VERSION 5.8 ;
BUSBITCHARS "[]" ;
DIVIDERCHAR "/" ;
UNITS
    DATABASE MICRONS 1000 ;
END UNITS

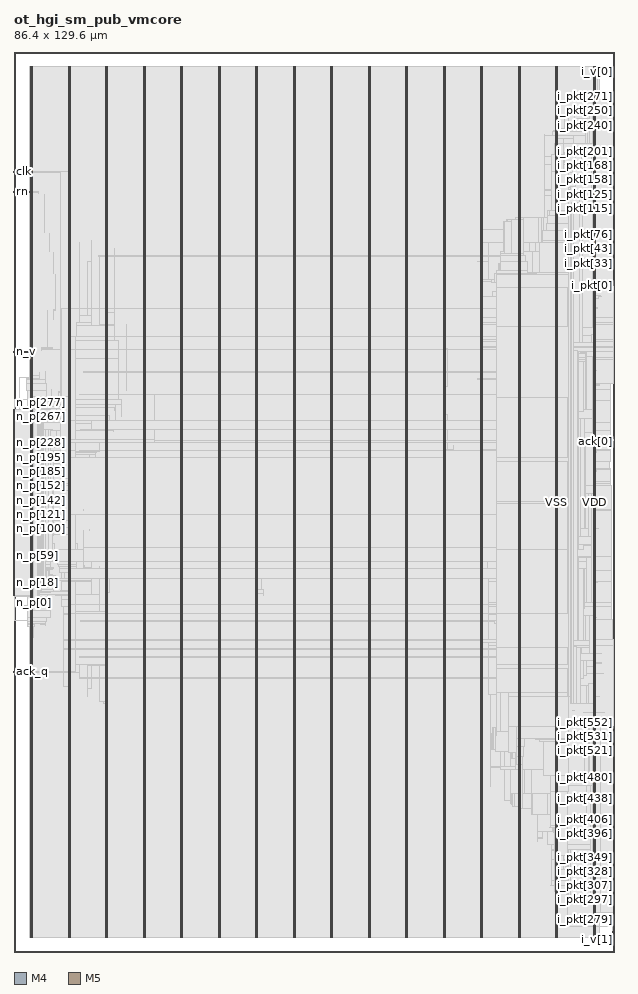
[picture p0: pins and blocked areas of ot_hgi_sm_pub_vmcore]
MACRO ot_hgi_sm_pub_vmcore
  FOREIGN ot_hgi_sm_pub_vmcore 0 0 ;
  CLASS BLOCK ;
  SIZE 86.4 BY 129.6 ;
  PIN ack[0]
    DIRECTION OUTPUT ;
    USE SIGNAL ;
    PORT
      LAYER M4 ;
        RECT  86.358 73.44 86.442 73.464 ;
    END
  END ack[0]
  PIN ack[1]
    DIRECTION OUTPUT ;
    USE SIGNAL ;
    PORT
      LAYER M4 ;
        RECT  86.358 73.536 86.442 73.56 ;
    END
  END ack[1]
  PIN ack_q
    DIRECTION INPUT ;
    USE SIGNAL ;
    PORT
      LAYER M4 ;
        RECT  -0.042 40.32 0.042 40.344 ;
    END
    PORT
      LAYER M4 ;
        RECT  0.012 40.32 2.408 40.344 ;
    END
  END ack_q
  PIN clk
    DIRECTION INPUT ;
    USE SIGNAL ;
    PORT
      LAYER M4 ;
        RECT  -0.042 112.32 0.042 112.344 ;
    END
    PORT
      LAYER M4 ;
        RECT  0.012 112.32 0.025 112.344 ;
    END
    PORT
      LAYER M4 ;
        RECT  0.025 112.32 0.065 112.44 ;
    END
  END clk
  PIN i_pkt[0]
    DIRECTION INPUT ;
    USE SIGNAL ;
    PORT
      LAYER M4 ;
        RECT  86.358 96 86.442 96.024 ;
    END
  END i_pkt[0]
  PIN i_pkt[100]
    DIRECTION INPUT ;
    USE SIGNAL ;
    PORT
      LAYER M4 ;
        RECT  86.358 105.6 86.442 105.624 ;
    END
  END i_pkt[100]
  PIN i_pkt[101]
    DIRECTION INPUT ;
    USE SIGNAL ;
    PORT
      LAYER M4 ;
        RECT  86.358 105.696 86.442 105.72 ;
    END
  END i_pkt[101]
  PIN i_pkt[102]
    DIRECTION INPUT ;
    USE SIGNAL ;
    PORT
      LAYER M4 ;
        RECT  86.358 105.792 86.442 105.816 ;
    END
  END i_pkt[102]
  PIN i_pkt[103]
    DIRECTION INPUT ;
    USE SIGNAL ;
    PORT
      LAYER M4 ;
        RECT  86.358 105.888 86.442 105.912 ;
    END
  END i_pkt[103]
  PIN i_pkt[104]
    DIRECTION INPUT ;
    USE SIGNAL ;
    PORT
      LAYER M4 ;
        RECT  86.358 105.984 86.442 106.008 ;
    END
  END i_pkt[104]
  PIN i_pkt[105]
    DIRECTION INPUT ;
    USE SIGNAL ;
    PORT
      LAYER M4 ;
        RECT  86.358 106.08 86.442 106.104 ;
    END
  END i_pkt[105]
  PIN i_pkt[106]
    DIRECTION INPUT ;
    USE SIGNAL ;
    PORT
      LAYER M4 ;
        RECT  86.358 106.176 86.442 106.2 ;
    END
  END i_pkt[106]
  PIN i_pkt[107]
    DIRECTION INPUT ;
    USE SIGNAL ;
    PORT
      LAYER M4 ;
        RECT  86.358 106.272 86.442 106.296 ;
    END
  END i_pkt[107]
  PIN i_pkt[108]
    DIRECTION INPUT ;
    USE SIGNAL ;
    PORT
      LAYER M4 ;
        RECT  86.358 106.368 86.442 106.392 ;
    END
  END i_pkt[108]
  PIN i_pkt[109]
    DIRECTION INPUT ;
    USE SIGNAL ;
    PORT
      LAYER M4 ;
        RECT  86.358 106.464 86.442 106.488 ;
    END
  END i_pkt[109]
  PIN i_pkt[10]
    DIRECTION INPUT ;
    USE SIGNAL ;
    PORT
      LAYER M4 ;
        RECT  86.358 96.96 86.442 96.984 ;
    END
  END i_pkt[10]
  PIN i_pkt[110]
    DIRECTION INPUT ;
    USE SIGNAL ;
    PORT
      LAYER M4 ;
        RECT  86.358 106.56 86.442 106.584 ;
    END
  END i_pkt[110]
  PIN i_pkt[111]
    DIRECTION INPUT ;
    USE SIGNAL ;
    PORT
      LAYER M4 ;
        RECT  86.358 106.656 86.442 106.68 ;
    END
  END i_pkt[111]
  PIN i_pkt[112]
    DIRECTION INPUT ;
    USE SIGNAL ;
    PORT
      LAYER M4 ;
        RECT  86.358 106.752 86.442 106.776 ;
    END
  END i_pkt[112]
  PIN i_pkt[113]
    DIRECTION INPUT ;
    USE SIGNAL ;
    PORT
      LAYER M4 ;
        RECT  86.358 106.848 86.442 106.872 ;
    END
  END i_pkt[113]
  PIN i_pkt[114]
    DIRECTION INPUT ;
    USE SIGNAL ;
    PORT
      LAYER M4 ;
        RECT  86.358 106.944 86.442 106.968 ;
    END
  END i_pkt[114]
  PIN i_pkt[115]
    DIRECTION INPUT ;
    USE SIGNAL ;
    PORT
      LAYER M4 ;
        RECT  86.358 107.04 86.442 107.064 ;
    END
  END i_pkt[115]
  PIN i_pkt[116]
    DIRECTION INPUT ;
    USE SIGNAL ;
    PORT
      LAYER M4 ;
        RECT  86.358 107.136 86.442 107.16 ;
    END
  END i_pkt[116]
  PIN i_pkt[117]
    DIRECTION INPUT ;
    USE SIGNAL ;
    PORT
      LAYER M4 ;
        RECT  86.358 107.232 86.442 107.256 ;
    END
  END i_pkt[117]
  PIN i_pkt[118]
    DIRECTION INPUT ;
    USE SIGNAL ;
    PORT
      LAYER M4 ;
        RECT  86.358 107.328 86.442 107.352 ;
    END
  END i_pkt[118]
  PIN i_pkt[119]
    DIRECTION INPUT ;
    USE SIGNAL ;
    PORT
      LAYER M4 ;
        RECT  86.358 107.424 86.442 107.448 ;
    END
  END i_pkt[119]
  PIN i_pkt[11]
    DIRECTION INPUT ;
    USE SIGNAL ;
    PORT
      LAYER M4 ;
        RECT  86.358 97.056 86.442 97.08 ;
    END
  END i_pkt[11]
  PIN i_pkt[120]
    DIRECTION INPUT ;
    USE SIGNAL ;
    PORT
      LAYER M4 ;
        RECT  86.358 107.52 86.442 107.544 ;
    END
  END i_pkt[120]
  PIN i_pkt[121]
    DIRECTION INPUT ;
    USE SIGNAL ;
    PORT
      LAYER M4 ;
        RECT  86.358 107.616 86.442 107.64 ;
    END
  END i_pkt[121]
  PIN i_pkt[122]
    DIRECTION INPUT ;
    USE SIGNAL ;
    PORT
      LAYER M4 ;
        RECT  86.358 107.712 86.442 107.736 ;
    END
  END i_pkt[122]
  PIN i_pkt[123]
    DIRECTION INPUT ;
    USE SIGNAL ;
    PORT
      LAYER M4 ;
        RECT  86.358 107.808 86.442 107.832 ;
    END
  END i_pkt[123]
  PIN i_pkt[124]
    DIRECTION INPUT ;
    USE SIGNAL ;
    PORT
      LAYER M4 ;
        RECT  86.358 107.904 86.442 107.928 ;
    END
  END i_pkt[124]
  PIN i_pkt[125]
    DIRECTION INPUT ;
    USE SIGNAL ;
    PORT
      LAYER M4 ;
        RECT  86.358 108 86.442 108.024 ;
    END
  END i_pkt[125]
  PIN i_pkt[126]
    DIRECTION INPUT ;
    USE SIGNAL ;
    PORT
      LAYER M4 ;
        RECT  86.358 108.096 86.442 108.12 ;
    END
  END i_pkt[126]
  PIN i_pkt[127]
    DIRECTION INPUT ;
    USE SIGNAL ;
    PORT
      LAYER M4 ;
        RECT  86.358 108.192 86.442 108.216 ;
    END
  END i_pkt[127]
  PIN i_pkt[128]
    DIRECTION INPUT ;
    USE SIGNAL ;
    PORT
      LAYER M4 ;
        RECT  86.358 108.288 86.442 108.312 ;
    END
  END i_pkt[128]
  PIN i_pkt[129]
    DIRECTION INPUT ;
    USE SIGNAL ;
    PORT
      LAYER M4 ;
        RECT  86.358 108.384 86.442 108.408 ;
    END
  END i_pkt[129]
  PIN i_pkt[12]
    DIRECTION INPUT ;
    USE SIGNAL ;
    PORT
      LAYER M4 ;
        RECT  86.358 97.152 86.442 97.176 ;
    END
  END i_pkt[12]
  PIN i_pkt[130]
    DIRECTION INPUT ;
    USE SIGNAL ;
    PORT
      LAYER M4 ;
        RECT  86.358 108.48 86.442 108.504 ;
    END
  END i_pkt[130]
  PIN i_pkt[131]
    DIRECTION INPUT ;
    USE SIGNAL ;
    PORT
      LAYER M4 ;
        RECT  86.358 108.576 86.442 108.6 ;
    END
  END i_pkt[131]
  PIN i_pkt[132]
    DIRECTION INPUT ;
    USE SIGNAL ;
    PORT
      LAYER M4 ;
        RECT  86.358 108.672 86.442 108.696 ;
    END
  END i_pkt[132]
  PIN i_pkt[133]
    DIRECTION INPUT ;
    USE SIGNAL ;
    PORT
      LAYER M4 ;
        RECT  86.358 108.768 86.442 108.792 ;
    END
  END i_pkt[133]
  PIN i_pkt[134]
    DIRECTION INPUT ;
    USE SIGNAL ;
    PORT
      LAYER M4 ;
        RECT  86.358 108.864 86.442 108.888 ;
    END
  END i_pkt[134]
  PIN i_pkt[135]
    DIRECTION INPUT ;
    USE SIGNAL ;
    PORT
      LAYER M4 ;
        RECT  86.358 108.96 86.442 108.984 ;
    END
  END i_pkt[135]
  PIN i_pkt[136]
    DIRECTION INPUT ;
    USE SIGNAL ;
    PORT
      LAYER M4 ;
        RECT  86.358 109.056 86.442 109.08 ;
    END
  END i_pkt[136]
  PIN i_pkt[137]
    DIRECTION INPUT ;
    USE SIGNAL ;
    PORT
      LAYER M4 ;
        RECT  86.358 109.152 86.442 109.176 ;
    END
  END i_pkt[137]
  PIN i_pkt[138]
    DIRECTION INPUT ;
    USE SIGNAL ;
    PORT
      LAYER M4 ;
        RECT  86.358 109.248 86.442 109.272 ;
    END
  END i_pkt[138]
  PIN i_pkt[139]
    DIRECTION INPUT ;
    USE SIGNAL ;
    PORT
      LAYER M4 ;
        RECT  86.358 109.344 86.442 109.368 ;
    END
  END i_pkt[139]
  PIN i_pkt[13]
    DIRECTION INPUT ;
    USE SIGNAL ;
    PORT
      LAYER M4 ;
        RECT  86.358 97.248 86.442 97.272 ;
    END
  END i_pkt[13]
  PIN i_pkt[140]
    DIRECTION INPUT ;
    USE SIGNAL ;
    PORT
      LAYER M4 ;
        RECT  86.358 109.44 86.442 109.464 ;
    END
  END i_pkt[140]
  PIN i_pkt[141]
    DIRECTION INPUT ;
    USE SIGNAL ;
    PORT
      LAYER M4 ;
        RECT  86.358 109.536 86.442 109.56 ;
    END
  END i_pkt[141]
  PIN i_pkt[142]
    DIRECTION INPUT ;
    USE SIGNAL ;
    PORT
      LAYER M4 ;
        RECT  86.358 109.632 86.442 109.656 ;
    END
  END i_pkt[142]
  PIN i_pkt[143]
    DIRECTION INPUT ;
    USE SIGNAL ;
    PORT
      LAYER M4 ;
        RECT  86.358 109.728 86.442 109.752 ;
    END
  END i_pkt[143]
  PIN i_pkt[144]
    DIRECTION INPUT ;
    USE SIGNAL ;
    PORT
      LAYER M4 ;
        RECT  86.358 109.824 86.442 109.848 ;
    END
  END i_pkt[144]
  PIN i_pkt[145]
    DIRECTION INPUT ;
    USE SIGNAL ;
    PORT
      LAYER M4 ;
        RECT  86.358 109.92 86.442 109.944 ;
    END
  END i_pkt[145]
  PIN i_pkt[146]
    DIRECTION INPUT ;
    USE SIGNAL ;
    PORT
      LAYER M4 ;
        RECT  86.358 110.016 86.442 110.04 ;
    END
  END i_pkt[146]
  PIN i_pkt[147]
    DIRECTION INPUT ;
    USE SIGNAL ;
    PORT
      LAYER M4 ;
        RECT  86.358 110.112 86.442 110.136 ;
    END
  END i_pkt[147]
  PIN i_pkt[148]
    DIRECTION INPUT ;
    USE SIGNAL ;
    PORT
      LAYER M4 ;
        RECT  86.358 110.208 86.442 110.232 ;
    END
  END i_pkt[148]
  PIN i_pkt[149]
    DIRECTION INPUT ;
    USE SIGNAL ;
    PORT
      LAYER M4 ;
        RECT  86.358 110.304 86.442 110.328 ;
    END
  END i_pkt[149]
  PIN i_pkt[14]
    DIRECTION INPUT ;
    USE SIGNAL ;
    PORT
      LAYER M4 ;
        RECT  86.358 97.344 86.442 97.368 ;
    END
  END i_pkt[14]
  PIN i_pkt[150]
    DIRECTION INPUT ;
    USE SIGNAL ;
    PORT
      LAYER M4 ;
        RECT  86.358 110.4 86.442 110.424 ;
    END
  END i_pkt[150]
  PIN i_pkt[151]
    DIRECTION INPUT ;
    USE SIGNAL ;
    PORT
      LAYER M4 ;
        RECT  86.358 110.496 86.442 110.52 ;
    END
  END i_pkt[151]
  PIN i_pkt[152]
    DIRECTION INPUT ;
    USE SIGNAL ;
    PORT
      LAYER M4 ;
        RECT  86.358 110.592 86.442 110.616 ;
    END
  END i_pkt[152]
  PIN i_pkt[153]
    DIRECTION INPUT ;
    USE SIGNAL ;
    PORT
      LAYER M4 ;
        RECT  86.358 110.688 86.442 110.712 ;
    END
  END i_pkt[153]
  PIN i_pkt[154]
    DIRECTION INPUT ;
    USE SIGNAL ;
    PORT
      LAYER M4 ;
        RECT  86.358 110.784 86.442 110.808 ;
    END
  END i_pkt[154]
  PIN i_pkt[155]
    DIRECTION INPUT ;
    USE SIGNAL ;
    PORT
      LAYER M4 ;
        RECT  86.358 110.88 86.442 110.904 ;
    END
  END i_pkt[155]
  PIN i_pkt[156]
    DIRECTION INPUT ;
    USE SIGNAL ;
    PORT
      LAYER M4 ;
        RECT  86.358 110.976 86.442 111 ;
    END
  END i_pkt[156]
  PIN i_pkt[157]
    DIRECTION INPUT ;
    USE SIGNAL ;
    PORT
      LAYER M4 ;
        RECT  86.358 111.072 86.442 111.096 ;
    END
  END i_pkt[157]
  PIN i_pkt[158]
    DIRECTION INPUT ;
    USE SIGNAL ;
    PORT
      LAYER M4 ;
        RECT  86.358 111.168 86.442 111.192 ;
    END
  END i_pkt[158]
  PIN i_pkt[159]
    DIRECTION INPUT ;
    USE SIGNAL ;
    PORT
      LAYER M4 ;
        RECT  86.358 111.264 86.442 111.288 ;
    END
  END i_pkt[159]
  PIN i_pkt[15]
    DIRECTION INPUT ;
    USE SIGNAL ;
    PORT
      LAYER M4 ;
        RECT  86.358 97.44 86.442 97.464 ;
    END
  END i_pkt[15]
  PIN i_pkt[160]
    DIRECTION INPUT ;
    USE SIGNAL ;
    PORT
      LAYER M4 ;
        RECT  86.358 111.36 86.442 111.384 ;
    END
  END i_pkt[160]
  PIN i_pkt[161]
    DIRECTION INPUT ;
    USE SIGNAL ;
    PORT
      LAYER M4 ;
        RECT  86.358 111.456 86.442 111.48 ;
    END
  END i_pkt[161]
  PIN i_pkt[162]
    DIRECTION INPUT ;
    USE SIGNAL ;
    PORT
      LAYER M4 ;
        RECT  86.358 111.552 86.442 111.576 ;
    END
  END i_pkt[162]
  PIN i_pkt[163]
    DIRECTION INPUT ;
    USE SIGNAL ;
    PORT
      LAYER M4 ;
        RECT  86.358 111.648 86.442 111.672 ;
    END
  END i_pkt[163]
  PIN i_pkt[164]
    DIRECTION INPUT ;
    USE SIGNAL ;
    PORT
      LAYER M4 ;
        RECT  86.358 111.744 86.442 111.768 ;
    END
  END i_pkt[164]
  PIN i_pkt[165]
    DIRECTION INPUT ;
    USE SIGNAL ;
    PORT
      LAYER M4 ;
        RECT  86.358 111.84 86.442 111.864 ;
    END
  END i_pkt[165]
  PIN i_pkt[166]
    DIRECTION INPUT ;
    USE SIGNAL ;
    PORT
      LAYER M4 ;
        RECT  86.358 111.936 86.442 111.96 ;
    END
  END i_pkt[166]
  PIN i_pkt[167]
    DIRECTION INPUT ;
    USE SIGNAL ;
    PORT
      LAYER M4 ;
        RECT  86.358 112.032 86.442 112.056 ;
    END
  END i_pkt[167]
  PIN i_pkt[168]
    DIRECTION INPUT ;
    USE SIGNAL ;
    PORT
      LAYER M4 ;
        RECT  86.358 112.128 86.442 112.152 ;
    END
  END i_pkt[168]
  PIN i_pkt[169]
    DIRECTION INPUT ;
    USE SIGNAL ;
    PORT
      LAYER M4 ;
        RECT  86.358 112.224 86.442 112.248 ;
    END
  END i_pkt[169]
  PIN i_pkt[16]
    DIRECTION INPUT ;
    USE SIGNAL ;
    PORT
      LAYER M4 ;
        RECT  86.358 97.536 86.442 97.56 ;
    END
  END i_pkt[16]
  PIN i_pkt[170]
    DIRECTION INPUT ;
    USE SIGNAL ;
    PORT
      LAYER M4 ;
        RECT  86.358 112.32 86.442 112.344 ;
    END
  END i_pkt[170]
  PIN i_pkt[171]
    DIRECTION INPUT ;
    USE SIGNAL ;
    PORT
      LAYER M4 ;
        RECT  86.358 112.416 86.442 112.44 ;
    END
  END i_pkt[171]
  PIN i_pkt[172]
    DIRECTION INPUT ;
    USE SIGNAL ;
    PORT
      LAYER M4 ;
        RECT  86.358 112.512 86.442 112.536 ;
    END
  END i_pkt[172]
  PIN i_pkt[173]
    DIRECTION INPUT ;
    USE SIGNAL ;
    PORT
      LAYER M4 ;
        RECT  86.358 112.608 86.442 112.632 ;
    END
  END i_pkt[173]
  PIN i_pkt[174]
    DIRECTION INPUT ;
    USE SIGNAL ;
    PORT
      LAYER M4 ;
        RECT  86.358 112.704 86.442 112.728 ;
    END
  END i_pkt[174]
  PIN i_pkt[175]
    DIRECTION INPUT ;
    USE SIGNAL ;
    PORT
      LAYER M4 ;
        RECT  86.358 112.8 86.442 112.824 ;
    END
  END i_pkt[175]
  PIN i_pkt[176]
    DIRECTION INPUT ;
    USE SIGNAL ;
    PORT
      LAYER M4 ;
        RECT  86.358 112.896 86.442 112.92 ;
    END
  END i_pkt[176]
  PIN i_pkt[177]
    DIRECTION INPUT ;
    USE SIGNAL ;
    PORT
      LAYER M4 ;
        RECT  86.358 112.992 86.442 113.016 ;
    END
  END i_pkt[177]
  PIN i_pkt[178]
    DIRECTION INPUT ;
    USE SIGNAL ;
    PORT
      LAYER M4 ;
        RECT  86.358 113.088 86.442 113.112 ;
    END
  END i_pkt[178]
  PIN i_pkt[179]
    DIRECTION INPUT ;
    USE SIGNAL ;
    PORT
      LAYER M4 ;
        RECT  86.358 113.184 86.442 113.208 ;
    END
  END i_pkt[179]
  PIN i_pkt[17]
    DIRECTION INPUT ;
    USE SIGNAL ;
    PORT
      LAYER M4 ;
        RECT  86.358 97.632 86.442 97.656 ;
    END
  END i_pkt[17]
  PIN i_pkt[180]
    DIRECTION INPUT ;
    USE SIGNAL ;
    PORT
      LAYER M4 ;
        RECT  86.358 113.28 86.442 113.304 ;
    END
  END i_pkt[180]
  PIN i_pkt[181]
    DIRECTION INPUT ;
    USE SIGNAL ;
    PORT
      LAYER M4 ;
        RECT  86.358 113.376 86.442 113.4 ;
    END
  END i_pkt[181]
  PIN i_pkt[182]
    DIRECTION INPUT ;
    USE SIGNAL ;
    PORT
      LAYER M4 ;
        RECT  86.358 113.472 86.442 113.496 ;
    END
  END i_pkt[182]
  PIN i_pkt[183]
    DIRECTION INPUT ;
    USE SIGNAL ;
    PORT
      LAYER M4 ;
        RECT  86.358 113.568 86.442 113.592 ;
    END
  END i_pkt[183]
  PIN i_pkt[184]
    DIRECTION INPUT ;
    USE SIGNAL ;
    PORT
      LAYER M4 ;
        RECT  86.358 113.664 86.442 113.688 ;
    END
  END i_pkt[184]
  PIN i_pkt[185]
    DIRECTION INPUT ;
    USE SIGNAL ;
    PORT
      LAYER M4 ;
        RECT  86.358 113.76 86.442 113.784 ;
    END
  END i_pkt[185]
  PIN i_pkt[186]
    DIRECTION INPUT ;
    USE SIGNAL ;
    PORT
      LAYER M4 ;
        RECT  86.358 113.856 86.442 113.88 ;
    END
  END i_pkt[186]
  PIN i_pkt[187]
    DIRECTION INPUT ;
    USE SIGNAL ;
    PORT
      LAYER M4 ;
        RECT  86.358 113.952 86.442 113.976 ;
    END
  END i_pkt[187]
  PIN i_pkt[188]
    DIRECTION INPUT ;
    USE SIGNAL ;
    PORT
      LAYER M4 ;
        RECT  86.358 114.048 86.442 114.072 ;
    END
  END i_pkt[188]
  PIN i_pkt[189]
    DIRECTION INPUT ;
    USE SIGNAL ;
    PORT
      LAYER M4 ;
        RECT  86.358 114.144 86.442 114.168 ;
    END
  END i_pkt[189]
  PIN i_pkt[18]
    DIRECTION INPUT ;
    USE SIGNAL ;
    PORT
      LAYER M4 ;
        RECT  86.358 97.728 86.442 97.752 ;
    END
  END i_pkt[18]
  PIN i_pkt[190]
    DIRECTION INPUT ;
    USE SIGNAL ;
    PORT
      LAYER M4 ;
        RECT  86.358 114.24 86.442 114.264 ;
    END
  END i_pkt[190]
  PIN i_pkt[191]
    DIRECTION INPUT ;
    USE SIGNAL ;
    PORT
      LAYER M4 ;
        RECT  86.358 114.336 86.442 114.36 ;
    END
  END i_pkt[191]
  PIN i_pkt[192]
    DIRECTION INPUT ;
    USE SIGNAL ;
    PORT
      LAYER M4 ;
        RECT  86.358 114.432 86.442 114.456 ;
    END
  END i_pkt[192]
  PIN i_pkt[193]
    DIRECTION INPUT ;
    USE SIGNAL ;
    PORT
      LAYER M4 ;
        RECT  86.358 114.528 86.442 114.552 ;
    END
  END i_pkt[193]
  PIN i_pkt[194]
    DIRECTION INPUT ;
    USE SIGNAL ;
    PORT
      LAYER M4 ;
        RECT  86.358 114.624 86.442 114.648 ;
    END
  END i_pkt[194]
  PIN i_pkt[195]
    DIRECTION INPUT ;
    USE SIGNAL ;
    PORT
      LAYER M4 ;
        RECT  86.358 114.72 86.442 114.744 ;
    END
  END i_pkt[195]
  PIN i_pkt[196]
    DIRECTION INPUT ;
    USE SIGNAL ;
    PORT
      LAYER M4 ;
        RECT  86.358 114.816 86.442 114.84 ;
    END
  END i_pkt[196]
  PIN i_pkt[197]
    DIRECTION INPUT ;
    USE SIGNAL ;
    PORT
      LAYER M4 ;
        RECT  86.358 114.912 86.442 114.936 ;
    END
  END i_pkt[197]
  PIN i_pkt[198]
    DIRECTION INPUT ;
    USE SIGNAL ;
    PORT
      LAYER M4 ;
        RECT  86.358 115.008 86.442 115.032 ;
    END
  END i_pkt[198]
  PIN i_pkt[199]
    DIRECTION INPUT ;
    USE SIGNAL ;
    PORT
      LAYER M4 ;
        RECT  86.358 115.104 86.442 115.128 ;
    END
  END i_pkt[199]
  PIN i_pkt[19]
    DIRECTION INPUT ;
    USE SIGNAL ;
    PORT
      LAYER M4 ;
        RECT  86.358 97.824 86.442 97.848 ;
    END
  END i_pkt[19]
  PIN i_pkt[1]
    DIRECTION INPUT ;
    USE SIGNAL ;
    PORT
      LAYER M4 ;
        RECT  86.358 96.096 86.442 96.12 ;
    END
  END i_pkt[1]
  PIN i_pkt[200]
    DIRECTION INPUT ;
    USE SIGNAL ;
    PORT
      LAYER M4 ;
        RECT  86.358 115.2 86.442 115.224 ;
    END
  END i_pkt[200]
  PIN i_pkt[201]
    DIRECTION INPUT ;
    USE SIGNAL ;
    PORT
      LAYER M4 ;
        RECT  86.358 115.296 86.442 115.32 ;
    END
  END i_pkt[201]
  PIN i_pkt[202]
    DIRECTION INPUT ;
    USE SIGNAL ;
    PORT
      LAYER M4 ;
        RECT  86.358 115.392 86.442 115.416 ;
    END
  END i_pkt[202]
  PIN i_pkt[203]
    DIRECTION INPUT ;
    USE SIGNAL ;
    PORT
      LAYER M4 ;
        RECT  86.358 115.488 86.442 115.512 ;
    END
  END i_pkt[203]
  PIN i_pkt[204]
    DIRECTION INPUT ;
    USE SIGNAL ;
    PORT
      LAYER M4 ;
        RECT  86.358 115.584 86.442 115.608 ;
    END
  END i_pkt[204]
  PIN i_pkt[205]
    DIRECTION INPUT ;
    USE SIGNAL ;
    PORT
      LAYER M4 ;
        RECT  86.358 115.68 86.442 115.704 ;
    END
  END i_pkt[205]
  PIN i_pkt[206]
    DIRECTION INPUT ;
    USE SIGNAL ;
    PORT
      LAYER M4 ;
        RECT  86.358 115.776 86.442 115.8 ;
    END
  END i_pkt[206]
  PIN i_pkt[207]
    DIRECTION INPUT ;
    USE SIGNAL ;
    PORT
      LAYER M4 ;
        RECT  86.358 115.872 86.442 115.896 ;
    END
  END i_pkt[207]
  PIN i_pkt[208]
    DIRECTION INPUT ;
    USE SIGNAL ;
    PORT
      LAYER M4 ;
        RECT  86.358 115.968 86.442 115.992 ;
    END
  END i_pkt[208]
  PIN i_pkt[209]
    DIRECTION INPUT ;
    USE SIGNAL ;
    PORT
      LAYER M4 ;
        RECT  86.358 116.064 86.442 116.088 ;
    END
  END i_pkt[209]
  PIN i_pkt[20]
    DIRECTION INPUT ;
    USE SIGNAL ;
    PORT
      LAYER M4 ;
        RECT  86.358 97.92 86.442 97.944 ;
    END
  END i_pkt[20]
  PIN i_pkt[210]
    DIRECTION INPUT ;
    USE SIGNAL ;
    PORT
      LAYER M4 ;
        RECT  86.358 116.16 86.442 116.184 ;
    END
  END i_pkt[210]
  PIN i_pkt[211]
    DIRECTION INPUT ;
    USE SIGNAL ;
    PORT
      LAYER M4 ;
        RECT  86.358 116.256 86.442 116.28 ;
    END
  END i_pkt[211]
  PIN i_pkt[212]
    DIRECTION INPUT ;
    USE SIGNAL ;
    PORT
      LAYER M4 ;
        RECT  86.358 116.352 86.442 116.376 ;
    END
  END i_pkt[212]
  PIN i_pkt[213]
    DIRECTION INPUT ;
    USE SIGNAL ;
    PORT
      LAYER M4 ;
        RECT  86.358 116.448 86.442 116.472 ;
    END
  END i_pkt[213]
  PIN i_pkt[214]
    DIRECTION INPUT ;
    USE SIGNAL ;
    PORT
      LAYER M4 ;
        RECT  86.358 116.544 86.442 116.568 ;
    END
  END i_pkt[214]
  PIN i_pkt[215]
    DIRECTION INPUT ;
    USE SIGNAL ;
    PORT
      LAYER M4 ;
        RECT  86.358 116.64 86.442 116.664 ;
    END
  END i_pkt[215]
  PIN i_pkt[216]
    DIRECTION INPUT ;
    USE SIGNAL ;
    PORT
      LAYER M4 ;
        RECT  86.358 116.736 86.442 116.76 ;
    END
  END i_pkt[216]
  PIN i_pkt[217]
    DIRECTION INPUT ;
    USE SIGNAL ;
    PORT
      LAYER M4 ;
        RECT  86.358 116.832 86.442 116.856 ;
    END
  END i_pkt[217]
  PIN i_pkt[218]
    DIRECTION INPUT ;
    USE SIGNAL ;
    PORT
      LAYER M4 ;
        RECT  86.358 116.928 86.442 116.952 ;
    END
  END i_pkt[218]
  PIN i_pkt[219]
    DIRECTION INPUT ;
    USE SIGNAL ;
    PORT
      LAYER M4 ;
        RECT  86.358 117.024 86.442 117.048 ;
    END
  END i_pkt[219]
  PIN i_pkt[21]
    DIRECTION INPUT ;
    USE SIGNAL ;
    PORT
      LAYER M4 ;
        RECT  86.358 98.016 86.442 98.04 ;
    END
  END i_pkt[21]
  PIN i_pkt[220]
    DIRECTION INPUT ;
    USE SIGNAL ;
    PORT
      LAYER M4 ;
        RECT  86.358 117.12 86.442 117.144 ;
    END
  END i_pkt[220]
  PIN i_pkt[221]
    DIRECTION INPUT ;
    USE SIGNAL ;
    PORT
      LAYER M4 ;
        RECT  86.358 117.216 86.442 117.24 ;
    END
  END i_pkt[221]
  PIN i_pkt[222]
    DIRECTION INPUT ;
    USE SIGNAL ;
    PORT
      LAYER M4 ;
        RECT  86.358 117.312 86.442 117.336 ;
    END
  END i_pkt[222]
  PIN i_pkt[223]
    DIRECTION INPUT ;
    USE SIGNAL ;
    PORT
      LAYER M4 ;
        RECT  86.358 117.408 86.442 117.432 ;
    END
  END i_pkt[223]
  PIN i_pkt[224]
    DIRECTION INPUT ;
    USE SIGNAL ;
    PORT
      LAYER M4 ;
        RECT  86.358 117.504 86.442 117.528 ;
    END
  END i_pkt[224]
  PIN i_pkt[225]
    DIRECTION INPUT ;
    USE SIGNAL ;
    PORT
      LAYER M4 ;
        RECT  86.358 117.6 86.442 117.624 ;
    END
  END i_pkt[225]
  PIN i_pkt[226]
    DIRECTION INPUT ;
    USE SIGNAL ;
    PORT
      LAYER M4 ;
        RECT  86.358 117.696 86.442 117.72 ;
    END
  END i_pkt[226]
  PIN i_pkt[227]
    DIRECTION INPUT ;
    USE SIGNAL ;
    PORT
      LAYER M4 ;
        RECT  86.358 117.792 86.442 117.816 ;
    END
  END i_pkt[227]
  PIN i_pkt[228]
    DIRECTION INPUT ;
    USE SIGNAL ;
    PORT
      LAYER M4 ;
        RECT  86.358 117.888 86.442 117.912 ;
    END
  END i_pkt[228]
  PIN i_pkt[229]
    DIRECTION INPUT ;
    USE SIGNAL ;
    PORT
      LAYER M4 ;
        RECT  86.358 117.984 86.442 118.008 ;
    END
  END i_pkt[229]
  PIN i_pkt[22]
    DIRECTION INPUT ;
    USE SIGNAL ;
    PORT
      LAYER M4 ;
        RECT  86.358 98.112 86.442 98.136 ;
    END
  END i_pkt[22]
  PIN i_pkt[230]
    DIRECTION INPUT ;
    USE SIGNAL ;
    PORT
      LAYER M4 ;
        RECT  86.358 118.08 86.442 118.104 ;
    END
  END i_pkt[230]
  PIN i_pkt[231]
    DIRECTION INPUT ;
    USE SIGNAL ;
    PORT
      LAYER M4 ;
        RECT  86.358 118.176 86.442 118.2 ;
    END
  END i_pkt[231]
  PIN i_pkt[232]
    DIRECTION INPUT ;
    USE SIGNAL ;
    PORT
      LAYER M4 ;
        RECT  86.358 118.272 86.442 118.296 ;
    END
  END i_pkt[232]
  PIN i_pkt[233]
    DIRECTION INPUT ;
    USE SIGNAL ;
    PORT
      LAYER M4 ;
        RECT  86.358 118.368 86.442 118.392 ;
    END
  END i_pkt[233]
  PIN i_pkt[234]
    DIRECTION INPUT ;
    USE SIGNAL ;
    PORT
      LAYER M4 ;
        RECT  86.358 118.464 86.442 118.488 ;
    END
  END i_pkt[234]
  PIN i_pkt[235]
    DIRECTION INPUT ;
    USE SIGNAL ;
    PORT
      LAYER M4 ;
        RECT  86.358 118.56 86.442 118.584 ;
    END
  END i_pkt[235]
  PIN i_pkt[236]
    DIRECTION INPUT ;
    USE SIGNAL ;
    PORT
      LAYER M4 ;
        RECT  86.358 118.656 86.442 118.68 ;
    END
  END i_pkt[236]
  PIN i_pkt[237]
    DIRECTION INPUT ;
    USE SIGNAL ;
    PORT
      LAYER M4 ;
        RECT  86.358 118.752 86.442 118.776 ;
    END
  END i_pkt[237]
  PIN i_pkt[238]
    DIRECTION INPUT ;
    USE SIGNAL ;
    PORT
      LAYER M4 ;
        RECT  86.358 118.848 86.442 118.872 ;
    END
  END i_pkt[238]
  PIN i_pkt[239]
    DIRECTION INPUT ;
    USE SIGNAL ;
    PORT
      LAYER M4 ;
        RECT  86.358 118.944 86.442 118.968 ;
    END
  END i_pkt[239]
  PIN i_pkt[23]
    DIRECTION INPUT ;
    USE SIGNAL ;
    PORT
      LAYER M4 ;
        RECT  86.358 98.208 86.442 98.232 ;
    END
  END i_pkt[23]
  PIN i_pkt[240]
    DIRECTION INPUT ;
    USE SIGNAL ;
    PORT
      LAYER M4 ;
        RECT  86.358 119.04 86.442 119.064 ;
    END
  END i_pkt[240]
  PIN i_pkt[241]
    DIRECTION INPUT ;
    USE SIGNAL ;
    PORT
      LAYER M4 ;
        RECT  86.358 119.136 86.442 119.16 ;
    END
  END i_pkt[241]
  PIN i_pkt[242]
    DIRECTION INPUT ;
    USE SIGNAL ;
    PORT
      LAYER M4 ;
        RECT  86.358 119.232 86.442 119.256 ;
    END
  END i_pkt[242]
  PIN i_pkt[243]
    DIRECTION INPUT ;
    USE SIGNAL ;
    PORT
      LAYER M4 ;
        RECT  86.358 119.328 86.442 119.352 ;
    END
  END i_pkt[243]
  PIN i_pkt[244]
    DIRECTION INPUT ;
    USE SIGNAL ;
    PORT
      LAYER M4 ;
        RECT  86.358 119.424 86.442 119.448 ;
    END
  END i_pkt[244]
  PIN i_pkt[245]
    DIRECTION INPUT ;
    USE SIGNAL ;
    PORT
      LAYER M4 ;
        RECT  86.358 119.52 86.442 119.544 ;
    END
  END i_pkt[245]
  PIN i_pkt[246]
    DIRECTION INPUT ;
    USE SIGNAL ;
    PORT
      LAYER M4 ;
        RECT  86.358 119.616 86.442 119.64 ;
    END
  END i_pkt[246]
  PIN i_pkt[247]
    DIRECTION INPUT ;
    USE SIGNAL ;
    PORT
      LAYER M4 ;
        RECT  86.358 119.712 86.442 119.736 ;
    END
  END i_pkt[247]
  PIN i_pkt[248]
    DIRECTION INPUT ;
    USE SIGNAL ;
    PORT
      LAYER M4 ;
        RECT  86.358 119.808 86.442 119.832 ;
    END
  END i_pkt[248]
  PIN i_pkt[249]
    DIRECTION INPUT ;
    USE SIGNAL ;
    PORT
      LAYER M4 ;
        RECT  86.358 119.904 86.442 119.928 ;
    END
  END i_pkt[249]
  PIN i_pkt[24]
    DIRECTION INPUT ;
    USE SIGNAL ;
    PORT
      LAYER M4 ;
        RECT  86.358 98.304 86.442 98.328 ;
    END
  END i_pkt[24]
  PIN i_pkt[250]
    DIRECTION INPUT ;
    USE SIGNAL ;
    PORT
      LAYER M4 ;
        RECT  86.358 120 86.442 120.024 ;
    END
  END i_pkt[250]
  PIN i_pkt[251]
    DIRECTION INPUT ;
    USE SIGNAL ;
    PORT
      LAYER M4 ;
        RECT  86.358 120.096 86.442 120.12 ;
    END
  END i_pkt[251]
  PIN i_pkt[252]
    DIRECTION INPUT ;
    USE SIGNAL ;
    PORT
      LAYER M4 ;
        RECT  86.358 120.192 86.442 120.216 ;
    END
  END i_pkt[252]
  PIN i_pkt[253]
    DIRECTION INPUT ;
    USE SIGNAL ;
    PORT
      LAYER M4 ;
        RECT  86.358 120.288 86.442 120.312 ;
    END
  END i_pkt[253]
  PIN i_pkt[254]
    DIRECTION INPUT ;
    USE SIGNAL ;
    PORT
      LAYER M4 ;
        RECT  86.358 120.384 86.442 120.408 ;
    END
  END i_pkt[254]
  PIN i_pkt[255]
    DIRECTION INPUT ;
    USE SIGNAL ;
    PORT
      LAYER M4 ;
        RECT  86.358 120.48 86.442 120.504 ;
    END
  END i_pkt[255]
  PIN i_pkt[256]
    DIRECTION INPUT ;
    USE SIGNAL ;
    PORT
      LAYER M4 ;
        RECT  86.358 120.576 86.442 120.6 ;
    END
  END i_pkt[256]
  PIN i_pkt[257]
    DIRECTION INPUT ;
    USE SIGNAL ;
    PORT
      LAYER M4 ;
        RECT  86.358 120.672 86.442 120.696 ;
    END
  END i_pkt[257]
  PIN i_pkt[258]
    DIRECTION INPUT ;
    USE SIGNAL ;
    PORT
      LAYER M4 ;
        RECT  86.358 120.768 86.442 120.792 ;
    END
  END i_pkt[258]
  PIN i_pkt[259]
    DIRECTION INPUT ;
    USE SIGNAL ;
    PORT
      LAYER M4 ;
        RECT  86.358 120.864 86.442 120.888 ;
    END
  END i_pkt[259]
  PIN i_pkt[25]
    DIRECTION INPUT ;
    USE SIGNAL ;
    PORT
      LAYER M4 ;
        RECT  86.358 98.4 86.442 98.424 ;
    END
  END i_pkt[25]
  PIN i_pkt[260]
    DIRECTION INPUT ;
    USE SIGNAL ;
    PORT
      LAYER M4 ;
        RECT  86.358 120.96 86.442 120.984 ;
    END
  END i_pkt[260]
  PIN i_pkt[261]
    DIRECTION INPUT ;
    USE SIGNAL ;
    PORT
      LAYER M4 ;
        RECT  86.358 121.056 86.442 121.08 ;
    END
  END i_pkt[261]
  PIN i_pkt[262]
    DIRECTION INPUT ;
    USE SIGNAL ;
    PORT
      LAYER M4 ;
        RECT  86.358 121.152 86.442 121.176 ;
    END
  END i_pkt[262]
  PIN i_pkt[263]
    DIRECTION INPUT ;
    USE SIGNAL ;
    PORT
      LAYER M4 ;
        RECT  86.358 121.248 86.442 121.272 ;
    END
  END i_pkt[263]
  PIN i_pkt[264]
    DIRECTION INPUT ;
    USE SIGNAL ;
    PORT
      LAYER M4 ;
        RECT  86.358 121.344 86.442 121.368 ;
    END
  END i_pkt[264]
  PIN i_pkt[265]
    DIRECTION INPUT ;
    USE SIGNAL ;
    PORT
      LAYER M4 ;
        RECT  86.358 121.44 86.442 121.464 ;
    END
  END i_pkt[265]
  PIN i_pkt[266]
    DIRECTION INPUT ;
    USE SIGNAL ;
    PORT
      LAYER M4 ;
        RECT  86.358 121.536 86.442 121.56 ;
    END
  END i_pkt[266]
  PIN i_pkt[267]
    DIRECTION INPUT ;
    USE SIGNAL ;
    PORT
      LAYER M4 ;
        RECT  86.358 121.632 86.442 121.656 ;
    END
  END i_pkt[267]
  PIN i_pkt[268]
    DIRECTION INPUT ;
    USE SIGNAL ;
    PORT
      LAYER M4 ;
        RECT  86.358 121.728 86.442 121.752 ;
    END
  END i_pkt[268]
  PIN i_pkt[269]
    DIRECTION INPUT ;
    USE SIGNAL ;
    PORT
      LAYER M4 ;
        RECT  86.358 121.824 86.442 121.848 ;
    END
  END i_pkt[269]
  PIN i_pkt[26]
    DIRECTION INPUT ;
    USE SIGNAL ;
    PORT
      LAYER M4 ;
        RECT  86.358 98.496 86.442 98.52 ;
    END
  END i_pkt[26]
  PIN i_pkt[270]
    DIRECTION INPUT ;
    USE SIGNAL ;
    PORT
      LAYER M4 ;
        RECT  86.358 121.92 86.442 121.944 ;
    END
  END i_pkt[270]
  PIN i_pkt[271]
    DIRECTION INPUT ;
    USE SIGNAL ;
    PORT
      LAYER M4 ;
        RECT  86.358 122.016 86.442 122.04 ;
    END
  END i_pkt[271]
  PIN i_pkt[272]
    DIRECTION INPUT ;
    USE SIGNAL ;
    PORT
      LAYER M4 ;
        RECT  86.358 122.112 86.442 122.136 ;
    END
  END i_pkt[272]
  PIN i_pkt[273]
    DIRECTION INPUT ;
    USE SIGNAL ;
    PORT
      LAYER M4 ;
        RECT  86.358 122.208 86.442 122.232 ;
    END
  END i_pkt[273]
  PIN i_pkt[274]
    DIRECTION INPUT ;
    USE SIGNAL ;
    PORT
      LAYER M4 ;
        RECT  86.358 122.304 86.442 122.328 ;
    END
  END i_pkt[274]
  PIN i_pkt[275]
    DIRECTION INPUT ;
    USE SIGNAL ;
    PORT
      LAYER M4 ;
        RECT  86.358 122.4 86.442 122.424 ;
    END
  END i_pkt[275]
  PIN i_pkt[276]
    DIRECTION INPUT ;
    USE SIGNAL ;
    PORT
      LAYER M4 ;
        RECT  86.358 122.496 86.442 122.52 ;
    END
  END i_pkt[276]
  PIN i_pkt[277]
    DIRECTION INPUT ;
    USE SIGNAL ;
    PORT
      LAYER M4 ;
        RECT  86.358 122.592 86.442 122.616 ;
    END
  END i_pkt[277]
  PIN i_pkt[278]
    DIRECTION INPUT ;
    USE SIGNAL ;
    PORT
      LAYER M4 ;
        RECT  86.358 122.688 86.442 122.712 ;
    END
  END i_pkt[278]
  PIN i_pkt[279]
    DIRECTION INPUT ;
    USE SIGNAL ;
    PORT
      LAYER M4 ;
        RECT  86.358 5.76 86.442 5.784 ;
    END
  END i_pkt[279]
  PIN i_pkt[27]
    DIRECTION INPUT ;
    USE SIGNAL ;
    PORT
      LAYER M4 ;
        RECT  86.358 98.592 86.442 98.616 ;
    END
  END i_pkt[27]
  PIN i_pkt[280]
    DIRECTION INPUT ;
    USE SIGNAL ;
    PORT
      LAYER M4 ;
        RECT  86.358 5.856 86.442 5.88 ;
    END
  END i_pkt[280]
  PIN i_pkt[281]
    DIRECTION INPUT ;
    USE SIGNAL ;
    PORT
      LAYER M4 ;
        RECT  86.358 5.952 86.442 5.976 ;
    END
  END i_pkt[281]
  PIN i_pkt[282]
    DIRECTION INPUT ;
    USE SIGNAL ;
    PORT
      LAYER M4 ;
        RECT  86.358 6.048 86.442 6.072 ;
    END
  END i_pkt[282]
  PIN i_pkt[283]
    DIRECTION INPUT ;
    USE SIGNAL ;
    PORT
      LAYER M4 ;
        RECT  86.358 6.144 86.442 6.168 ;
    END
  END i_pkt[283]
  PIN i_pkt[284]
    DIRECTION INPUT ;
    USE SIGNAL ;
    PORT
      LAYER M4 ;
        RECT  86.358 6.24 86.442 6.264 ;
    END
  END i_pkt[284]
  PIN i_pkt[285]
    DIRECTION INPUT ;
    USE SIGNAL ;
    PORT
      LAYER M4 ;
        RECT  86.358 6.336 86.442 6.36 ;
    END
  END i_pkt[285]
  PIN i_pkt[286]
    DIRECTION INPUT ;
    USE SIGNAL ;
    PORT
      LAYER M4 ;
        RECT  86.358 6.432 86.442 6.456 ;
    END
  END i_pkt[286]
  PIN i_pkt[287]
    DIRECTION INPUT ;
    USE SIGNAL ;
    PORT
      LAYER M4 ;
        RECT  86.358 6.528 86.442 6.552 ;
    END
  END i_pkt[287]
  PIN i_pkt[288]
    DIRECTION INPUT ;
    USE SIGNAL ;
    PORT
      LAYER M4 ;
        RECT  86.358 6.624 86.442 6.648 ;
    END
  END i_pkt[288]
  PIN i_pkt[289]
    DIRECTION INPUT ;
    USE SIGNAL ;
    PORT
      LAYER M4 ;
        RECT  86.358 6.72 86.442 6.744 ;
    END
  END i_pkt[289]
  PIN i_pkt[28]
    DIRECTION INPUT ;
    USE SIGNAL ;
    PORT
      LAYER M4 ;
        RECT  86.358 98.688 86.442 98.712 ;
    END
  END i_pkt[28]
  PIN i_pkt[290]
    DIRECTION INPUT ;
    USE SIGNAL ;
    PORT
      LAYER M4 ;
        RECT  86.358 6.816 86.442 6.84 ;
    END
  END i_pkt[290]
  PIN i_pkt[291]
    DIRECTION INPUT ;
    USE SIGNAL ;
    PORT
      LAYER M4 ;
        RECT  86.358 6.912 86.442 6.936 ;
    END
  END i_pkt[291]
  PIN i_pkt[292]
    DIRECTION INPUT ;
    USE SIGNAL ;
    PORT
      LAYER M4 ;
        RECT  86.358 7.008 86.442 7.032 ;
    END
  END i_pkt[292]
  PIN i_pkt[293]
    DIRECTION INPUT ;
    USE SIGNAL ;
    PORT
      LAYER M4 ;
        RECT  86.358 7.104 86.442 7.128 ;
    END
  END i_pkt[293]
  PIN i_pkt[294]
    DIRECTION INPUT ;
    USE SIGNAL ;
    PORT
      LAYER M4 ;
        RECT  86.358 7.2 86.442 7.224 ;
    END
  END i_pkt[294]
  PIN i_pkt[295]
    DIRECTION INPUT ;
    USE SIGNAL ;
    PORT
      LAYER M4 ;
        RECT  86.358 7.296 86.442 7.32 ;
    END
  END i_pkt[295]
  PIN i_pkt[296]
    DIRECTION INPUT ;
    USE SIGNAL ;
    PORT
      LAYER M4 ;
        RECT  86.358 7.392 86.442 7.416 ;
    END
  END i_pkt[296]
  PIN i_pkt[297]
    DIRECTION INPUT ;
    USE SIGNAL ;
    PORT
      LAYER M4 ;
        RECT  86.358 7.488 86.442 7.512 ;
    END
  END i_pkt[297]
  PIN i_pkt[298]
    DIRECTION INPUT ;
    USE SIGNAL ;
    PORT
      LAYER M4 ;
        RECT  86.358 7.584 86.442 7.608 ;
    END
  END i_pkt[298]
  PIN i_pkt[299]
    DIRECTION INPUT ;
    USE SIGNAL ;
    PORT
      LAYER M4 ;
        RECT  86.358 7.68 86.442 7.704 ;
    END
  END i_pkt[299]
  PIN i_pkt[29]
    DIRECTION INPUT ;
    USE SIGNAL ;
    PORT
      LAYER M4 ;
        RECT  86.358 98.784 86.442 98.808 ;
    END
  END i_pkt[29]
  PIN i_pkt[2]
    DIRECTION INPUT ;
    USE SIGNAL ;
    PORT
      LAYER M4 ;
        RECT  86.358 96.192 86.442 96.216 ;
    END
  END i_pkt[2]
  PIN i_pkt[300]
    DIRECTION INPUT ;
    USE SIGNAL ;
    PORT
      LAYER M4 ;
        RECT  86.358 7.776 86.442 7.8 ;
    END
  END i_pkt[300]
  PIN i_pkt[301]
    DIRECTION INPUT ;
    USE SIGNAL ;
    PORT
      LAYER M4 ;
        RECT  86.358 7.872 86.442 7.896 ;
    END
  END i_pkt[301]
  PIN i_pkt[302]
    DIRECTION INPUT ;
    USE SIGNAL ;
    PORT
      LAYER M4 ;
        RECT  86.358 7.968 86.442 7.992 ;
    END
  END i_pkt[302]
  PIN i_pkt[303]
    DIRECTION INPUT ;
    USE SIGNAL ;
    PORT
      LAYER M4 ;
        RECT  86.358 8.064 86.442 8.088 ;
    END
  END i_pkt[303]
  PIN i_pkt[304]
    DIRECTION INPUT ;
    USE SIGNAL ;
    PORT
      LAYER M4 ;
        RECT  86.358 8.16 86.442 8.184 ;
    END
  END i_pkt[304]
  PIN i_pkt[305]
    DIRECTION INPUT ;
    USE SIGNAL ;
    PORT
      LAYER M4 ;
        RECT  86.358 8.256 86.442 8.28 ;
    END
  END i_pkt[305]
  PIN i_pkt[306]
    DIRECTION INPUT ;
    USE SIGNAL ;
    PORT
      LAYER M4 ;
        RECT  86.358 8.352 86.442 8.376 ;
    END
  END i_pkt[306]
  PIN i_pkt[307]
    DIRECTION INPUT ;
    USE SIGNAL ;
    PORT
      LAYER M4 ;
        RECT  86.358 8.448 86.442 8.472 ;
    END
  END i_pkt[307]
  PIN i_pkt[308]
    DIRECTION INPUT ;
    USE SIGNAL ;
    PORT
      LAYER M4 ;
        RECT  86.358 8.544 86.442 8.568 ;
    END
  END i_pkt[308]
  PIN i_pkt[309]
    DIRECTION INPUT ;
    USE SIGNAL ;
    PORT
      LAYER M4 ;
        RECT  86.358 8.64 86.442 8.664 ;
    END
  END i_pkt[309]
  PIN i_pkt[30]
    DIRECTION INPUT ;
    USE SIGNAL ;
    PORT
      LAYER M4 ;
        RECT  86.358 98.88 86.442 98.904 ;
    END
  END i_pkt[30]
  PIN i_pkt[310]
    DIRECTION INPUT ;
    USE SIGNAL ;
    PORT
      LAYER M4 ;
        RECT  86.358 8.736 86.442 8.76 ;
    END
  END i_pkt[310]
  PIN i_pkt[311]
    DIRECTION INPUT ;
    USE SIGNAL ;
    PORT
      LAYER M4 ;
        RECT  86.358 8.832 86.442 8.856 ;
    END
  END i_pkt[311]
  PIN i_pkt[312]
    DIRECTION INPUT ;
    USE SIGNAL ;
    PORT
      LAYER M4 ;
        RECT  86.358 8.928 86.442 8.952 ;
    END
  END i_pkt[312]
  PIN i_pkt[313]
    DIRECTION INPUT ;
    USE SIGNAL ;
    PORT
      LAYER M4 ;
        RECT  86.358 9.024 86.442 9.048 ;
    END
  END i_pkt[313]
  PIN i_pkt[314]
    DIRECTION INPUT ;
    USE SIGNAL ;
    PORT
      LAYER M4 ;
        RECT  86.358 9.12 86.442 9.144 ;
    END
  END i_pkt[314]
  PIN i_pkt[315]
    DIRECTION INPUT ;
    USE SIGNAL ;
    PORT
      LAYER M4 ;
        RECT  86.358 9.216 86.442 9.24 ;
    END
  END i_pkt[315]
  PIN i_pkt[316]
    DIRECTION INPUT ;
    USE SIGNAL ;
    PORT
      LAYER M4 ;
        RECT  86.358 9.312 86.442 9.336 ;
    END
  END i_pkt[316]
  PIN i_pkt[317]
    DIRECTION INPUT ;
    USE SIGNAL ;
    PORT
      LAYER M4 ;
        RECT  86.358 9.408 86.442 9.432 ;
    END
  END i_pkt[317]
  PIN i_pkt[318]
    DIRECTION INPUT ;
    USE SIGNAL ;
    PORT
      LAYER M4 ;
        RECT  86.358 9.504 86.442 9.528 ;
    END
  END i_pkt[318]
  PIN i_pkt[319]
    DIRECTION INPUT ;
    USE SIGNAL ;
    PORT
      LAYER M4 ;
        RECT  86.358 9.6 86.442 9.624 ;
    END
  END i_pkt[319]
  PIN i_pkt[31]
    DIRECTION INPUT ;
    USE SIGNAL ;
    PORT
      LAYER M4 ;
        RECT  86.358 98.976 86.442 99 ;
    END
  END i_pkt[31]
  PIN i_pkt[320]
    DIRECTION INPUT ;
    USE SIGNAL ;
    PORT
      LAYER M4 ;
        RECT  86.358 9.696 86.442 9.72 ;
    END
  END i_pkt[320]
  PIN i_pkt[321]
    DIRECTION INPUT ;
    USE SIGNAL ;
    PORT
      LAYER M4 ;
        RECT  86.358 9.792 86.442 9.816 ;
    END
  END i_pkt[321]
  PIN i_pkt[322]
    DIRECTION INPUT ;
    USE SIGNAL ;
    PORT
      LAYER M4 ;
        RECT  86.358 9.888 86.442 9.912 ;
    END
  END i_pkt[322]
  PIN i_pkt[323]
    DIRECTION INPUT ;
    USE SIGNAL ;
    PORT
      LAYER M4 ;
        RECT  86.358 9.984 86.442 10.008 ;
    END
  END i_pkt[323]
  PIN i_pkt[324]
    DIRECTION INPUT ;
    USE SIGNAL ;
    PORT
      LAYER M4 ;
        RECT  86.358 10.08 86.442 10.104 ;
    END
  END i_pkt[324]
  PIN i_pkt[325]
    DIRECTION INPUT ;
    USE SIGNAL ;
    PORT
      LAYER M4 ;
        RECT  86.358 10.176 86.442 10.2 ;
    END
  END i_pkt[325]
  PIN i_pkt[326]
    DIRECTION INPUT ;
    USE SIGNAL ;
    PORT
      LAYER M4 ;
        RECT  86.358 10.272 86.442 10.296 ;
    END
  END i_pkt[326]
  PIN i_pkt[327]
    DIRECTION INPUT ;
    USE SIGNAL ;
    PORT
      LAYER M4 ;
        RECT  86.358 10.368 86.442 10.392 ;
    END
  END i_pkt[327]
  PIN i_pkt[328]
    DIRECTION INPUT ;
    USE SIGNAL ;
    PORT
      LAYER M4 ;
        RECT  86.358 10.464 86.442 10.488 ;
    END
  END i_pkt[328]
  PIN i_pkt[329]
    DIRECTION INPUT ;
    USE SIGNAL ;
    PORT
      LAYER M4 ;
        RECT  86.358 10.56 86.442 10.584 ;
    END
  END i_pkt[329]
  PIN i_pkt[32]
    DIRECTION INPUT ;
    USE SIGNAL ;
    PORT
      LAYER M4 ;
        RECT  86.358 99.072 86.442 99.096 ;
    END
  END i_pkt[32]
  PIN i_pkt[330]
    DIRECTION INPUT ;
    USE SIGNAL ;
    PORT
      LAYER M4 ;
        RECT  86.358 10.656 86.442 10.68 ;
    END
  END i_pkt[330]
  PIN i_pkt[331]
    DIRECTION INPUT ;
    USE SIGNAL ;
    PORT
      LAYER M4 ;
        RECT  86.358 10.752 86.442 10.776 ;
    END
  END i_pkt[331]
  PIN i_pkt[332]
    DIRECTION INPUT ;
    USE SIGNAL ;
    PORT
      LAYER M4 ;
        RECT  86.358 10.848 86.442 10.872 ;
    END
  END i_pkt[332]
  PIN i_pkt[333]
    DIRECTION INPUT ;
    USE SIGNAL ;
    PORT
      LAYER M4 ;
        RECT  86.358 10.944 86.442 10.968 ;
    END
  END i_pkt[333]
  PIN i_pkt[334]
    DIRECTION INPUT ;
    USE SIGNAL ;
    PORT
      LAYER M4 ;
        RECT  86.358 11.04 86.442 11.064 ;
    END
  END i_pkt[334]
  PIN i_pkt[335]
    DIRECTION INPUT ;
    USE SIGNAL ;
    PORT
      LAYER M4 ;
        RECT  86.358 11.136 86.442 11.16 ;
    END
  END i_pkt[335]
  PIN i_pkt[336]
    DIRECTION INPUT ;
    USE SIGNAL ;
    PORT
      LAYER M4 ;
        RECT  86.358 11.232 86.442 11.256 ;
    END
  END i_pkt[336]
  PIN i_pkt[337]
    DIRECTION INPUT ;
    USE SIGNAL ;
    PORT
      LAYER M4 ;
        RECT  86.358 11.328 86.442 11.352 ;
    END
  END i_pkt[337]
  PIN i_pkt[338]
    DIRECTION INPUT ;
    USE SIGNAL ;
    PORT
      LAYER M4 ;
        RECT  86.358 11.424 86.442 11.448 ;
    END
  END i_pkt[338]
  PIN i_pkt[339]
    DIRECTION INPUT ;
    USE SIGNAL ;
    PORT
      LAYER M4 ;
        RECT  86.358 11.52 86.442 11.544 ;
    END
  END i_pkt[339]
  PIN i_pkt[33]
    DIRECTION INPUT ;
    USE SIGNAL ;
    PORT
      LAYER M4 ;
        RECT  86.358 99.168 86.442 99.192 ;
    END
  END i_pkt[33]
  PIN i_pkt[340]
    DIRECTION INPUT ;
    USE SIGNAL ;
    PORT
      LAYER M4 ;
        RECT  86.358 11.616 86.442 11.64 ;
    END
  END i_pkt[340]
  PIN i_pkt[341]
    DIRECTION INPUT ;
    USE SIGNAL ;
    PORT
      LAYER M4 ;
        RECT  86.358 11.712 86.442 11.736 ;
    END
  END i_pkt[341]
  PIN i_pkt[342]
    DIRECTION INPUT ;
    USE SIGNAL ;
    PORT
      LAYER M4 ;
        RECT  86.358 11.808 86.442 11.832 ;
    END
  END i_pkt[342]
  PIN i_pkt[343]
    DIRECTION INPUT ;
    USE SIGNAL ;
    PORT
      LAYER M4 ;
        RECT  86.358 11.904 86.442 11.928 ;
    END
  END i_pkt[343]
  PIN i_pkt[344]
    DIRECTION INPUT ;
    USE SIGNAL ;
    PORT
      LAYER M4 ;
        RECT  86.358 12 86.442 12.024 ;
    END
  END i_pkt[344]
  PIN i_pkt[345]
    DIRECTION INPUT ;
    USE SIGNAL ;
    PORT
      LAYER M4 ;
        RECT  86.358 12.096 86.442 12.12 ;
    END
  END i_pkt[345]
  PIN i_pkt[346]
    DIRECTION INPUT ;
    USE SIGNAL ;
    PORT
      LAYER M4 ;
        RECT  86.358 12.192 86.442 12.216 ;
    END
  END i_pkt[346]
  PIN i_pkt[347]
    DIRECTION INPUT ;
    USE SIGNAL ;
    PORT
      LAYER M4 ;
        RECT  86.358 12.288 86.442 12.312 ;
    END
  END i_pkt[347]
  PIN i_pkt[348]
    DIRECTION INPUT ;
    USE SIGNAL ;
    PORT
      LAYER M4 ;
        RECT  86.358 12.384 86.442 12.408 ;
    END
  END i_pkt[348]
  PIN i_pkt[349]
    DIRECTION INPUT ;
    USE SIGNAL ;
    PORT
      LAYER M4 ;
        RECT  86.358 12.48 86.442 12.504 ;
    END
  END i_pkt[349]
  PIN i_pkt[34]
    DIRECTION INPUT ;
    USE SIGNAL ;
    PORT
      LAYER M4 ;
        RECT  86.358 99.264 86.442 99.288 ;
    END
  END i_pkt[34]
  PIN i_pkt[350]
    DIRECTION INPUT ;
    USE SIGNAL ;
    PORT
      LAYER M4 ;
        RECT  86.358 12.576 86.442 12.6 ;
    END
  END i_pkt[350]
  PIN i_pkt[351]
    DIRECTION INPUT ;
    USE SIGNAL ;
    PORT
      LAYER M4 ;
        RECT  86.358 12.672 86.442 12.696 ;
    END
  END i_pkt[351]
  PIN i_pkt[352]
    DIRECTION INPUT ;
    USE SIGNAL ;
    PORT
      LAYER M4 ;
        RECT  86.358 12.768 86.442 12.792 ;
    END
  END i_pkt[352]
  PIN i_pkt[353]
    DIRECTION INPUT ;
    USE SIGNAL ;
    PORT
      LAYER M4 ;
        RECT  86.358 12.864 86.442 12.888 ;
    END
  END i_pkt[353]
  PIN i_pkt[354]
    DIRECTION INPUT ;
    USE SIGNAL ;
    PORT
      LAYER M4 ;
        RECT  86.358 12.96 86.442 12.984 ;
    END
  END i_pkt[354]
  PIN i_pkt[355]
    DIRECTION INPUT ;
    USE SIGNAL ;
    PORT
      LAYER M4 ;
        RECT  86.358 13.056 86.442 13.08 ;
    END
  END i_pkt[355]
  PIN i_pkt[356]
    DIRECTION INPUT ;
    USE SIGNAL ;
    PORT
      LAYER M4 ;
        RECT  86.358 13.152 86.442 13.176 ;
    END
  END i_pkt[356]
  PIN i_pkt[357]
    DIRECTION INPUT ;
    USE SIGNAL ;
    PORT
      LAYER M4 ;
        RECT  86.358 13.248 86.442 13.272 ;
    END
  END i_pkt[357]
  PIN i_pkt[358]
    DIRECTION INPUT ;
    USE SIGNAL ;
    PORT
      LAYER M4 ;
        RECT  86.358 13.344 86.442 13.368 ;
    END
  END i_pkt[358]
  PIN i_pkt[359]
    DIRECTION INPUT ;
    USE SIGNAL ;
    PORT
      LAYER M4 ;
        RECT  86.358 13.44 86.442 13.464 ;
    END
  END i_pkt[359]
  PIN i_pkt[35]
    DIRECTION INPUT ;
    USE SIGNAL ;
    PORT
      LAYER M4 ;
        RECT  86.358 99.36 86.442 99.384 ;
    END
  END i_pkt[35]
  PIN i_pkt[360]
    DIRECTION INPUT ;
    USE SIGNAL ;
    PORT
      LAYER M4 ;
        RECT  86.358 13.536 86.442 13.56 ;
    END
  END i_pkt[360]
  PIN i_pkt[361]
    DIRECTION INPUT ;
    USE SIGNAL ;
    PORT
      LAYER M4 ;
        RECT  86.358 13.632 86.442 13.656 ;
    END
  END i_pkt[361]
  PIN i_pkt[362]
    DIRECTION INPUT ;
    USE SIGNAL ;
    PORT
      LAYER M4 ;
        RECT  86.358 13.728 86.442 13.752 ;
    END
  END i_pkt[362]
  PIN i_pkt[363]
    DIRECTION INPUT ;
    USE SIGNAL ;
    PORT
      LAYER M4 ;
        RECT  86.358 13.824 86.442 13.848 ;
    END
  END i_pkt[363]
  PIN i_pkt[364]
    DIRECTION INPUT ;
    USE SIGNAL ;
    PORT
      LAYER M4 ;
        RECT  86.358 13.92 86.442 13.944 ;
    END
  END i_pkt[364]
  PIN i_pkt[365]
    DIRECTION INPUT ;
    USE SIGNAL ;
    PORT
      LAYER M4 ;
        RECT  86.358 14.016 86.442 14.04 ;
    END
  END i_pkt[365]
  PIN i_pkt[366]
    DIRECTION INPUT ;
    USE SIGNAL ;
    PORT
      LAYER M4 ;
        RECT  86.358 14.112 86.442 14.136 ;
    END
  END i_pkt[366]
  PIN i_pkt[367]
    DIRECTION INPUT ;
    USE SIGNAL ;
    PORT
      LAYER M4 ;
        RECT  86.358 14.208 86.442 14.232 ;
    END
  END i_pkt[367]
  PIN i_pkt[368]
    DIRECTION INPUT ;
    USE SIGNAL ;
    PORT
      LAYER M4 ;
        RECT  86.358 14.304 86.442 14.328 ;
    END
  END i_pkt[368]
  PIN i_pkt[369]
    DIRECTION INPUT ;
    USE SIGNAL ;
    PORT
      LAYER M4 ;
        RECT  86.358 14.4 86.442 14.424 ;
    END
  END i_pkt[369]
  PIN i_pkt[36]
    DIRECTION INPUT ;
    USE SIGNAL ;
    PORT
      LAYER M4 ;
        RECT  86.358 99.456 86.442 99.48 ;
    END
  END i_pkt[36]
  PIN i_pkt[370]
    DIRECTION INPUT ;
    USE SIGNAL ;
    PORT
      LAYER M4 ;
        RECT  86.358 14.496 86.442 14.52 ;
    END
  END i_pkt[370]
  PIN i_pkt[371]
    DIRECTION INPUT ;
    USE SIGNAL ;
    PORT
      LAYER M4 ;
        RECT  86.358 14.592 86.442 14.616 ;
    END
  END i_pkt[371]
  PIN i_pkt[372]
    DIRECTION INPUT ;
    USE SIGNAL ;
    PORT
      LAYER M4 ;
        RECT  86.358 14.688 86.442 14.712 ;
    END
  END i_pkt[372]
  PIN i_pkt[373]
    DIRECTION INPUT ;
    USE SIGNAL ;
    PORT
      LAYER M4 ;
        RECT  86.358 14.784 86.442 14.808 ;
    END
  END i_pkt[373]
  PIN i_pkt[374]
    DIRECTION INPUT ;
    USE SIGNAL ;
    PORT
      LAYER M4 ;
        RECT  86.358 14.88 86.442 14.904 ;
    END
  END i_pkt[374]
  PIN i_pkt[375]
    DIRECTION INPUT ;
    USE SIGNAL ;
    PORT
      LAYER M4 ;
        RECT  86.358 14.976 86.442 15 ;
    END
  END i_pkt[375]
  PIN i_pkt[376]
    DIRECTION INPUT ;
    USE SIGNAL ;
    PORT
      LAYER M4 ;
        RECT  86.358 15.072 86.442 15.096 ;
    END
  END i_pkt[376]
  PIN i_pkt[377]
    DIRECTION INPUT ;
    USE SIGNAL ;
    PORT
      LAYER M4 ;
        RECT  86.358 15.168 86.442 15.192 ;
    END
  END i_pkt[377]
  PIN i_pkt[378]
    DIRECTION INPUT ;
    USE SIGNAL ;
    PORT
      LAYER M4 ;
        RECT  86.358 15.264 86.442 15.288 ;
    END
  END i_pkt[378]
  PIN i_pkt[379]
    DIRECTION INPUT ;
    USE SIGNAL ;
    PORT
      LAYER M4 ;
        RECT  86.358 15.36 86.442 15.384 ;
    END
  END i_pkt[379]
  PIN i_pkt[37]
    DIRECTION INPUT ;
    USE SIGNAL ;
    PORT
      LAYER M4 ;
        RECT  86.358 99.552 86.442 99.576 ;
    END
  END i_pkt[37]
  PIN i_pkt[380]
    DIRECTION INPUT ;
    USE SIGNAL ;
    PORT
      LAYER M4 ;
        RECT  86.358 15.456 86.442 15.48 ;
    END
  END i_pkt[380]
  PIN i_pkt[381]
    DIRECTION INPUT ;
    USE SIGNAL ;
    PORT
      LAYER M4 ;
        RECT  86.358 15.552 86.442 15.576 ;
    END
  END i_pkt[381]
  PIN i_pkt[382]
    DIRECTION INPUT ;
    USE SIGNAL ;
    PORT
      LAYER M4 ;
        RECT  86.358 15.648 86.442 15.672 ;
    END
  END i_pkt[382]
  PIN i_pkt[383]
    DIRECTION INPUT ;
    USE SIGNAL ;
    PORT
      LAYER M4 ;
        RECT  86.358 15.744 86.442 15.768 ;
    END
  END i_pkt[383]
  PIN i_pkt[384]
    DIRECTION INPUT ;
    USE SIGNAL ;
    PORT
      LAYER M4 ;
        RECT  86.358 15.84 86.442 15.864 ;
    END
  END i_pkt[384]
  PIN i_pkt[385]
    DIRECTION INPUT ;
    USE SIGNAL ;
    PORT
      LAYER M4 ;
        RECT  86.358 15.936 86.442 15.96 ;
    END
  END i_pkt[385]
  PIN i_pkt[386]
    DIRECTION INPUT ;
    USE SIGNAL ;
    PORT
      LAYER M4 ;
        RECT  86.358 16.032 86.442 16.056 ;
    END
  END i_pkt[386]
  PIN i_pkt[387]
    DIRECTION INPUT ;
    USE SIGNAL ;
    PORT
      LAYER M4 ;
        RECT  86.358 16.128 86.442 16.152 ;
    END
  END i_pkt[387]
  PIN i_pkt[388]
    DIRECTION INPUT ;
    USE SIGNAL ;
    PORT
      LAYER M4 ;
        RECT  86.358 16.224 86.442 16.248 ;
    END
  END i_pkt[388]
  PIN i_pkt[389]
    DIRECTION INPUT ;
    USE SIGNAL ;
    PORT
      LAYER M4 ;
        RECT  86.358 16.32 86.442 16.344 ;
    END
  END i_pkt[389]
  PIN i_pkt[38]
    DIRECTION INPUT ;
    USE SIGNAL ;
    PORT
      LAYER M4 ;
        RECT  86.358 99.648 86.442 99.672 ;
    END
  END i_pkt[38]
  PIN i_pkt[390]
    DIRECTION INPUT ;
    USE SIGNAL ;
    PORT
      LAYER M4 ;
        RECT  86.358 16.416 86.442 16.44 ;
    END
  END i_pkt[390]
  PIN i_pkt[391]
    DIRECTION INPUT ;
    USE SIGNAL ;
    PORT
      LAYER M4 ;
        RECT  86.358 16.512 86.442 16.536 ;
    END
  END i_pkt[391]
  PIN i_pkt[392]
    DIRECTION INPUT ;
    USE SIGNAL ;
    PORT
      LAYER M4 ;
        RECT  86.358 16.608 86.442 16.632 ;
    END
  END i_pkt[392]
  PIN i_pkt[393]
    DIRECTION INPUT ;
    USE SIGNAL ;
    PORT
      LAYER M4 ;
        RECT  86.358 16.704 86.442 16.728 ;
    END
  END i_pkt[393]
  PIN i_pkt[394]
    DIRECTION INPUT ;
    USE SIGNAL ;
    PORT
      LAYER M4 ;
        RECT  86.358 16.8 86.442 16.824 ;
    END
  END i_pkt[394]
  PIN i_pkt[395]
    DIRECTION INPUT ;
    USE SIGNAL ;
    PORT
      LAYER M4 ;
        RECT  86.358 16.896 86.442 16.92 ;
    END
  END i_pkt[395]
  PIN i_pkt[396]
    DIRECTION INPUT ;
    USE SIGNAL ;
    PORT
      LAYER M4 ;
        RECT  86.358 16.992 86.442 17.016 ;
    END
  END i_pkt[396]
  PIN i_pkt[397]
    DIRECTION INPUT ;
    USE SIGNAL ;
    PORT
      LAYER M4 ;
        RECT  86.358 17.088 86.442 17.112 ;
    END
  END i_pkt[397]
  PIN i_pkt[398]
    DIRECTION INPUT ;
    USE SIGNAL ;
    PORT
      LAYER M4 ;
        RECT  86.358 17.184 86.442 17.208 ;
    END
  END i_pkt[398]
  PIN i_pkt[399]
    DIRECTION INPUT ;
    USE SIGNAL ;
    PORT
      LAYER M4 ;
        RECT  86.358 17.28 86.442 17.304 ;
    END
  END i_pkt[399]
  PIN i_pkt[39]
    DIRECTION INPUT ;
    USE SIGNAL ;
    PORT
      LAYER M4 ;
        RECT  86.358 99.744 86.442 99.768 ;
    END
  END i_pkt[39]
  PIN i_pkt[3]
    DIRECTION INPUT ;
    USE SIGNAL ;
    PORT
      LAYER M4 ;
        RECT  86.358 96.288 86.442 96.312 ;
    END
  END i_pkt[3]
  PIN i_pkt[400]
    DIRECTION INPUT ;
    USE SIGNAL ;
    PORT
      LAYER M4 ;
        RECT  86.358 17.376 86.442 17.4 ;
    END
  END i_pkt[400]
  PIN i_pkt[401]
    DIRECTION INPUT ;
    USE SIGNAL ;
    PORT
      LAYER M4 ;
        RECT  86.358 17.472 86.442 17.496 ;
    END
  END i_pkt[401]
  PIN i_pkt[402]
    DIRECTION INPUT ;
    USE SIGNAL ;
    PORT
      LAYER M4 ;
        RECT  86.358 17.568 86.442 17.592 ;
    END
  END i_pkt[402]
  PIN i_pkt[403]
    DIRECTION INPUT ;
    USE SIGNAL ;
    PORT
      LAYER M4 ;
        RECT  86.358 17.664 86.442 17.688 ;
    END
  END i_pkt[403]
  PIN i_pkt[404]
    DIRECTION INPUT ;
    USE SIGNAL ;
    PORT
      LAYER M4 ;
        RECT  86.358 17.76 86.442 17.784 ;
    END
  END i_pkt[404]
  PIN i_pkt[405]
    DIRECTION INPUT ;
    USE SIGNAL ;
    PORT
      LAYER M4 ;
        RECT  86.358 17.856 86.442 17.88 ;
    END
  END i_pkt[405]
  PIN i_pkt[406]
    DIRECTION INPUT ;
    USE SIGNAL ;
    PORT
      LAYER M4 ;
        RECT  86.358 17.952 86.442 17.976 ;
    END
  END i_pkt[406]
  PIN i_pkt[407]
    DIRECTION INPUT ;
    USE SIGNAL ;
    PORT
      LAYER M4 ;
        RECT  86.358 18.048 86.442 18.072 ;
    END
  END i_pkt[407]
  PIN i_pkt[408]
    DIRECTION INPUT ;
    USE SIGNAL ;
    PORT
      LAYER M4 ;
        RECT  86.358 18.144 86.442 18.168 ;
    END
  END i_pkt[408]
  PIN i_pkt[409]
    DIRECTION INPUT ;
    USE SIGNAL ;
    PORT
      LAYER M4 ;
        RECT  86.358 18.24 86.442 18.264 ;
    END
  END i_pkt[409]
  PIN i_pkt[40]
    DIRECTION INPUT ;
    USE SIGNAL ;
    PORT
      LAYER M4 ;
        RECT  86.358 99.84 86.442 99.864 ;
    END
  END i_pkt[40]
  PIN i_pkt[410]
    DIRECTION INPUT ;
    USE SIGNAL ;
    PORT
      LAYER M4 ;
        RECT  86.358 18.336 86.442 18.36 ;
    END
  END i_pkt[410]
  PIN i_pkt[411]
    DIRECTION INPUT ;
    USE SIGNAL ;
    PORT
      LAYER M4 ;
        RECT  86.358 18.432 86.442 18.456 ;
    END
  END i_pkt[411]
  PIN i_pkt[412]
    DIRECTION INPUT ;
    USE SIGNAL ;
    PORT
      LAYER M4 ;
        RECT  86.358 18.528 86.442 18.552 ;
    END
  END i_pkt[412]
  PIN i_pkt[413]
    DIRECTION INPUT ;
    USE SIGNAL ;
    PORT
      LAYER M4 ;
        RECT  86.358 18.624 86.442 18.648 ;
    END
  END i_pkt[413]
  PIN i_pkt[414]
    DIRECTION INPUT ;
    USE SIGNAL ;
    PORT
      LAYER M4 ;
        RECT  86.358 18.72 86.442 18.744 ;
    END
  END i_pkt[414]
  PIN i_pkt[415]
    DIRECTION INPUT ;
    USE SIGNAL ;
    PORT
      LAYER M4 ;
        RECT  86.358 18.816 86.442 18.84 ;
    END
  END i_pkt[415]
  PIN i_pkt[416]
    DIRECTION INPUT ;
    USE SIGNAL ;
    PORT
      LAYER M4 ;
        RECT  86.358 18.912 86.442 18.936 ;
    END
  END i_pkt[416]
  PIN i_pkt[417]
    DIRECTION INPUT ;
    USE SIGNAL ;
    PORT
      LAYER M4 ;
        RECT  86.358 19.008 86.442 19.032 ;
    END
  END i_pkt[417]
  PIN i_pkt[418]
    DIRECTION INPUT ;
    USE SIGNAL ;
    PORT
      LAYER M4 ;
        RECT  86.358 19.104 86.442 19.128 ;
    END
  END i_pkt[418]
  PIN i_pkt[419]
    DIRECTION INPUT ;
    USE SIGNAL ;
    PORT
      LAYER M4 ;
        RECT  86.358 19.2 86.442 19.224 ;
    END
  END i_pkt[419]
  PIN i_pkt[41]
    DIRECTION INPUT ;
    USE SIGNAL ;
    PORT
      LAYER M4 ;
        RECT  86.358 99.936 86.442 99.96 ;
    END
  END i_pkt[41]
  PIN i_pkt[420]
    DIRECTION INPUT ;
    USE SIGNAL ;
    PORT
      LAYER M4 ;
        RECT  86.358 19.296 86.442 19.32 ;
    END
  END i_pkt[420]
  PIN i_pkt[421]
    DIRECTION INPUT ;
    USE SIGNAL ;
    PORT
      LAYER M4 ;
        RECT  86.358 19.392 86.442 19.416 ;
    END
  END i_pkt[421]
  PIN i_pkt[422]
    DIRECTION INPUT ;
    USE SIGNAL ;
    PORT
      LAYER M4 ;
        RECT  86.358 19.488 86.442 19.512 ;
    END
  END i_pkt[422]
  PIN i_pkt[423]
    DIRECTION INPUT ;
    USE SIGNAL ;
    PORT
      LAYER M4 ;
        RECT  86.358 19.584 86.442 19.608 ;
    END
  END i_pkt[423]
  PIN i_pkt[424]
    DIRECTION INPUT ;
    USE SIGNAL ;
    PORT
      LAYER M4 ;
        RECT  86.358 19.68 86.442 19.704 ;
    END
  END i_pkt[424]
  PIN i_pkt[425]
    DIRECTION INPUT ;
    USE SIGNAL ;
    PORT
      LAYER M4 ;
        RECT  86.358 19.776 86.442 19.8 ;
    END
  END i_pkt[425]
  PIN i_pkt[426]
    DIRECTION INPUT ;
    USE SIGNAL ;
    PORT
      LAYER M4 ;
        RECT  86.358 19.872 86.442 19.896 ;
    END
  END i_pkt[426]
  PIN i_pkt[427]
    DIRECTION INPUT ;
    USE SIGNAL ;
    PORT
      LAYER M4 ;
        RECT  86.358 19.968 86.442 19.992 ;
    END
  END i_pkt[427]
  PIN i_pkt[428]
    DIRECTION INPUT ;
    USE SIGNAL ;
    PORT
      LAYER M4 ;
        RECT  86.358 20.064 86.442 20.088 ;
    END
  END i_pkt[428]
  PIN i_pkt[429]
    DIRECTION INPUT ;
    USE SIGNAL ;
    PORT
      LAYER M4 ;
        RECT  86.358 20.16 86.442 20.184 ;
    END
  END i_pkt[429]
  PIN i_pkt[42]
    DIRECTION INPUT ;
    USE SIGNAL ;
    PORT
      LAYER M4 ;
        RECT  86.358 100.032 86.442 100.056 ;
    END
  END i_pkt[42]
  PIN i_pkt[430]
    DIRECTION INPUT ;
    USE SIGNAL ;
    PORT
      LAYER M4 ;
        RECT  86.358 20.256 86.442 20.28 ;
    END
  END i_pkt[430]
  PIN i_pkt[431]
    DIRECTION INPUT ;
    USE SIGNAL ;
    PORT
      LAYER M4 ;
        RECT  86.358 20.352 86.442 20.376 ;
    END
  END i_pkt[431]
  PIN i_pkt[432]
    DIRECTION INPUT ;
    USE SIGNAL ;
    PORT
      LAYER M4 ;
        RECT  86.358 20.448 86.442 20.472 ;
    END
  END i_pkt[432]
  PIN i_pkt[433]
    DIRECTION INPUT ;
    USE SIGNAL ;
    PORT
      LAYER M4 ;
        RECT  86.358 20.544 86.442 20.568 ;
    END
  END i_pkt[433]
  PIN i_pkt[434]
    DIRECTION INPUT ;
    USE SIGNAL ;
    PORT
      LAYER M4 ;
        RECT  86.358 20.64 86.442 20.664 ;
    END
  END i_pkt[434]
  PIN i_pkt[435]
    DIRECTION INPUT ;
    USE SIGNAL ;
    PORT
      LAYER M4 ;
        RECT  86.358 20.736 86.442 20.76 ;
    END
  END i_pkt[435]
  PIN i_pkt[436]
    DIRECTION INPUT ;
    USE SIGNAL ;
    PORT
      LAYER M4 ;
        RECT  86.358 20.832 86.442 20.856 ;
    END
  END i_pkt[436]
  PIN i_pkt[437]
    DIRECTION INPUT ;
    USE SIGNAL ;
    PORT
      LAYER M4 ;
        RECT  86.358 20.928 86.442 20.952 ;
    END
  END i_pkt[437]
  PIN i_pkt[438]
    DIRECTION INPUT ;
    USE SIGNAL ;
    PORT
      LAYER M4 ;
        RECT  86.358 21.024 86.442 21.048 ;
    END
  END i_pkt[438]
  PIN i_pkt[439]
    DIRECTION INPUT ;
    USE SIGNAL ;
    PORT
      LAYER M4 ;
        RECT  86.358 21.12 86.442 21.144 ;
    END
  END i_pkt[439]
  PIN i_pkt[43]
    DIRECTION INPUT ;
    USE SIGNAL ;
    PORT
      LAYER M4 ;
        RECT  86.358 100.128 86.442 100.152 ;
    END
  END i_pkt[43]
  PIN i_pkt[440]
    DIRECTION INPUT ;
    USE SIGNAL ;
    PORT
      LAYER M4 ;
        RECT  86.358 21.216 86.442 21.24 ;
    END
  END i_pkt[440]
  PIN i_pkt[441]
    DIRECTION INPUT ;
    USE SIGNAL ;
    PORT
      LAYER M4 ;
        RECT  86.358 21.312 86.442 21.336 ;
    END
  END i_pkt[441]
  PIN i_pkt[442]
    DIRECTION INPUT ;
    USE SIGNAL ;
    PORT
      LAYER M4 ;
        RECT  86.358 21.408 86.442 21.432 ;
    END
  END i_pkt[442]
  PIN i_pkt[443]
    DIRECTION INPUT ;
    USE SIGNAL ;
    PORT
      LAYER M4 ;
        RECT  86.358 21.504 86.442 21.528 ;
    END
  END i_pkt[443]
  PIN i_pkt[444]
    DIRECTION INPUT ;
    USE SIGNAL ;
    PORT
      LAYER M4 ;
        RECT  86.358 21.6 86.442 21.624 ;
    END
  END i_pkt[444]
  PIN i_pkt[445]
    DIRECTION INPUT ;
    USE SIGNAL ;
    PORT
      LAYER M4 ;
        RECT  86.358 21.696 86.442 21.72 ;
    END
  END i_pkt[445]
  PIN i_pkt[446]
    DIRECTION INPUT ;
    USE SIGNAL ;
    PORT
      LAYER M4 ;
        RECT  86.358 21.792 86.442 21.816 ;
    END
  END i_pkt[446]
  PIN i_pkt[447]
    DIRECTION INPUT ;
    USE SIGNAL ;
    PORT
      LAYER M4 ;
        RECT  86.358 21.888 86.442 21.912 ;
    END
  END i_pkt[447]
  PIN i_pkt[448]
    DIRECTION INPUT ;
    USE SIGNAL ;
    PORT
      LAYER M4 ;
        RECT  86.358 21.984 86.442 22.008 ;
    END
  END i_pkt[448]
  PIN i_pkt[449]
    DIRECTION INPUT ;
    USE SIGNAL ;
    PORT
      LAYER M4 ;
        RECT  86.358 22.08 86.442 22.104 ;
    END
  END i_pkt[449]
  PIN i_pkt[44]
    DIRECTION INPUT ;
    USE SIGNAL ;
    PORT
      LAYER M4 ;
        RECT  86.358 100.224 86.442 100.248 ;
    END
  END i_pkt[44]
  PIN i_pkt[450]
    DIRECTION INPUT ;
    USE SIGNAL ;
    PORT
      LAYER M4 ;
        RECT  86.358 22.176 86.442 22.2 ;
    END
  END i_pkt[450]
  PIN i_pkt[451]
    DIRECTION INPUT ;
    USE SIGNAL ;
    PORT
      LAYER M4 ;
        RECT  86.358 22.272 86.442 22.296 ;
    END
  END i_pkt[451]
  PIN i_pkt[452]
    DIRECTION INPUT ;
    USE SIGNAL ;
    PORT
      LAYER M4 ;
        RECT  86.358 22.368 86.442 22.392 ;
    END
  END i_pkt[452]
  PIN i_pkt[453]
    DIRECTION INPUT ;
    USE SIGNAL ;
    PORT
      LAYER M4 ;
        RECT  86.358 22.464 86.442 22.488 ;
    END
  END i_pkt[453]
  PIN i_pkt[454]
    DIRECTION INPUT ;
    USE SIGNAL ;
    PORT
      LAYER M4 ;
        RECT  86.358 22.56 86.442 22.584 ;
    END
  END i_pkt[454]
  PIN i_pkt[455]
    DIRECTION INPUT ;
    USE SIGNAL ;
    PORT
      LAYER M4 ;
        RECT  86.358 22.656 86.442 22.68 ;
    END
  END i_pkt[455]
  PIN i_pkt[456]
    DIRECTION INPUT ;
    USE SIGNAL ;
    PORT
      LAYER M4 ;
        RECT  86.358 22.752 86.442 22.776 ;
    END
  END i_pkt[456]
  PIN i_pkt[457]
    DIRECTION INPUT ;
    USE SIGNAL ;
    PORT
      LAYER M4 ;
        RECT  86.358 22.848 86.442 22.872 ;
    END
  END i_pkt[457]
  PIN i_pkt[458]
    DIRECTION INPUT ;
    USE SIGNAL ;
    PORT
      LAYER M4 ;
        RECT  86.358 22.944 86.442 22.968 ;
    END
  END i_pkt[458]
  PIN i_pkt[459]
    DIRECTION INPUT ;
    USE SIGNAL ;
    PORT
      LAYER M4 ;
        RECT  86.358 23.04 86.442 23.064 ;
    END
  END i_pkt[459]
  PIN i_pkt[45]
    DIRECTION INPUT ;
    USE SIGNAL ;
    PORT
      LAYER M4 ;
        RECT  86.358 100.32 86.442 100.344 ;
    END
  END i_pkt[45]
  PIN i_pkt[460]
    DIRECTION INPUT ;
    USE SIGNAL ;
    PORT
      LAYER M4 ;
        RECT  86.358 23.136 86.442 23.16 ;
    END
  END i_pkt[460]
  PIN i_pkt[461]
    DIRECTION INPUT ;
    USE SIGNAL ;
    PORT
      LAYER M4 ;
        RECT  86.358 23.232 86.442 23.256 ;
    END
  END i_pkt[461]
  PIN i_pkt[462]
    DIRECTION INPUT ;
    USE SIGNAL ;
    PORT
      LAYER M4 ;
        RECT  86.358 23.328 86.442 23.352 ;
    END
  END i_pkt[462]
  PIN i_pkt[463]
    DIRECTION INPUT ;
    USE SIGNAL ;
    PORT
      LAYER M4 ;
        RECT  86.358 23.424 86.442 23.448 ;
    END
  END i_pkt[463]
  PIN i_pkt[464]
    DIRECTION INPUT ;
    USE SIGNAL ;
    PORT
      LAYER M4 ;
        RECT  86.358 23.52 86.442 23.544 ;
    END
  END i_pkt[464]
  PIN i_pkt[465]
    DIRECTION INPUT ;
    USE SIGNAL ;
    PORT
      LAYER M4 ;
        RECT  86.358 23.616 86.442 23.64 ;
    END
  END i_pkt[465]
  PIN i_pkt[466]
    DIRECTION INPUT ;
    USE SIGNAL ;
    PORT
      LAYER M4 ;
        RECT  86.358 23.712 86.442 23.736 ;
    END
  END i_pkt[466]
  PIN i_pkt[467]
    DIRECTION INPUT ;
    USE SIGNAL ;
    PORT
      LAYER M4 ;
        RECT  86.358 23.808 86.442 23.832 ;
    END
  END i_pkt[467]
  PIN i_pkt[468]
    DIRECTION INPUT ;
    USE SIGNAL ;
    PORT
      LAYER M4 ;
        RECT  86.358 23.904 86.442 23.928 ;
    END
  END i_pkt[468]
  PIN i_pkt[469]
    DIRECTION INPUT ;
    USE SIGNAL ;
    PORT
      LAYER M4 ;
        RECT  86.358 24 86.442 24.024 ;
    END
  END i_pkt[469]
  PIN i_pkt[46]
    DIRECTION INPUT ;
    USE SIGNAL ;
    PORT
      LAYER M4 ;
        RECT  86.358 100.416 86.442 100.44 ;
    END
  END i_pkt[46]
  PIN i_pkt[470]
    DIRECTION INPUT ;
    USE SIGNAL ;
    PORT
      LAYER M4 ;
        RECT  86.358 24.096 86.442 24.12 ;
    END
  END i_pkt[470]
  PIN i_pkt[471]
    DIRECTION INPUT ;
    USE SIGNAL ;
    PORT
      LAYER M4 ;
        RECT  86.358 24.192 86.442 24.216 ;
    END
  END i_pkt[471]
  PIN i_pkt[472]
    DIRECTION INPUT ;
    USE SIGNAL ;
    PORT
      LAYER M4 ;
        RECT  86.358 24.288 86.442 24.312 ;
    END
  END i_pkt[472]
  PIN i_pkt[473]
    DIRECTION INPUT ;
    USE SIGNAL ;
    PORT
      LAYER M4 ;
        RECT  86.358 24.384 86.442 24.408 ;
    END
  END i_pkt[473]
  PIN i_pkt[474]
    DIRECTION INPUT ;
    USE SIGNAL ;
    PORT
      LAYER M4 ;
        RECT  86.358 24.48 86.442 24.504 ;
    END
  END i_pkt[474]
  PIN i_pkt[475]
    DIRECTION INPUT ;
    USE SIGNAL ;
    PORT
      LAYER M4 ;
        RECT  86.358 24.576 86.442 24.6 ;
    END
  END i_pkt[475]
  PIN i_pkt[476]
    DIRECTION INPUT ;
    USE SIGNAL ;
    PORT
      LAYER M4 ;
        RECT  86.358 24.672 86.442 24.696 ;
    END
  END i_pkt[476]
  PIN i_pkt[477]
    DIRECTION INPUT ;
    USE SIGNAL ;
    PORT
      LAYER M4 ;
        RECT  86.358 24.768 86.442 24.792 ;
    END
  END i_pkt[477]
  PIN i_pkt[478]
    DIRECTION INPUT ;
    USE SIGNAL ;
    PORT
      LAYER M4 ;
        RECT  86.358 24.864 86.442 24.888 ;
    END
  END i_pkt[478]
  PIN i_pkt[479]
    DIRECTION INPUT ;
    USE SIGNAL ;
    PORT
      LAYER M4 ;
        RECT  86.358 24.96 86.442 24.984 ;
    END
  END i_pkt[479]
  PIN i_pkt[47]
    DIRECTION INPUT ;
    USE SIGNAL ;
    PORT
      LAYER M4 ;
        RECT  86.358 100.512 86.442 100.536 ;
    END
  END i_pkt[47]
  PIN i_pkt[480]
    DIRECTION INPUT ;
    USE SIGNAL ;
    PORT
      LAYER M4 ;
        RECT  86.358 25.056 86.442 25.08 ;
    END
  END i_pkt[480]
  PIN i_pkt[481]
    DIRECTION INPUT ;
    USE SIGNAL ;
    PORT
      LAYER M4 ;
        RECT  86.358 25.152 86.442 25.176 ;
    END
  END i_pkt[481]
  PIN i_pkt[482]
    DIRECTION INPUT ;
    USE SIGNAL ;
    PORT
      LAYER M4 ;
        RECT  86.358 25.248 86.442 25.272 ;
    END
  END i_pkt[482]
  PIN i_pkt[483]
    DIRECTION INPUT ;
    USE SIGNAL ;
    PORT
      LAYER M4 ;
        RECT  86.358 25.344 86.442 25.368 ;
    END
  END i_pkt[483]
  PIN i_pkt[484]
    DIRECTION INPUT ;
    USE SIGNAL ;
    PORT
      LAYER M4 ;
        RECT  86.358 25.44 86.442 25.464 ;
    END
  END i_pkt[484]
  PIN i_pkt[485]
    DIRECTION INPUT ;
    USE SIGNAL ;
    PORT
      LAYER M4 ;
        RECT  86.358 25.536 86.442 25.56 ;
    END
  END i_pkt[485]
  PIN i_pkt[486]
    DIRECTION INPUT ;
    USE SIGNAL ;
    PORT
      LAYER M4 ;
        RECT  86.358 25.632 86.442 25.656 ;
    END
  END i_pkt[486]
  PIN i_pkt[487]
    DIRECTION INPUT ;
    USE SIGNAL ;
    PORT
      LAYER M4 ;
        RECT  86.358 25.728 86.442 25.752 ;
    END
  END i_pkt[487]
  PIN i_pkt[488]
    DIRECTION INPUT ;
    USE SIGNAL ;
    PORT
      LAYER M4 ;
        RECT  86.358 25.824 86.442 25.848 ;
    END
  END i_pkt[488]
  PIN i_pkt[489]
    DIRECTION INPUT ;
    USE SIGNAL ;
    PORT
      LAYER M4 ;
        RECT  86.358 25.92 86.442 25.944 ;
    END
  END i_pkt[489]
  PIN i_pkt[48]
    DIRECTION INPUT ;
    USE SIGNAL ;
    PORT
      LAYER M4 ;
        RECT  86.358 100.608 86.442 100.632 ;
    END
  END i_pkt[48]
  PIN i_pkt[490]
    DIRECTION INPUT ;
    USE SIGNAL ;
    PORT
      LAYER M4 ;
        RECT  86.358 26.016 86.442 26.04 ;
    END
  END i_pkt[490]
  PIN i_pkt[491]
    DIRECTION INPUT ;
    USE SIGNAL ;
    PORT
      LAYER M4 ;
        RECT  86.358 26.112 86.442 26.136 ;
    END
  END i_pkt[491]
  PIN i_pkt[492]
    DIRECTION INPUT ;
    USE SIGNAL ;
    PORT
      LAYER M4 ;
        RECT  86.358 26.208 86.442 26.232 ;
    END
  END i_pkt[492]
  PIN i_pkt[493]
    DIRECTION INPUT ;
    USE SIGNAL ;
    PORT
      LAYER M4 ;
        RECT  86.358 26.304 86.442 26.328 ;
    END
  END i_pkt[493]
  PIN i_pkt[494]
    DIRECTION INPUT ;
    USE SIGNAL ;
    PORT
      LAYER M4 ;
        RECT  86.358 26.4 86.442 26.424 ;
    END
  END i_pkt[494]
  PIN i_pkt[495]
    DIRECTION INPUT ;
    USE SIGNAL ;
    PORT
      LAYER M4 ;
        RECT  86.358 26.496 86.442 26.52 ;
    END
  END i_pkt[495]
  PIN i_pkt[496]
    DIRECTION INPUT ;
    USE SIGNAL ;
    PORT
      LAYER M4 ;
        RECT  86.358 26.592 86.442 26.616 ;
    END
  END i_pkt[496]
  PIN i_pkt[497]
    DIRECTION INPUT ;
    USE SIGNAL ;
    PORT
      LAYER M4 ;
        RECT  86.358 26.688 86.442 26.712 ;
    END
  END i_pkt[497]
  PIN i_pkt[498]
    DIRECTION INPUT ;
    USE SIGNAL ;
    PORT
      LAYER M4 ;
        RECT  86.358 26.784 86.442 26.808 ;
    END
  END i_pkt[498]
  PIN i_pkt[499]
    DIRECTION INPUT ;
    USE SIGNAL ;
    PORT
      LAYER M4 ;
        RECT  86.358 26.88 86.442 26.904 ;
    END
  END i_pkt[499]
  PIN i_pkt[49]
    DIRECTION INPUT ;
    USE SIGNAL ;
    PORT
      LAYER M4 ;
        RECT  86.358 100.704 86.442 100.728 ;
    END
  END i_pkt[49]
  PIN i_pkt[4]
    DIRECTION INPUT ;
    USE SIGNAL ;
    PORT
      LAYER M4 ;
        RECT  86.358 96.384 86.442 96.408 ;
    END
  END i_pkt[4]
  PIN i_pkt[500]
    DIRECTION INPUT ;
    USE SIGNAL ;
    PORT
      LAYER M4 ;
        RECT  86.358 26.976 86.442 27 ;
    END
  END i_pkt[500]
  PIN i_pkt[501]
    DIRECTION INPUT ;
    USE SIGNAL ;
    PORT
      LAYER M4 ;
        RECT  86.358 27.072 86.442 27.096 ;
    END
  END i_pkt[501]
  PIN i_pkt[502]
    DIRECTION INPUT ;
    USE SIGNAL ;
    PORT
      LAYER M4 ;
        RECT  86.358 27.168 86.442 27.192 ;
    END
  END i_pkt[502]
  PIN i_pkt[503]
    DIRECTION INPUT ;
    USE SIGNAL ;
    PORT
      LAYER M4 ;
        RECT  86.358 27.264 86.442 27.288 ;
    END
  END i_pkt[503]
  PIN i_pkt[504]
    DIRECTION INPUT ;
    USE SIGNAL ;
    PORT
      LAYER M4 ;
        RECT  86.358 27.36 86.442 27.384 ;
    END
  END i_pkt[504]
  PIN i_pkt[505]
    DIRECTION INPUT ;
    USE SIGNAL ;
    PORT
      LAYER M4 ;
        RECT  86.358 27.456 86.442 27.48 ;
    END
  END i_pkt[505]
  PIN i_pkt[506]
    DIRECTION INPUT ;
    USE SIGNAL ;
    PORT
      LAYER M4 ;
        RECT  86.358 27.552 86.442 27.576 ;
    END
  END i_pkt[506]
  PIN i_pkt[507]
    DIRECTION INPUT ;
    USE SIGNAL ;
    PORT
      LAYER M4 ;
        RECT  86.358 27.648 86.442 27.672 ;
    END
  END i_pkt[507]
  PIN i_pkt[508]
    DIRECTION INPUT ;
    USE SIGNAL ;
    PORT
      LAYER M4 ;
        RECT  86.358 27.744 86.442 27.768 ;
    END
  END i_pkt[508]
  PIN i_pkt[509]
    DIRECTION INPUT ;
    USE SIGNAL ;
    PORT
      LAYER M4 ;
        RECT  86.358 27.84 86.442 27.864 ;
    END
  END i_pkt[509]
  PIN i_pkt[50]
    DIRECTION INPUT ;
    USE SIGNAL ;
    PORT
      LAYER M4 ;
        RECT  86.358 100.8 86.442 100.824 ;
    END
  END i_pkt[50]
  PIN i_pkt[510]
    DIRECTION INPUT ;
    USE SIGNAL ;
    PORT
      LAYER M4 ;
        RECT  86.358 27.936 86.442 27.96 ;
    END
  END i_pkt[510]
  PIN i_pkt[511]
    DIRECTION INPUT ;
    USE SIGNAL ;
    PORT
      LAYER M4 ;
        RECT  86.358 28.032 86.442 28.056 ;
    END
  END i_pkt[511]
  PIN i_pkt[512]
    DIRECTION INPUT ;
    USE SIGNAL ;
    PORT
      LAYER M4 ;
        RECT  86.358 28.128 86.442 28.152 ;
    END
  END i_pkt[512]
  PIN i_pkt[513]
    DIRECTION INPUT ;
    USE SIGNAL ;
    PORT
      LAYER M4 ;
        RECT  86.358 28.224 86.442 28.248 ;
    END
  END i_pkt[513]
  PIN i_pkt[514]
    DIRECTION INPUT ;
    USE SIGNAL ;
    PORT
      LAYER M4 ;
        RECT  86.358 28.32 86.442 28.344 ;
    END
  END i_pkt[514]
  PIN i_pkt[515]
    DIRECTION INPUT ;
    USE SIGNAL ;
    PORT
      LAYER M4 ;
        RECT  86.358 28.416 86.442 28.44 ;
    END
  END i_pkt[515]
  PIN i_pkt[516]
    DIRECTION INPUT ;
    USE SIGNAL ;
    PORT
      LAYER M4 ;
        RECT  86.358 28.512 86.442 28.536 ;
    END
  END i_pkt[516]
  PIN i_pkt[517]
    DIRECTION INPUT ;
    USE SIGNAL ;
    PORT
      LAYER M4 ;
        RECT  86.358 28.608 86.442 28.632 ;
    END
  END i_pkt[517]
  PIN i_pkt[518]
    DIRECTION INPUT ;
    USE SIGNAL ;
    PORT
      LAYER M4 ;
        RECT  86.358 28.704 86.442 28.728 ;
    END
  END i_pkt[518]
  PIN i_pkt[519]
    DIRECTION INPUT ;
    USE SIGNAL ;
    PORT
      LAYER M4 ;
        RECT  86.358 28.8 86.442 28.824 ;
    END
  END i_pkt[519]
  PIN i_pkt[51]
    DIRECTION INPUT ;
    USE SIGNAL ;
    PORT
      LAYER M4 ;
        RECT  86.358 100.896 86.442 100.92 ;
    END
  END i_pkt[51]
  PIN i_pkt[520]
    DIRECTION INPUT ;
    USE SIGNAL ;
    PORT
      LAYER M4 ;
        RECT  86.358 28.896 86.442 28.92 ;
    END
  END i_pkt[520]
  PIN i_pkt[521]
    DIRECTION INPUT ;
    USE SIGNAL ;
    PORT
      LAYER M4 ;
        RECT  86.358 28.992 86.442 29.016 ;
    END
  END i_pkt[521]
  PIN i_pkt[522]
    DIRECTION INPUT ;
    USE SIGNAL ;
    PORT
      LAYER M4 ;
        RECT  86.358 29.088 86.442 29.112 ;
    END
  END i_pkt[522]
  PIN i_pkt[523]
    DIRECTION INPUT ;
    USE SIGNAL ;
    PORT
      LAYER M4 ;
        RECT  86.358 29.184 86.442 29.208 ;
    END
  END i_pkt[523]
  PIN i_pkt[524]
    DIRECTION INPUT ;
    USE SIGNAL ;
    PORT
      LAYER M4 ;
        RECT  86.358 29.28 86.442 29.304 ;
    END
  END i_pkt[524]
  PIN i_pkt[525]
    DIRECTION INPUT ;
    USE SIGNAL ;
    PORT
      LAYER M4 ;
        RECT  86.358 29.376 86.442 29.4 ;
    END
  END i_pkt[525]
  PIN i_pkt[526]
    DIRECTION INPUT ;
    USE SIGNAL ;
    PORT
      LAYER M4 ;
        RECT  86.358 29.472 86.442 29.496 ;
    END
  END i_pkt[526]
  PIN i_pkt[527]
    DIRECTION INPUT ;
    USE SIGNAL ;
    PORT
      LAYER M4 ;
        RECT  86.358 29.568 86.442 29.592 ;
    END
  END i_pkt[527]
  PIN i_pkt[528]
    DIRECTION INPUT ;
    USE SIGNAL ;
    PORT
      LAYER M4 ;
        RECT  86.358 29.664 86.442 29.688 ;
    END
  END i_pkt[528]
  PIN i_pkt[529]
    DIRECTION INPUT ;
    USE SIGNAL ;
    PORT
      LAYER M4 ;
        RECT  86.358 29.76 86.442 29.784 ;
    END
  END i_pkt[529]
  PIN i_pkt[52]
    DIRECTION INPUT ;
    USE SIGNAL ;
    PORT
      LAYER M4 ;
        RECT  86.358 100.992 86.442 101.016 ;
    END
  END i_pkt[52]
  PIN i_pkt[530]
    DIRECTION INPUT ;
    USE SIGNAL ;
    PORT
      LAYER M4 ;
        RECT  86.358 29.856 86.442 29.88 ;
    END
  END i_pkt[530]
  PIN i_pkt[531]
    DIRECTION INPUT ;
    USE SIGNAL ;
    PORT
      LAYER M4 ;
        RECT  86.358 29.952 86.442 29.976 ;
    END
  END i_pkt[531]
  PIN i_pkt[532]
    DIRECTION INPUT ;
    USE SIGNAL ;
    PORT
      LAYER M4 ;
        RECT  86.358 30.048 86.442 30.072 ;
    END
  END i_pkt[532]
  PIN i_pkt[533]
    DIRECTION INPUT ;
    USE SIGNAL ;
    PORT
      LAYER M4 ;
        RECT  86.358 30.144 86.442 30.168 ;
    END
  END i_pkt[533]
  PIN i_pkt[534]
    DIRECTION INPUT ;
    USE SIGNAL ;
    PORT
      LAYER M4 ;
        RECT  86.358 30.24 86.442 30.264 ;
    END
  END i_pkt[534]
  PIN i_pkt[535]
    DIRECTION INPUT ;
    USE SIGNAL ;
    PORT
      LAYER M4 ;
        RECT  86.358 30.336 86.442 30.36 ;
    END
  END i_pkt[535]
  PIN i_pkt[536]
    DIRECTION INPUT ;
    USE SIGNAL ;
    PORT
      LAYER M4 ;
        RECT  86.358 30.432 86.442 30.456 ;
    END
  END i_pkt[536]
  PIN i_pkt[537]
    DIRECTION INPUT ;
    USE SIGNAL ;
    PORT
      LAYER M4 ;
        RECT  86.358 30.528 86.442 30.552 ;
    END
  END i_pkt[537]
  PIN i_pkt[538]
    DIRECTION INPUT ;
    USE SIGNAL ;
    PORT
      LAYER M4 ;
        RECT  86.358 30.624 86.442 30.648 ;
    END
  END i_pkt[538]
  PIN i_pkt[539]
    DIRECTION INPUT ;
    USE SIGNAL ;
    PORT
      LAYER M4 ;
        RECT  86.358 30.72 86.442 30.744 ;
    END
  END i_pkt[539]
  PIN i_pkt[53]
    DIRECTION INPUT ;
    USE SIGNAL ;
    PORT
      LAYER M4 ;
        RECT  86.358 101.088 86.442 101.112 ;
    END
  END i_pkt[53]
  PIN i_pkt[540]
    DIRECTION INPUT ;
    USE SIGNAL ;
    PORT
      LAYER M4 ;
        RECT  86.358 30.816 86.442 30.84 ;
    END
  END i_pkt[540]
  PIN i_pkt[541]
    DIRECTION INPUT ;
    USE SIGNAL ;
    PORT
      LAYER M4 ;
        RECT  86.358 30.912 86.442 30.936 ;
    END
  END i_pkt[541]
  PIN i_pkt[542]
    DIRECTION INPUT ;
    USE SIGNAL ;
    PORT
      LAYER M4 ;
        RECT  86.358 31.008 86.442 31.032 ;
    END
  END i_pkt[542]
  PIN i_pkt[543]
    DIRECTION INPUT ;
    USE SIGNAL ;
    PORT
      LAYER M4 ;
        RECT  86.358 31.104 86.442 31.128 ;
    END
  END i_pkt[543]
  PIN i_pkt[544]
    DIRECTION INPUT ;
    USE SIGNAL ;
    PORT
      LAYER M4 ;
        RECT  86.358 31.2 86.442 31.224 ;
    END
  END i_pkt[544]
  PIN i_pkt[545]
    DIRECTION INPUT ;
    USE SIGNAL ;
    PORT
      LAYER M4 ;
        RECT  86.358 31.296 86.442 31.32 ;
    END
  END i_pkt[545]
  PIN i_pkt[546]
    DIRECTION INPUT ;
    USE SIGNAL ;
    PORT
      LAYER M4 ;
        RECT  86.358 31.392 86.442 31.416 ;
    END
  END i_pkt[546]
  PIN i_pkt[547]
    DIRECTION INPUT ;
    USE SIGNAL ;
    PORT
      LAYER M4 ;
        RECT  86.358 31.488 86.442 31.512 ;
    END
  END i_pkt[547]
  PIN i_pkt[548]
    DIRECTION INPUT ;
    USE SIGNAL ;
    PORT
      LAYER M4 ;
        RECT  86.358 31.584 86.442 31.608 ;
    END
  END i_pkt[548]
  PIN i_pkt[549]
    DIRECTION INPUT ;
    USE SIGNAL ;
    PORT
      LAYER M4 ;
        RECT  86.358 31.68 86.442 31.704 ;
    END
  END i_pkt[549]
  PIN i_pkt[54]
    DIRECTION INPUT ;
    USE SIGNAL ;
    PORT
      LAYER M4 ;
        RECT  86.358 101.184 86.442 101.208 ;
    END
  END i_pkt[54]
  PIN i_pkt[550]
    DIRECTION INPUT ;
    USE SIGNAL ;
    PORT
      LAYER M4 ;
        RECT  86.358 31.776 86.442 31.8 ;
    END
  END i_pkt[550]
  PIN i_pkt[551]
    DIRECTION INPUT ;
    USE SIGNAL ;
    PORT
      LAYER M4 ;
        RECT  86.358 31.872 86.442 31.896 ;
    END
  END i_pkt[551]
  PIN i_pkt[552]
    DIRECTION INPUT ;
    USE SIGNAL ;
    PORT
      LAYER M4 ;
        RECT  86.358 31.968 86.442 31.992 ;
    END
  END i_pkt[552]
  PIN i_pkt[553]
    DIRECTION INPUT ;
    USE SIGNAL ;
    PORT
      LAYER M4 ;
        RECT  86.358 32.064 86.442 32.088 ;
    END
  END i_pkt[553]
  PIN i_pkt[554]
    DIRECTION INPUT ;
    USE SIGNAL ;
    PORT
      LAYER M4 ;
        RECT  86.358 32.16 86.442 32.184 ;
    END
  END i_pkt[554]
  PIN i_pkt[555]
    DIRECTION INPUT ;
    USE SIGNAL ;
    PORT
      LAYER M4 ;
        RECT  86.358 32.256 86.442 32.28 ;
    END
  END i_pkt[555]
  PIN i_pkt[556]
    DIRECTION INPUT ;
    USE SIGNAL ;
    PORT
      LAYER M4 ;
        RECT  86.358 32.352 86.442 32.376 ;
    END
  END i_pkt[556]
  PIN i_pkt[557]
    DIRECTION INPUT ;
    USE SIGNAL ;
    PORT
      LAYER M4 ;
        RECT  86.358 32.448 86.442 32.472 ;
    END
  END i_pkt[557]
  PIN i_pkt[55]
    DIRECTION INPUT ;
    USE SIGNAL ;
    PORT
      LAYER M4 ;
        RECT  86.358 101.28 86.442 101.304 ;
    END
  END i_pkt[55]
  PIN i_pkt[56]
    DIRECTION INPUT ;
    USE SIGNAL ;
    PORT
      LAYER M4 ;
        RECT  86.358 101.376 86.442 101.4 ;
    END
  END i_pkt[56]
  PIN i_pkt[57]
    DIRECTION INPUT ;
    USE SIGNAL ;
    PORT
      LAYER M4 ;
        RECT  86.358 101.472 86.442 101.496 ;
    END
  END i_pkt[57]
  PIN i_pkt[58]
    DIRECTION INPUT ;
    USE SIGNAL ;
    PORT
      LAYER M4 ;
        RECT  86.358 101.568 86.442 101.592 ;
    END
  END i_pkt[58]
  PIN i_pkt[59]
    DIRECTION INPUT ;
    USE SIGNAL ;
    PORT
      LAYER M4 ;
        RECT  86.358 101.664 86.442 101.688 ;
    END
  END i_pkt[59]
  PIN i_pkt[5]
    DIRECTION INPUT ;
    USE SIGNAL ;
    PORT
      LAYER M4 ;
        RECT  86.358 96.48 86.442 96.504 ;
    END
  END i_pkt[5]
  PIN i_pkt[60]
    DIRECTION INPUT ;
    USE SIGNAL ;
    PORT
      LAYER M4 ;
        RECT  86.358 101.76 86.442 101.784 ;
    END
  END i_pkt[60]
  PIN i_pkt[61]
    DIRECTION INPUT ;
    USE SIGNAL ;
    PORT
      LAYER M4 ;
        RECT  86.358 101.856 86.442 101.88 ;
    END
  END i_pkt[61]
  PIN i_pkt[62]
    DIRECTION INPUT ;
    USE SIGNAL ;
    PORT
      LAYER M4 ;
        RECT  86.358 101.952 86.442 101.976 ;
    END
  END i_pkt[62]
  PIN i_pkt[63]
    DIRECTION INPUT ;
    USE SIGNAL ;
    PORT
      LAYER M4 ;
        RECT  86.358 102.048 86.442 102.072 ;
    END
  END i_pkt[63]
  PIN i_pkt[64]
    DIRECTION INPUT ;
    USE SIGNAL ;
    PORT
      LAYER M4 ;
        RECT  86.358 102.144 86.442 102.168 ;
    END
  END i_pkt[64]
  PIN i_pkt[65]
    DIRECTION INPUT ;
    USE SIGNAL ;
    PORT
      LAYER M4 ;
        RECT  86.358 102.24 86.442 102.264 ;
    END
  END i_pkt[65]
  PIN i_pkt[66]
    DIRECTION INPUT ;
    USE SIGNAL ;
    PORT
      LAYER M4 ;
        RECT  86.358 102.336 86.442 102.36 ;
    END
  END i_pkt[66]
  PIN i_pkt[67]
    DIRECTION INPUT ;
    USE SIGNAL ;
    PORT
      LAYER M4 ;
        RECT  86.358 102.432 86.442 102.456 ;
    END
  END i_pkt[67]
  PIN i_pkt[68]
    DIRECTION INPUT ;
    USE SIGNAL ;
    PORT
      LAYER M4 ;
        RECT  86.358 102.528 86.442 102.552 ;
    END
  END i_pkt[68]
  PIN i_pkt[69]
    DIRECTION INPUT ;
    USE SIGNAL ;
    PORT
      LAYER M4 ;
        RECT  86.358 102.624 86.442 102.648 ;
    END
  END i_pkt[69]
  PIN i_pkt[6]
    DIRECTION INPUT ;
    USE SIGNAL ;
    PORT
      LAYER M4 ;
        RECT  86.358 96.576 86.442 96.6 ;
    END
  END i_pkt[6]
  PIN i_pkt[70]
    DIRECTION INPUT ;
    USE SIGNAL ;
    PORT
      LAYER M4 ;
        RECT  86.358 102.72 86.442 102.744 ;
    END
  END i_pkt[70]
  PIN i_pkt[71]
    DIRECTION INPUT ;
    USE SIGNAL ;
    PORT
      LAYER M4 ;
        RECT  86.358 102.816 86.442 102.84 ;
    END
  END i_pkt[71]
  PIN i_pkt[72]
    DIRECTION INPUT ;
    USE SIGNAL ;
    PORT
      LAYER M4 ;
        RECT  86.358 102.912 86.442 102.936 ;
    END
  END i_pkt[72]
  PIN i_pkt[73]
    DIRECTION INPUT ;
    USE SIGNAL ;
    PORT
      LAYER M4 ;
        RECT  86.358 103.008 86.442 103.032 ;
    END
  END i_pkt[73]
  PIN i_pkt[74]
    DIRECTION INPUT ;
    USE SIGNAL ;
    PORT
      LAYER M4 ;
        RECT  86.358 103.104 86.442 103.128 ;
    END
  END i_pkt[74]
  PIN i_pkt[75]
    DIRECTION INPUT ;
    USE SIGNAL ;
    PORT
      LAYER M4 ;
        RECT  86.358 103.2 86.442 103.224 ;
    END
  END i_pkt[75]
  PIN i_pkt[76]
    DIRECTION INPUT ;
    USE SIGNAL ;
    PORT
      LAYER M4 ;
        RECT  86.358 103.296 86.442 103.32 ;
    END
  END i_pkt[76]
  PIN i_pkt[77]
    DIRECTION INPUT ;
    USE SIGNAL ;
    PORT
      LAYER M4 ;
        RECT  86.358 103.392 86.442 103.416 ;
    END
  END i_pkt[77]
  PIN i_pkt[78]
    DIRECTION INPUT ;
    USE SIGNAL ;
    PORT
      LAYER M4 ;
        RECT  86.358 103.488 86.442 103.512 ;
    END
  END i_pkt[78]
  PIN i_pkt[79]
    DIRECTION INPUT ;
    USE SIGNAL ;
    PORT
      LAYER M4 ;
        RECT  86.358 103.584 86.442 103.608 ;
    END
  END i_pkt[79]
  PIN i_pkt[7]
    DIRECTION INPUT ;
    USE SIGNAL ;
    PORT
      LAYER M4 ;
        RECT  86.358 96.672 86.442 96.696 ;
    END
  END i_pkt[7]
  PIN i_pkt[80]
    DIRECTION INPUT ;
    USE SIGNAL ;
    PORT
      LAYER M4 ;
        RECT  86.358 103.68 86.442 103.704 ;
    END
  END i_pkt[80]
  PIN i_pkt[81]
    DIRECTION INPUT ;
    USE SIGNAL ;
    PORT
      LAYER M4 ;
        RECT  86.358 103.776 86.442 103.8 ;
    END
  END i_pkt[81]
  PIN i_pkt[82]
    DIRECTION INPUT ;
    USE SIGNAL ;
    PORT
      LAYER M4 ;
        RECT  86.358 103.872 86.442 103.896 ;
    END
  END i_pkt[82]
  PIN i_pkt[83]
    DIRECTION INPUT ;
    USE SIGNAL ;
    PORT
      LAYER M4 ;
        RECT  86.358 103.968 86.442 103.992 ;
    END
  END i_pkt[83]
  PIN i_pkt[84]
    DIRECTION INPUT ;
    USE SIGNAL ;
    PORT
      LAYER M4 ;
        RECT  86.358 104.064 86.442 104.088 ;
    END
  END i_pkt[84]
  PIN i_pkt[85]
    DIRECTION INPUT ;
    USE SIGNAL ;
    PORT
      LAYER M4 ;
        RECT  86.358 104.16 86.442 104.184 ;
    END
  END i_pkt[85]
  PIN i_pkt[86]
    DIRECTION INPUT ;
    USE SIGNAL ;
    PORT
      LAYER M4 ;
        RECT  86.358 104.256 86.442 104.28 ;
    END
  END i_pkt[86]
  PIN i_pkt[87]
    DIRECTION INPUT ;
    USE SIGNAL ;
    PORT
      LAYER M4 ;
        RECT  86.358 104.352 86.442 104.376 ;
    END
  END i_pkt[87]
  PIN i_pkt[88]
    DIRECTION INPUT ;
    USE SIGNAL ;
    PORT
      LAYER M4 ;
        RECT  86.358 104.448 86.442 104.472 ;
    END
  END i_pkt[88]
  PIN i_pkt[89]
    DIRECTION INPUT ;
    USE SIGNAL ;
    PORT
      LAYER M4 ;
        RECT  86.358 104.544 86.442 104.568 ;
    END
  END i_pkt[89]
  PIN i_pkt[8]
    DIRECTION INPUT ;
    USE SIGNAL ;
    PORT
      LAYER M4 ;
        RECT  86.358 96.768 86.442 96.792 ;
    END
  END i_pkt[8]
  PIN i_pkt[90]
    DIRECTION INPUT ;
    USE SIGNAL ;
    PORT
      LAYER M4 ;
        RECT  86.358 104.64 86.442 104.664 ;
    END
  END i_pkt[90]
  PIN i_pkt[91]
    DIRECTION INPUT ;
    USE SIGNAL ;
    PORT
      LAYER M4 ;
        RECT  86.358 104.736 86.442 104.76 ;
    END
  END i_pkt[91]
  PIN i_pkt[92]
    DIRECTION INPUT ;
    USE SIGNAL ;
    PORT
      LAYER M4 ;
        RECT  86.358 104.832 86.442 104.856 ;
    END
  END i_pkt[92]
  PIN i_pkt[93]
    DIRECTION INPUT ;
    USE SIGNAL ;
    PORT
      LAYER M4 ;
        RECT  86.358 104.928 86.442 104.952 ;
    END
  END i_pkt[93]
  PIN i_pkt[94]
    DIRECTION INPUT ;
    USE SIGNAL ;
    PORT
      LAYER M4 ;
        RECT  86.358 105.024 86.442 105.048 ;
    END
  END i_pkt[94]
  PIN i_pkt[95]
    DIRECTION INPUT ;
    USE SIGNAL ;
    PORT
      LAYER M4 ;
        RECT  86.358 105.12 86.442 105.144 ;
    END
  END i_pkt[95]
  PIN i_pkt[96]
    DIRECTION INPUT ;
    USE SIGNAL ;
    PORT
      LAYER M4 ;
        RECT  86.358 105.216 86.442 105.24 ;
    END
  END i_pkt[96]
  PIN i_pkt[97]
    DIRECTION INPUT ;
    USE SIGNAL ;
    PORT
      LAYER M4 ;
        RECT  86.358 105.312 86.442 105.336 ;
    END
  END i_pkt[97]
  PIN i_pkt[98]
    DIRECTION INPUT ;
    USE SIGNAL ;
    PORT
      LAYER M4 ;
        RECT  86.358 105.408 86.442 105.432 ;
    END
  END i_pkt[98]
  PIN i_pkt[99]
    DIRECTION INPUT ;
    USE SIGNAL ;
    PORT
      LAYER M4 ;
        RECT  86.358 105.504 86.442 105.528 ;
    END
  END i_pkt[99]
  PIN i_pkt[9]
    DIRECTION INPUT ;
    USE SIGNAL ;
    PORT
      LAYER M4 ;
        RECT  86.358 96.864 86.442 96.888 ;
    END
  END i_pkt[9]
  PIN i_v[0]
    DIRECTION INPUT ;
    USE SIGNAL ;
    PORT
      LAYER M4 ;
        RECT  86.358 126.72 86.442 126.744 ;
    END
    PORT
      LAYER M4 ;
        RECT  83.704 126.72 86.4 126.744 ;
    END
  END i_v[0]
  PIN i_v[1]
    DIRECTION INPUT ;
    USE SIGNAL ;
    PORT
      LAYER M5 ;
        RECT  86.316 2.844 86.412 2.94 ;
    END
    PORT
      LAYER M5 ;
        RECT  86.208 2.869 86.376 2.915 ;
    END
  END i_v[1]
  PIN n_p[0]
    DIRECTION OUTPUT ;
    USE SIGNAL ;
    PORT
      LAYER M4 ;
        RECT  -0.042 51.408 0.042 51.432 ;
    END
  END n_p[0]
  PIN n_p[100]
    DIRECTION OUTPUT ;
    USE SIGNAL ;
    PORT
      LAYER M4 ;
        RECT  -0.042 61.008 0.042 61.032 ;
    END
  END n_p[100]
  PIN n_p[101]
    DIRECTION OUTPUT ;
    USE SIGNAL ;
    PORT
      LAYER M4 ;
        RECT  -0.042 61.104 0.042 61.128 ;
    END
  END n_p[101]
  PIN n_p[102]
    DIRECTION OUTPUT ;
    USE SIGNAL ;
    PORT
      LAYER M4 ;
        RECT  -0.042 61.2 0.042 61.224 ;
    END
  END n_p[102]
  PIN n_p[103]
    DIRECTION OUTPUT ;
    USE SIGNAL ;
    PORT
      LAYER M4 ;
        RECT  -0.042 61.296 0.042 61.32 ;
    END
  END n_p[103]
  PIN n_p[104]
    DIRECTION OUTPUT ;
    USE SIGNAL ;
    PORT
      LAYER M4 ;
        RECT  -0.042 61.392 0.042 61.416 ;
    END
  END n_p[104]
  PIN n_p[105]
    DIRECTION OUTPUT ;
    USE SIGNAL ;
    PORT
      LAYER M4 ;
        RECT  -0.042 61.488 0.042 61.512 ;
    END
  END n_p[105]
  PIN n_p[106]
    DIRECTION OUTPUT ;
    USE SIGNAL ;
    PORT
      LAYER M4 ;
        RECT  -0.042 61.584 0.042 61.608 ;
    END
  END n_p[106]
  PIN n_p[107]
    DIRECTION OUTPUT ;
    USE SIGNAL ;
    PORT
      LAYER M4 ;
        RECT  -0.042 61.68 0.042 61.704 ;
    END
  END n_p[107]
  PIN n_p[108]
    DIRECTION OUTPUT ;
    USE SIGNAL ;
    PORT
      LAYER M4 ;
        RECT  -0.042 61.776 0.042 61.8 ;
    END
  END n_p[108]
  PIN n_p[109]
    DIRECTION OUTPUT ;
    USE SIGNAL ;
    PORT
      LAYER M4 ;
        RECT  -0.042 61.872 0.042 61.896 ;
    END
  END n_p[109]
  PIN n_p[10]
    DIRECTION OUTPUT ;
    USE SIGNAL ;
    PORT
      LAYER M4 ;
        RECT  -0.042 52.368 0.042 52.392 ;
    END
  END n_p[10]
  PIN n_p[110]
    DIRECTION OUTPUT ;
    USE SIGNAL ;
    PORT
      LAYER M4 ;
        RECT  -0.042 61.968 0.042 61.992 ;
    END
  END n_p[110]
  PIN n_p[111]
    DIRECTION OUTPUT ;
    USE SIGNAL ;
    PORT
      LAYER M4 ;
        RECT  -0.042 62.064 0.042 62.088 ;
    END
  END n_p[111]
  PIN n_p[112]
    DIRECTION OUTPUT ;
    USE SIGNAL ;
    PORT
      LAYER M4 ;
        RECT  -0.042 62.16 0.042 62.184 ;
    END
  END n_p[112]
  PIN n_p[113]
    DIRECTION OUTPUT ;
    USE SIGNAL ;
    PORT
      LAYER M4 ;
        RECT  -0.042 62.256 0.042 62.28 ;
    END
  END n_p[113]
  PIN n_p[114]
    DIRECTION OUTPUT ;
    USE SIGNAL ;
    PORT
      LAYER M4 ;
        RECT  -0.042 62.352 0.042 62.376 ;
    END
  END n_p[114]
  PIN n_p[115]
    DIRECTION OUTPUT ;
    USE SIGNAL ;
    PORT
      LAYER M4 ;
        RECT  -0.042 62.448 0.042 62.472 ;
    END
  END n_p[115]
  PIN n_p[116]
    DIRECTION OUTPUT ;
    USE SIGNAL ;
    PORT
      LAYER M4 ;
        RECT  -0.042 62.544 0.042 62.568 ;
    END
  END n_p[116]
  PIN n_p[117]
    DIRECTION OUTPUT ;
    USE SIGNAL ;
    PORT
      LAYER M4 ;
        RECT  -0.042 62.64 0.042 62.664 ;
    END
  END n_p[117]
  PIN n_p[118]
    DIRECTION OUTPUT ;
    USE SIGNAL ;
    PORT
      LAYER M4 ;
        RECT  -0.042 62.736 0.042 62.76 ;
    END
  END n_p[118]
  PIN n_p[119]
    DIRECTION OUTPUT ;
    USE SIGNAL ;
    PORT
      LAYER M4 ;
        RECT  -0.042 62.832 0.042 62.856 ;
    END
  END n_p[119]
  PIN n_p[11]
    DIRECTION OUTPUT ;
    USE SIGNAL ;
    PORT
      LAYER M4 ;
        RECT  -0.042 52.464 0.042 52.488 ;
    END
  END n_p[11]
  PIN n_p[120]
    DIRECTION OUTPUT ;
    USE SIGNAL ;
    PORT
      LAYER M4 ;
        RECT  -0.042 62.928 0.042 62.952 ;
    END
  END n_p[120]
  PIN n_p[121]
    DIRECTION OUTPUT ;
    USE SIGNAL ;
    PORT
      LAYER M4 ;
        RECT  -0.042 63.024 0.042 63.048 ;
    END
  END n_p[121]
  PIN n_p[122]
    DIRECTION OUTPUT ;
    USE SIGNAL ;
    PORT
      LAYER M4 ;
        RECT  -0.042 63.12 0.042 63.144 ;
    END
  END n_p[122]
  PIN n_p[123]
    DIRECTION OUTPUT ;
    USE SIGNAL ;
    PORT
      LAYER M4 ;
        RECT  -0.042 63.216 0.042 63.24 ;
    END
  END n_p[123]
  PIN n_p[124]
    DIRECTION OUTPUT ;
    USE SIGNAL ;
    PORT
      LAYER M4 ;
        RECT  -0.042 63.312 0.042 63.336 ;
    END
  END n_p[124]
  PIN n_p[125]
    DIRECTION OUTPUT ;
    USE SIGNAL ;
    PORT
      LAYER M4 ;
        RECT  -0.042 63.408 0.042 63.432 ;
    END
  END n_p[125]
  PIN n_p[126]
    DIRECTION OUTPUT ;
    USE SIGNAL ;
    PORT
      LAYER M4 ;
        RECT  -0.042 63.504 0.042 63.528 ;
    END
  END n_p[126]
  PIN n_p[127]
    DIRECTION OUTPUT ;
    USE SIGNAL ;
    PORT
      LAYER M4 ;
        RECT  -0.042 63.6 0.042 63.624 ;
    END
  END n_p[127]
  PIN n_p[128]
    DIRECTION OUTPUT ;
    USE SIGNAL ;
    PORT
      LAYER M4 ;
        RECT  -0.042 63.696 0.042 63.72 ;
    END
  END n_p[128]
  PIN n_p[129]
    DIRECTION OUTPUT ;
    USE SIGNAL ;
    PORT
      LAYER M4 ;
        RECT  -0.042 63.792 0.042 63.816 ;
    END
  END n_p[129]
  PIN n_p[12]
    DIRECTION OUTPUT ;
    USE SIGNAL ;
    PORT
      LAYER M4 ;
        RECT  -0.042 52.56 0.042 52.584 ;
    END
  END n_p[12]
  PIN n_p[130]
    DIRECTION OUTPUT ;
    USE SIGNAL ;
    PORT
      LAYER M4 ;
        RECT  -0.042 63.888 0.042 63.912 ;
    END
  END n_p[130]
  PIN n_p[131]
    DIRECTION OUTPUT ;
    USE SIGNAL ;
    PORT
      LAYER M4 ;
        RECT  -0.042 63.984 0.042 64.008 ;
    END
  END n_p[131]
  PIN n_p[132]
    DIRECTION OUTPUT ;
    USE SIGNAL ;
    PORT
      LAYER M4 ;
        RECT  -0.042 64.08 0.042 64.104 ;
    END
  END n_p[132]
  PIN n_p[133]
    DIRECTION OUTPUT ;
    USE SIGNAL ;
    PORT
      LAYER M4 ;
        RECT  -0.042 64.176 0.042 64.2 ;
    END
  END n_p[133]
  PIN n_p[134]
    DIRECTION OUTPUT ;
    USE SIGNAL ;
    PORT
      LAYER M4 ;
        RECT  -0.042 64.272 0.042 64.296 ;
    END
  END n_p[134]
  PIN n_p[135]
    DIRECTION OUTPUT ;
    USE SIGNAL ;
    PORT
      LAYER M4 ;
        RECT  -0.042 64.368 0.042 64.392 ;
    END
  END n_p[135]
  PIN n_p[136]
    DIRECTION OUTPUT ;
    USE SIGNAL ;
    PORT
      LAYER M4 ;
        RECT  -0.042 64.464 0.042 64.488 ;
    END
  END n_p[136]
  PIN n_p[137]
    DIRECTION OUTPUT ;
    USE SIGNAL ;
    PORT
      LAYER M4 ;
        RECT  -0.042 64.56 0.042 64.584 ;
    END
  END n_p[137]
  PIN n_p[138]
    DIRECTION OUTPUT ;
    USE SIGNAL ;
    PORT
      LAYER M4 ;
        RECT  -0.042 64.656 0.042 64.68 ;
    END
  END n_p[138]
  PIN n_p[139]
    DIRECTION OUTPUT ;
    USE SIGNAL ;
    PORT
      LAYER M4 ;
        RECT  -0.042 64.752 0.042 64.776 ;
    END
  END n_p[139]
  PIN n_p[13]
    DIRECTION OUTPUT ;
    USE SIGNAL ;
    PORT
      LAYER M4 ;
        RECT  -0.042 52.656 0.042 52.68 ;
    END
  END n_p[13]
  PIN n_p[140]
    DIRECTION OUTPUT ;
    USE SIGNAL ;
    PORT
      LAYER M4 ;
        RECT  -0.042 64.848 0.042 64.872 ;
    END
  END n_p[140]
  PIN n_p[141]
    DIRECTION OUTPUT ;
    USE SIGNAL ;
    PORT
      LAYER M4 ;
        RECT  -0.042 64.944 0.042 64.968 ;
    END
  END n_p[141]
  PIN n_p[142]
    DIRECTION OUTPUT ;
    USE SIGNAL ;
    PORT
      LAYER M4 ;
        RECT  -0.042 65.04 0.042 65.064 ;
    END
  END n_p[142]
  PIN n_p[143]
    DIRECTION OUTPUT ;
    USE SIGNAL ;
    PORT
      LAYER M4 ;
        RECT  -0.042 65.136 0.042 65.16 ;
    END
  END n_p[143]
  PIN n_p[144]
    DIRECTION OUTPUT ;
    USE SIGNAL ;
    PORT
      LAYER M4 ;
        RECT  -0.042 65.232 0.042 65.256 ;
    END
  END n_p[144]
  PIN n_p[145]
    DIRECTION OUTPUT ;
    USE SIGNAL ;
    PORT
      LAYER M4 ;
        RECT  -0.042 65.328 0.042 65.352 ;
    END
  END n_p[145]
  PIN n_p[146]
    DIRECTION OUTPUT ;
    USE SIGNAL ;
    PORT
      LAYER M4 ;
        RECT  -0.042 65.424 0.042 65.448 ;
    END
  END n_p[146]
  PIN n_p[147]
    DIRECTION OUTPUT ;
    USE SIGNAL ;
    PORT
      LAYER M4 ;
        RECT  -0.042 65.52 0.042 65.544 ;
    END
  END n_p[147]
  PIN n_p[148]
    DIRECTION OUTPUT ;
    USE SIGNAL ;
    PORT
      LAYER M4 ;
        RECT  -0.042 65.616 0.042 65.64 ;
    END
  END n_p[148]
  PIN n_p[149]
    DIRECTION OUTPUT ;
    USE SIGNAL ;
    PORT
      LAYER M4 ;
        RECT  -0.042 65.712 0.042 65.736 ;
    END
  END n_p[149]
  PIN n_p[14]
    DIRECTION OUTPUT ;
    USE SIGNAL ;
    PORT
      LAYER M4 ;
        RECT  -0.042 52.752 0.042 52.776 ;
    END
  END n_p[14]
  PIN n_p[150]
    DIRECTION OUTPUT ;
    USE SIGNAL ;
    PORT
      LAYER M4 ;
        RECT  -0.042 65.808 0.042 65.832 ;
    END
  END n_p[150]
  PIN n_p[151]
    DIRECTION OUTPUT ;
    USE SIGNAL ;
    PORT
      LAYER M4 ;
        RECT  -0.042 65.904 0.042 65.928 ;
    END
  END n_p[151]
  PIN n_p[152]
    DIRECTION OUTPUT ;
    USE SIGNAL ;
    PORT
      LAYER M4 ;
        RECT  -0.042 66 0.042 66.024 ;
    END
  END n_p[152]
  PIN n_p[153]
    DIRECTION OUTPUT ;
    USE SIGNAL ;
    PORT
      LAYER M4 ;
        RECT  -0.042 66.096 0.042 66.12 ;
    END
  END n_p[153]
  PIN n_p[154]
    DIRECTION OUTPUT ;
    USE SIGNAL ;
    PORT
      LAYER M4 ;
        RECT  -0.042 66.192 0.042 66.216 ;
    END
  END n_p[154]
  PIN n_p[155]
    DIRECTION OUTPUT ;
    USE SIGNAL ;
    PORT
      LAYER M4 ;
        RECT  -0.042 66.288 0.042 66.312 ;
    END
  END n_p[155]
  PIN n_p[156]
    DIRECTION OUTPUT ;
    USE SIGNAL ;
    PORT
      LAYER M4 ;
        RECT  -0.042 66.384 0.042 66.408 ;
    END
  END n_p[156]
  PIN n_p[157]
    DIRECTION OUTPUT ;
    USE SIGNAL ;
    PORT
      LAYER M4 ;
        RECT  -0.042 66.48 0.042 66.504 ;
    END
  END n_p[157]
  PIN n_p[158]
    DIRECTION OUTPUT ;
    USE SIGNAL ;
    PORT
      LAYER M4 ;
        RECT  -0.042 66.576 0.042 66.6 ;
    END
  END n_p[158]
  PIN n_p[159]
    DIRECTION OUTPUT ;
    USE SIGNAL ;
    PORT
      LAYER M4 ;
        RECT  -0.042 66.672 0.042 66.696 ;
    END
  END n_p[159]
  PIN n_p[15]
    DIRECTION OUTPUT ;
    USE SIGNAL ;
    PORT
      LAYER M4 ;
        RECT  -0.042 52.848 0.042 52.872 ;
    END
  END n_p[15]
  PIN n_p[160]
    DIRECTION OUTPUT ;
    USE SIGNAL ;
    PORT
      LAYER M4 ;
        RECT  -0.042 66.768 0.042 66.792 ;
    END
  END n_p[160]
  PIN n_p[161]
    DIRECTION OUTPUT ;
    USE SIGNAL ;
    PORT
      LAYER M4 ;
        RECT  -0.042 66.864 0.042 66.888 ;
    END
  END n_p[161]
  PIN n_p[162]
    DIRECTION OUTPUT ;
    USE SIGNAL ;
    PORT
      LAYER M4 ;
        RECT  -0.042 66.96 0.042 66.984 ;
    END
  END n_p[162]
  PIN n_p[163]
    DIRECTION OUTPUT ;
    USE SIGNAL ;
    PORT
      LAYER M4 ;
        RECT  -0.042 67.056 0.042 67.08 ;
    END
  END n_p[163]
  PIN n_p[164]
    DIRECTION OUTPUT ;
    USE SIGNAL ;
    PORT
      LAYER M4 ;
        RECT  -0.042 67.152 0.042 67.176 ;
    END
  END n_p[164]
  PIN n_p[165]
    DIRECTION OUTPUT ;
    USE SIGNAL ;
    PORT
      LAYER M4 ;
        RECT  -0.042 67.248 0.042 67.272 ;
    END
  END n_p[165]
  PIN n_p[166]
    DIRECTION OUTPUT ;
    USE SIGNAL ;
    PORT
      LAYER M4 ;
        RECT  -0.042 67.344 0.042 67.368 ;
    END
  END n_p[166]
  PIN n_p[167]
    DIRECTION OUTPUT ;
    USE SIGNAL ;
    PORT
      LAYER M4 ;
        RECT  -0.042 67.44 0.042 67.464 ;
    END
  END n_p[167]
  PIN n_p[168]
    DIRECTION OUTPUT ;
    USE SIGNAL ;
    PORT
      LAYER M4 ;
        RECT  -0.042 67.536 0.042 67.56 ;
    END
  END n_p[168]
  PIN n_p[169]
    DIRECTION OUTPUT ;
    USE SIGNAL ;
    PORT
      LAYER M4 ;
        RECT  -0.042 67.632 0.042 67.656 ;
    END
  END n_p[169]
  PIN n_p[16]
    DIRECTION OUTPUT ;
    USE SIGNAL ;
    PORT
      LAYER M4 ;
        RECT  -0.042 52.944 0.042 52.968 ;
    END
  END n_p[16]
  PIN n_p[170]
    DIRECTION OUTPUT ;
    USE SIGNAL ;
    PORT
      LAYER M4 ;
        RECT  -0.042 67.728 0.042 67.752 ;
    END
  END n_p[170]
  PIN n_p[171]
    DIRECTION OUTPUT ;
    USE SIGNAL ;
    PORT
      LAYER M4 ;
        RECT  -0.042 67.824 0.042 67.848 ;
    END
  END n_p[171]
  PIN n_p[172]
    DIRECTION OUTPUT ;
    USE SIGNAL ;
    PORT
      LAYER M4 ;
        RECT  -0.042 67.92 0.042 67.944 ;
    END
  END n_p[172]
  PIN n_p[173]
    DIRECTION OUTPUT ;
    USE SIGNAL ;
    PORT
      LAYER M4 ;
        RECT  -0.042 68.016 0.042 68.04 ;
    END
  END n_p[173]
  PIN n_p[174]
    DIRECTION OUTPUT ;
    USE SIGNAL ;
    PORT
      LAYER M4 ;
        RECT  -0.042 68.112 0.042 68.136 ;
    END
  END n_p[174]
  PIN n_p[175]
    DIRECTION OUTPUT ;
    USE SIGNAL ;
    PORT
      LAYER M4 ;
        RECT  -0.042 68.208 0.042 68.232 ;
    END
  END n_p[175]
  PIN n_p[176]
    DIRECTION OUTPUT ;
    USE SIGNAL ;
    PORT
      LAYER M4 ;
        RECT  -0.042 68.304 0.042 68.328 ;
    END
  END n_p[176]
  PIN n_p[177]
    DIRECTION OUTPUT ;
    USE SIGNAL ;
    PORT
      LAYER M4 ;
        RECT  -0.042 68.4 0.042 68.424 ;
    END
  END n_p[177]
  PIN n_p[178]
    DIRECTION OUTPUT ;
    USE SIGNAL ;
    PORT
      LAYER M4 ;
        RECT  -0.042 68.496 0.042 68.52 ;
    END
  END n_p[178]
  PIN n_p[179]
    DIRECTION OUTPUT ;
    USE SIGNAL ;
    PORT
      LAYER M4 ;
        RECT  -0.042 68.592 0.042 68.616 ;
    END
  END n_p[179]
  PIN n_p[17]
    DIRECTION OUTPUT ;
    USE SIGNAL ;
    PORT
      LAYER M4 ;
        RECT  -0.042 53.04 0.042 53.064 ;
    END
  END n_p[17]
  PIN n_p[180]
    DIRECTION OUTPUT ;
    USE SIGNAL ;
    PORT
      LAYER M4 ;
        RECT  -0.042 68.688 0.042 68.712 ;
    END
  END n_p[180]
  PIN n_p[181]
    DIRECTION OUTPUT ;
    USE SIGNAL ;
    PORT
      LAYER M4 ;
        RECT  -0.042 68.784 0.042 68.808 ;
    END
  END n_p[181]
  PIN n_p[182]
    DIRECTION OUTPUT ;
    USE SIGNAL ;
    PORT
      LAYER M4 ;
        RECT  -0.042 68.88 0.042 68.904 ;
    END
  END n_p[182]
  PIN n_p[183]
    DIRECTION OUTPUT ;
    USE SIGNAL ;
    PORT
      LAYER M4 ;
        RECT  -0.042 68.976 0.042 69 ;
    END
  END n_p[183]
  PIN n_p[184]
    DIRECTION OUTPUT ;
    USE SIGNAL ;
    PORT
      LAYER M4 ;
        RECT  -0.042 69.072 0.042 69.096 ;
    END
  END n_p[184]
  PIN n_p[185]
    DIRECTION OUTPUT ;
    USE SIGNAL ;
    PORT
      LAYER M4 ;
        RECT  -0.042 69.168 0.042 69.192 ;
    END
  END n_p[185]
  PIN n_p[186]
    DIRECTION OUTPUT ;
    USE SIGNAL ;
    PORT
      LAYER M4 ;
        RECT  -0.042 69.264 0.042 69.288 ;
    END
  END n_p[186]
  PIN n_p[187]
    DIRECTION OUTPUT ;
    USE SIGNAL ;
    PORT
      LAYER M4 ;
        RECT  -0.042 69.36 0.042 69.384 ;
    END
  END n_p[187]
  PIN n_p[188]
    DIRECTION OUTPUT ;
    USE SIGNAL ;
    PORT
      LAYER M4 ;
        RECT  -0.042 69.456 0.042 69.48 ;
    END
  END n_p[188]
  PIN n_p[189]
    DIRECTION OUTPUT ;
    USE SIGNAL ;
    PORT
      LAYER M4 ;
        RECT  -0.042 69.552 0.042 69.576 ;
    END
  END n_p[189]
  PIN n_p[18]
    DIRECTION OUTPUT ;
    USE SIGNAL ;
    PORT
      LAYER M4 ;
        RECT  -0.042 53.136 0.042 53.16 ;
    END
  END n_p[18]
  PIN n_p[190]
    DIRECTION OUTPUT ;
    USE SIGNAL ;
    PORT
      LAYER M4 ;
        RECT  -0.042 69.648 0.042 69.672 ;
    END
  END n_p[190]
  PIN n_p[191]
    DIRECTION OUTPUT ;
    USE SIGNAL ;
    PORT
      LAYER M4 ;
        RECT  -0.042 69.744 0.042 69.768 ;
    END
  END n_p[191]
  PIN n_p[192]
    DIRECTION OUTPUT ;
    USE SIGNAL ;
    PORT
      LAYER M4 ;
        RECT  -0.042 69.84 0.042 69.864 ;
    END
  END n_p[192]
  PIN n_p[193]
    DIRECTION OUTPUT ;
    USE SIGNAL ;
    PORT
      LAYER M4 ;
        RECT  -0.042 69.936 0.042 69.96 ;
    END
  END n_p[193]
  PIN n_p[194]
    DIRECTION OUTPUT ;
    USE SIGNAL ;
    PORT
      LAYER M4 ;
        RECT  -0.042 70.032 0.042 70.056 ;
    END
  END n_p[194]
  PIN n_p[195]
    DIRECTION OUTPUT ;
    USE SIGNAL ;
    PORT
      LAYER M4 ;
        RECT  -0.042 70.128 0.042 70.152 ;
    END
  END n_p[195]
  PIN n_p[196]
    DIRECTION OUTPUT ;
    USE SIGNAL ;
    PORT
      LAYER M4 ;
        RECT  -0.042 70.224 0.042 70.248 ;
    END
  END n_p[196]
  PIN n_p[197]
    DIRECTION OUTPUT ;
    USE SIGNAL ;
    PORT
      LAYER M4 ;
        RECT  -0.042 70.32 0.042 70.344 ;
    END
  END n_p[197]
  PIN n_p[198]
    DIRECTION OUTPUT ;
    USE SIGNAL ;
    PORT
      LAYER M4 ;
        RECT  -0.042 70.416 0.042 70.44 ;
    END
  END n_p[198]
  PIN n_p[199]
    DIRECTION OUTPUT ;
    USE SIGNAL ;
    PORT
      LAYER M4 ;
        RECT  -0.042 70.512 0.042 70.536 ;
    END
  END n_p[199]
  PIN n_p[19]
    DIRECTION OUTPUT ;
    USE SIGNAL ;
    PORT
      LAYER M4 ;
        RECT  -0.042 53.232 0.042 53.256 ;
    END
  END n_p[19]
  PIN n_p[1]
    DIRECTION OUTPUT ;
    USE SIGNAL ;
    PORT
      LAYER M4 ;
        RECT  -0.042 51.504 0.042 51.528 ;
    END
  END n_p[1]
  PIN n_p[200]
    DIRECTION OUTPUT ;
    USE SIGNAL ;
    PORT
      LAYER M4 ;
        RECT  -0.042 70.608 0.042 70.632 ;
    END
  END n_p[200]
  PIN n_p[201]
    DIRECTION OUTPUT ;
    USE SIGNAL ;
    PORT
      LAYER M4 ;
        RECT  -0.042 70.704 0.042 70.728 ;
    END
  END n_p[201]
  PIN n_p[202]
    DIRECTION OUTPUT ;
    USE SIGNAL ;
    PORT
      LAYER M4 ;
        RECT  -0.042 70.8 0.042 70.824 ;
    END
  END n_p[202]
  PIN n_p[203]
    DIRECTION OUTPUT ;
    USE SIGNAL ;
    PORT
      LAYER M4 ;
        RECT  -0.042 70.896 0.042 70.92 ;
    END
  END n_p[203]
  PIN n_p[204]
    DIRECTION OUTPUT ;
    USE SIGNAL ;
    PORT
      LAYER M4 ;
        RECT  -0.042 70.992 0.042 71.016 ;
    END
  END n_p[204]
  PIN n_p[205]
    DIRECTION OUTPUT ;
    USE SIGNAL ;
    PORT
      LAYER M4 ;
        RECT  -0.042 71.088 0.042 71.112 ;
    END
  END n_p[205]
  PIN n_p[206]
    DIRECTION OUTPUT ;
    USE SIGNAL ;
    PORT
      LAYER M4 ;
        RECT  -0.042 71.184 0.042 71.208 ;
    END
  END n_p[206]
  PIN n_p[207]
    DIRECTION OUTPUT ;
    USE SIGNAL ;
    PORT
      LAYER M4 ;
        RECT  -0.042 71.28 0.042 71.304 ;
    END
  END n_p[207]
  PIN n_p[208]
    DIRECTION OUTPUT ;
    USE SIGNAL ;
    PORT
      LAYER M4 ;
        RECT  -0.042 71.376 0.042 71.4 ;
    END
  END n_p[208]
  PIN n_p[209]
    DIRECTION OUTPUT ;
    USE SIGNAL ;
    PORT
      LAYER M4 ;
        RECT  -0.042 71.472 0.042 71.496 ;
    END
  END n_p[209]
  PIN n_p[20]
    DIRECTION OUTPUT ;
    USE SIGNAL ;
    PORT
      LAYER M4 ;
        RECT  -0.042 53.328 0.042 53.352 ;
    END
  END n_p[20]
  PIN n_p[210]
    DIRECTION OUTPUT ;
    USE SIGNAL ;
    PORT
      LAYER M4 ;
        RECT  -0.042 71.568 0.042 71.592 ;
    END
  END n_p[210]
  PIN n_p[211]
    DIRECTION OUTPUT ;
    USE SIGNAL ;
    PORT
      LAYER M4 ;
        RECT  -0.042 71.664 0.042 71.688 ;
    END
  END n_p[211]
  PIN n_p[212]
    DIRECTION OUTPUT ;
    USE SIGNAL ;
    PORT
      LAYER M4 ;
        RECT  -0.042 71.76 0.042 71.784 ;
    END
  END n_p[212]
  PIN n_p[213]
    DIRECTION OUTPUT ;
    USE SIGNAL ;
    PORT
      LAYER M4 ;
        RECT  -0.042 71.856 0.042 71.88 ;
    END
  END n_p[213]
  PIN n_p[214]
    DIRECTION OUTPUT ;
    USE SIGNAL ;
    PORT
      LAYER M4 ;
        RECT  -0.042 71.952 0.042 71.976 ;
    END
  END n_p[214]
  PIN n_p[215]
    DIRECTION OUTPUT ;
    USE SIGNAL ;
    PORT
      LAYER M4 ;
        RECT  -0.042 72.048 0.042 72.072 ;
    END
  END n_p[215]
  PIN n_p[216]
    DIRECTION OUTPUT ;
    USE SIGNAL ;
    PORT
      LAYER M4 ;
        RECT  -0.042 72.144 0.042 72.168 ;
    END
  END n_p[216]
  PIN n_p[217]
    DIRECTION OUTPUT ;
    USE SIGNAL ;
    PORT
      LAYER M4 ;
        RECT  -0.042 72.24 0.042 72.264 ;
    END
  END n_p[217]
  PIN n_p[218]
    DIRECTION OUTPUT ;
    USE SIGNAL ;
    PORT
      LAYER M4 ;
        RECT  -0.042 72.336 0.042 72.36 ;
    END
  END n_p[218]
  PIN n_p[219]
    DIRECTION OUTPUT ;
    USE SIGNAL ;
    PORT
      LAYER M4 ;
        RECT  -0.042 72.432 0.042 72.456 ;
    END
  END n_p[219]
  PIN n_p[21]
    DIRECTION OUTPUT ;
    USE SIGNAL ;
    PORT
      LAYER M4 ;
        RECT  -0.042 53.424 0.042 53.448 ;
    END
  END n_p[21]
  PIN n_p[220]
    DIRECTION OUTPUT ;
    USE SIGNAL ;
    PORT
      LAYER M4 ;
        RECT  -0.042 72.528 0.042 72.552 ;
    END
  END n_p[220]
  PIN n_p[221]
    DIRECTION OUTPUT ;
    USE SIGNAL ;
    PORT
      LAYER M4 ;
        RECT  -0.042 72.624 0.042 72.648 ;
    END
  END n_p[221]
  PIN n_p[222]
    DIRECTION OUTPUT ;
    USE SIGNAL ;
    PORT
      LAYER M4 ;
        RECT  -0.042 72.72 0.042 72.744 ;
    END
  END n_p[222]
  PIN n_p[223]
    DIRECTION OUTPUT ;
    USE SIGNAL ;
    PORT
      LAYER M4 ;
        RECT  -0.042 72.816 0.042 72.84 ;
    END
  END n_p[223]
  PIN n_p[224]
    DIRECTION OUTPUT ;
    USE SIGNAL ;
    PORT
      LAYER M4 ;
        RECT  -0.042 72.912 0.042 72.936 ;
    END
  END n_p[224]
  PIN n_p[225]
    DIRECTION OUTPUT ;
    USE SIGNAL ;
    PORT
      LAYER M4 ;
        RECT  -0.042 73.008 0.042 73.032 ;
    END
  END n_p[225]
  PIN n_p[226]
    DIRECTION OUTPUT ;
    USE SIGNAL ;
    PORT
      LAYER M4 ;
        RECT  -0.042 73.104 0.042 73.128 ;
    END
  END n_p[226]
  PIN n_p[227]
    DIRECTION OUTPUT ;
    USE SIGNAL ;
    PORT
      LAYER M4 ;
        RECT  -0.042 73.2 0.042 73.224 ;
    END
  END n_p[227]
  PIN n_p[228]
    DIRECTION OUTPUT ;
    USE SIGNAL ;
    PORT
      LAYER M4 ;
        RECT  -0.042 73.296 0.042 73.32 ;
    END
  END n_p[228]
  PIN n_p[229]
    DIRECTION OUTPUT ;
    USE SIGNAL ;
    PORT
      LAYER M4 ;
        RECT  -0.042 73.392 0.042 73.416 ;
    END
  END n_p[229]
  PIN n_p[22]
    DIRECTION OUTPUT ;
    USE SIGNAL ;
    PORT
      LAYER M4 ;
        RECT  -0.042 53.52 0.042 53.544 ;
    END
  END n_p[22]
  PIN n_p[230]
    DIRECTION OUTPUT ;
    USE SIGNAL ;
    PORT
      LAYER M4 ;
        RECT  -0.042 73.488 0.042 73.512 ;
    END
  END n_p[230]
  PIN n_p[231]
    DIRECTION OUTPUT ;
    USE SIGNAL ;
    PORT
      LAYER M4 ;
        RECT  -0.042 73.584 0.042 73.608 ;
    END
  END n_p[231]
  PIN n_p[232]
    DIRECTION OUTPUT ;
    USE SIGNAL ;
    PORT
      LAYER M4 ;
        RECT  -0.042 73.68 0.042 73.704 ;
    END
  END n_p[232]
  PIN n_p[233]
    DIRECTION OUTPUT ;
    USE SIGNAL ;
    PORT
      LAYER M4 ;
        RECT  -0.042 73.776 0.042 73.8 ;
    END
  END n_p[233]
  PIN n_p[234]
    DIRECTION OUTPUT ;
    USE SIGNAL ;
    PORT
      LAYER M4 ;
        RECT  -0.042 73.872 0.042 73.896 ;
    END
  END n_p[234]
  PIN n_p[235]
    DIRECTION OUTPUT ;
    USE SIGNAL ;
    PORT
      LAYER M4 ;
        RECT  -0.042 73.968 0.042 73.992 ;
    END
  END n_p[235]
  PIN n_p[236]
    DIRECTION OUTPUT ;
    USE SIGNAL ;
    PORT
      LAYER M4 ;
        RECT  -0.042 74.064 0.042 74.088 ;
    END
  END n_p[236]
  PIN n_p[237]
    DIRECTION OUTPUT ;
    USE SIGNAL ;
    PORT
      LAYER M4 ;
        RECT  -0.042 74.16 0.042 74.184 ;
    END
  END n_p[237]
  PIN n_p[238]
    DIRECTION OUTPUT ;
    USE SIGNAL ;
    PORT
      LAYER M4 ;
        RECT  -0.042 74.256 0.042 74.28 ;
    END
  END n_p[238]
  PIN n_p[239]
    DIRECTION OUTPUT ;
    USE SIGNAL ;
    PORT
      LAYER M4 ;
        RECT  -0.042 74.352 0.042 74.376 ;
    END
  END n_p[239]
  PIN n_p[23]
    DIRECTION OUTPUT ;
    USE SIGNAL ;
    PORT
      LAYER M4 ;
        RECT  -0.042 53.616 0.042 53.64 ;
    END
  END n_p[23]
  PIN n_p[240]
    DIRECTION OUTPUT ;
    USE SIGNAL ;
    PORT
      LAYER M4 ;
        RECT  -0.042 74.448 0.042 74.472 ;
    END
  END n_p[240]
  PIN n_p[241]
    DIRECTION OUTPUT ;
    USE SIGNAL ;
    PORT
      LAYER M4 ;
        RECT  -0.042 74.544 0.042 74.568 ;
    END
  END n_p[241]
  PIN n_p[242]
    DIRECTION OUTPUT ;
    USE SIGNAL ;
    PORT
      LAYER M4 ;
        RECT  -0.042 74.64 0.042 74.664 ;
    END
  END n_p[242]
  PIN n_p[243]
    DIRECTION OUTPUT ;
    USE SIGNAL ;
    PORT
      LAYER M4 ;
        RECT  -0.042 74.736 0.042 74.76 ;
    END
  END n_p[243]
  PIN n_p[244]
    DIRECTION OUTPUT ;
    USE SIGNAL ;
    PORT
      LAYER M4 ;
        RECT  -0.042 74.832 0.042 74.856 ;
    END
  END n_p[244]
  PIN n_p[245]
    DIRECTION OUTPUT ;
    USE SIGNAL ;
    PORT
      LAYER M4 ;
        RECT  -0.042 74.928 0.042 74.952 ;
    END
  END n_p[245]
  PIN n_p[246]
    DIRECTION OUTPUT ;
    USE SIGNAL ;
    PORT
      LAYER M4 ;
        RECT  -0.042 75.024 0.042 75.048 ;
    END
  END n_p[246]
  PIN n_p[247]
    DIRECTION OUTPUT ;
    USE SIGNAL ;
    PORT
      LAYER M4 ;
        RECT  -0.042 75.12 0.042 75.144 ;
    END
  END n_p[247]
  PIN n_p[248]
    DIRECTION OUTPUT ;
    USE SIGNAL ;
    PORT
      LAYER M4 ;
        RECT  -0.042 75.216 0.042 75.24 ;
    END
  END n_p[248]
  PIN n_p[249]
    DIRECTION OUTPUT ;
    USE SIGNAL ;
    PORT
      LAYER M4 ;
        RECT  -0.042 75.312 0.042 75.336 ;
    END
  END n_p[249]
  PIN n_p[24]
    DIRECTION OUTPUT ;
    USE SIGNAL ;
    PORT
      LAYER M4 ;
        RECT  -0.042 53.712 0.042 53.736 ;
    END
  END n_p[24]
  PIN n_p[250]
    DIRECTION OUTPUT ;
    USE SIGNAL ;
    PORT
      LAYER M4 ;
        RECT  -0.042 75.408 0.042 75.432 ;
    END
  END n_p[250]
  PIN n_p[251]
    DIRECTION OUTPUT ;
    USE SIGNAL ;
    PORT
      LAYER M4 ;
        RECT  -0.042 75.504 0.042 75.528 ;
    END
  END n_p[251]
  PIN n_p[252]
    DIRECTION OUTPUT ;
    USE SIGNAL ;
    PORT
      LAYER M4 ;
        RECT  -0.042 75.6 0.042 75.624 ;
    END
  END n_p[252]
  PIN n_p[253]
    DIRECTION OUTPUT ;
    USE SIGNAL ;
    PORT
      LAYER M4 ;
        RECT  -0.042 75.696 0.042 75.72 ;
    END
  END n_p[253]
  PIN n_p[254]
    DIRECTION OUTPUT ;
    USE SIGNAL ;
    PORT
      LAYER M4 ;
        RECT  -0.042 75.792 0.042 75.816 ;
    END
  END n_p[254]
  PIN n_p[255]
    DIRECTION OUTPUT ;
    USE SIGNAL ;
    PORT
      LAYER M4 ;
        RECT  -0.042 75.888 0.042 75.912 ;
    END
  END n_p[255]
  PIN n_p[256]
    DIRECTION OUTPUT ;
    USE SIGNAL ;
    PORT
      LAYER M4 ;
        RECT  -0.042 75.984 0.042 76.008 ;
    END
  END n_p[256]
  PIN n_p[257]
    DIRECTION OUTPUT ;
    USE SIGNAL ;
    PORT
      LAYER M4 ;
        RECT  -0.042 76.08 0.042 76.104 ;
    END
  END n_p[257]
  PIN n_p[258]
    DIRECTION OUTPUT ;
    USE SIGNAL ;
    PORT
      LAYER M4 ;
        RECT  -0.042 76.176 0.042 76.2 ;
    END
  END n_p[258]
  PIN n_p[259]
    DIRECTION OUTPUT ;
    USE SIGNAL ;
    PORT
      LAYER M4 ;
        RECT  -0.042 76.272 0.042 76.296 ;
    END
  END n_p[259]
  PIN n_p[25]
    DIRECTION OUTPUT ;
    USE SIGNAL ;
    PORT
      LAYER M4 ;
        RECT  -0.042 53.808 0.042 53.832 ;
    END
  END n_p[25]
  PIN n_p[260]
    DIRECTION OUTPUT ;
    USE SIGNAL ;
    PORT
      LAYER M4 ;
        RECT  -0.042 76.368 0.042 76.392 ;
    END
  END n_p[260]
  PIN n_p[261]
    DIRECTION OUTPUT ;
    USE SIGNAL ;
    PORT
      LAYER M4 ;
        RECT  -0.042 76.464 0.042 76.488 ;
    END
  END n_p[261]
  PIN n_p[262]
    DIRECTION OUTPUT ;
    USE SIGNAL ;
    PORT
      LAYER M4 ;
        RECT  -0.042 76.56 0.042 76.584 ;
    END
  END n_p[262]
  PIN n_p[263]
    DIRECTION OUTPUT ;
    USE SIGNAL ;
    PORT
      LAYER M4 ;
        RECT  -0.042 76.656 0.042 76.68 ;
    END
  END n_p[263]
  PIN n_p[264]
    DIRECTION OUTPUT ;
    USE SIGNAL ;
    PORT
      LAYER M4 ;
        RECT  -0.042 76.752 0.042 76.776 ;
    END
  END n_p[264]
  PIN n_p[265]
    DIRECTION OUTPUT ;
    USE SIGNAL ;
    PORT
      LAYER M4 ;
        RECT  -0.042 76.848 0.042 76.872 ;
    END
  END n_p[265]
  PIN n_p[266]
    DIRECTION OUTPUT ;
    USE SIGNAL ;
    PORT
      LAYER M4 ;
        RECT  -0.042 76.944 0.042 76.968 ;
    END
  END n_p[266]
  PIN n_p[267]
    DIRECTION OUTPUT ;
    USE SIGNAL ;
    PORT
      LAYER M4 ;
        RECT  -0.042 77.04 0.042 77.064 ;
    END
  END n_p[267]
  PIN n_p[268]
    DIRECTION OUTPUT ;
    USE SIGNAL ;
    PORT
      LAYER M4 ;
        RECT  -0.042 77.136 0.042 77.16 ;
    END
  END n_p[268]
  PIN n_p[269]
    DIRECTION OUTPUT ;
    USE SIGNAL ;
    PORT
      LAYER M4 ;
        RECT  -0.042 77.232 0.042 77.256 ;
    END
  END n_p[269]
  PIN n_p[26]
    DIRECTION OUTPUT ;
    USE SIGNAL ;
    PORT
      LAYER M4 ;
        RECT  -0.042 53.904 0.042 53.928 ;
    END
  END n_p[26]
  PIN n_p[270]
    DIRECTION OUTPUT ;
    USE SIGNAL ;
    PORT
      LAYER M4 ;
        RECT  -0.042 77.328 0.042 77.352 ;
    END
  END n_p[270]
  PIN n_p[271]
    DIRECTION OUTPUT ;
    USE SIGNAL ;
    PORT
      LAYER M4 ;
        RECT  -0.042 77.424 0.042 77.448 ;
    END
  END n_p[271]
  PIN n_p[272]
    DIRECTION OUTPUT ;
    USE SIGNAL ;
    PORT
      LAYER M4 ;
        RECT  -0.042 77.52 0.042 77.544 ;
    END
  END n_p[272]
  PIN n_p[273]
    DIRECTION OUTPUT ;
    USE SIGNAL ;
    PORT
      LAYER M4 ;
        RECT  -0.042 77.616 0.042 77.64 ;
    END
  END n_p[273]
  PIN n_p[274]
    DIRECTION OUTPUT ;
    USE SIGNAL ;
    PORT
      LAYER M4 ;
        RECT  -0.042 77.712 0.042 77.736 ;
    END
  END n_p[274]
  PIN n_p[275]
    DIRECTION OUTPUT ;
    USE SIGNAL ;
    PORT
      LAYER M4 ;
        RECT  -0.042 77.808 0.042 77.832 ;
    END
  END n_p[275]
  PIN n_p[276]
    DIRECTION OUTPUT ;
    USE SIGNAL ;
    PORT
      LAYER M4 ;
        RECT  -0.042 77.904 0.042 77.928 ;
    END
  END n_p[276]
  PIN n_p[277]
    DIRECTION OUTPUT ;
    USE SIGNAL ;
    PORT
      LAYER M4 ;
        RECT  -0.042 78 0.042 78.024 ;
    END
  END n_p[277]
  PIN n_p[278]
    DIRECTION OUTPUT ;
    USE SIGNAL ;
    PORT
      LAYER M4 ;
        RECT  -0.042 78.096 0.042 78.12 ;
    END
  END n_p[278]
  PIN n_p[27]
    DIRECTION OUTPUT ;
    USE SIGNAL ;
    PORT
      LAYER M4 ;
        RECT  -0.042 54 0.042 54.024 ;
    END
  END n_p[27]
  PIN n_p[28]
    DIRECTION OUTPUT ;
    USE SIGNAL ;
    PORT
      LAYER M4 ;
        RECT  -0.042 54.096 0.042 54.12 ;
    END
  END n_p[28]
  PIN n_p[29]
    DIRECTION OUTPUT ;
    USE SIGNAL ;
    PORT
      LAYER M4 ;
        RECT  -0.042 54.192 0.042 54.216 ;
    END
  END n_p[29]
  PIN n_p[2]
    DIRECTION OUTPUT ;
    USE SIGNAL ;
    PORT
      LAYER M4 ;
        RECT  -0.042 51.6 0.042 51.624 ;
    END
  END n_p[2]
  PIN n_p[30]
    DIRECTION OUTPUT ;
    USE SIGNAL ;
    PORT
      LAYER M4 ;
        RECT  -0.042 54.288 0.042 54.312 ;
    END
  END n_p[30]
  PIN n_p[31]
    DIRECTION OUTPUT ;
    USE SIGNAL ;
    PORT
      LAYER M4 ;
        RECT  -0.042 54.384 0.042 54.408 ;
    END
  END n_p[31]
  PIN n_p[32]
    DIRECTION OUTPUT ;
    USE SIGNAL ;
    PORT
      LAYER M4 ;
        RECT  -0.042 54.48 0.042 54.504 ;
    END
  END n_p[32]
  PIN n_p[33]
    DIRECTION OUTPUT ;
    USE SIGNAL ;
    PORT
      LAYER M4 ;
        RECT  -0.042 54.576 0.042 54.6 ;
    END
  END n_p[33]
  PIN n_p[34]
    DIRECTION OUTPUT ;
    USE SIGNAL ;
    PORT
      LAYER M4 ;
        RECT  -0.042 54.672 0.042 54.696 ;
    END
  END n_p[34]
  PIN n_p[35]
    DIRECTION OUTPUT ;
    USE SIGNAL ;
    PORT
      LAYER M4 ;
        RECT  -0.042 54.768 0.042 54.792 ;
    END
  END n_p[35]
  PIN n_p[36]
    DIRECTION OUTPUT ;
    USE SIGNAL ;
    PORT
      LAYER M4 ;
        RECT  -0.042 54.864 0.042 54.888 ;
    END
  END n_p[36]
  PIN n_p[37]
    DIRECTION OUTPUT ;
    USE SIGNAL ;
    PORT
      LAYER M4 ;
        RECT  -0.042 54.96 0.042 54.984 ;
    END
  END n_p[37]
  PIN n_p[38]
    DIRECTION OUTPUT ;
    USE SIGNAL ;
    PORT
      LAYER M4 ;
        RECT  -0.042 55.056 0.042 55.08 ;
    END
  END n_p[38]
  PIN n_p[39]
    DIRECTION OUTPUT ;
    USE SIGNAL ;
    PORT
      LAYER M4 ;
        RECT  -0.042 55.152 0.042 55.176 ;
    END
  END n_p[39]
  PIN n_p[3]
    DIRECTION OUTPUT ;
    USE SIGNAL ;
    PORT
      LAYER M4 ;
        RECT  -0.042 51.696 0.042 51.72 ;
    END
  END n_p[3]
  PIN n_p[40]
    DIRECTION OUTPUT ;
    USE SIGNAL ;
    PORT
      LAYER M4 ;
        RECT  -0.042 55.248 0.042 55.272 ;
    END
  END n_p[40]
  PIN n_p[41]
    DIRECTION OUTPUT ;
    USE SIGNAL ;
    PORT
      LAYER M4 ;
        RECT  -0.042 55.344 0.042 55.368 ;
    END
  END n_p[41]
  PIN n_p[42]
    DIRECTION OUTPUT ;
    USE SIGNAL ;
    PORT
      LAYER M4 ;
        RECT  -0.042 55.44 0.042 55.464 ;
    END
  END n_p[42]
  PIN n_p[43]
    DIRECTION OUTPUT ;
    USE SIGNAL ;
    PORT
      LAYER M4 ;
        RECT  -0.042 55.536 0.042 55.56 ;
    END
  END n_p[43]
  PIN n_p[44]
    DIRECTION OUTPUT ;
    USE SIGNAL ;
    PORT
      LAYER M4 ;
        RECT  -0.042 55.632 0.042 55.656 ;
    END
  END n_p[44]
  PIN n_p[45]
    DIRECTION OUTPUT ;
    USE SIGNAL ;
    PORT
      LAYER M4 ;
        RECT  -0.042 55.728 0.042 55.752 ;
    END
  END n_p[45]
  PIN n_p[46]
    DIRECTION OUTPUT ;
    USE SIGNAL ;
    PORT
      LAYER M4 ;
        RECT  -0.042 55.824 0.042 55.848 ;
    END
  END n_p[46]
  PIN n_p[47]
    DIRECTION OUTPUT ;
    USE SIGNAL ;
    PORT
      LAYER M4 ;
        RECT  -0.042 55.92 0.042 55.944 ;
    END
  END n_p[47]
  PIN n_p[48]
    DIRECTION OUTPUT ;
    USE SIGNAL ;
    PORT
      LAYER M4 ;
        RECT  -0.042 56.016 0.042 56.04 ;
    END
  END n_p[48]
  PIN n_p[49]
    DIRECTION OUTPUT ;
    USE SIGNAL ;
    PORT
      LAYER M4 ;
        RECT  -0.042 56.112 0.042 56.136 ;
    END
  END n_p[49]
  PIN n_p[4]
    DIRECTION OUTPUT ;
    USE SIGNAL ;
    PORT
      LAYER M4 ;
        RECT  -0.042 51.792 0.042 51.816 ;
    END
  END n_p[4]
  PIN n_p[50]
    DIRECTION OUTPUT ;
    USE SIGNAL ;
    PORT
      LAYER M4 ;
        RECT  -0.042 56.208 0.042 56.232 ;
    END
  END n_p[50]
  PIN n_p[51]
    DIRECTION OUTPUT ;
    USE SIGNAL ;
    PORT
      LAYER M4 ;
        RECT  -0.042 56.304 0.042 56.328 ;
    END
  END n_p[51]
  PIN n_p[52]
    DIRECTION OUTPUT ;
    USE SIGNAL ;
    PORT
      LAYER M4 ;
        RECT  -0.042 56.4 0.042 56.424 ;
    END
  END n_p[52]
  PIN n_p[53]
    DIRECTION OUTPUT ;
    USE SIGNAL ;
    PORT
      LAYER M4 ;
        RECT  -0.042 56.496 0.042 56.52 ;
    END
  END n_p[53]
  PIN n_p[54]
    DIRECTION OUTPUT ;
    USE SIGNAL ;
    PORT
      LAYER M4 ;
        RECT  -0.042 56.592 0.042 56.616 ;
    END
  END n_p[54]
  PIN n_p[55]
    DIRECTION OUTPUT ;
    USE SIGNAL ;
    PORT
      LAYER M4 ;
        RECT  -0.042 56.688 0.042 56.712 ;
    END
  END n_p[55]
  PIN n_p[56]
    DIRECTION OUTPUT ;
    USE SIGNAL ;
    PORT
      LAYER M4 ;
        RECT  -0.042 56.784 0.042 56.808 ;
    END
  END n_p[56]
  PIN n_p[57]
    DIRECTION OUTPUT ;
    USE SIGNAL ;
    PORT
      LAYER M4 ;
        RECT  -0.042 56.88 0.042 56.904 ;
    END
  END n_p[57]
  PIN n_p[58]
    DIRECTION OUTPUT ;
    USE SIGNAL ;
    PORT
      LAYER M4 ;
        RECT  -0.042 56.976 0.042 57 ;
    END
  END n_p[58]
  PIN n_p[59]
    DIRECTION OUTPUT ;
    USE SIGNAL ;
    PORT
      LAYER M4 ;
        RECT  -0.042 57.072 0.042 57.096 ;
    END
  END n_p[59]
  PIN n_p[5]
    DIRECTION OUTPUT ;
    USE SIGNAL ;
    PORT
      LAYER M4 ;
        RECT  -0.042 51.888 0.042 51.912 ;
    END
  END n_p[5]
  PIN n_p[60]
    DIRECTION OUTPUT ;
    USE SIGNAL ;
    PORT
      LAYER M4 ;
        RECT  -0.042 57.168 0.042 57.192 ;
    END
  END n_p[60]
  PIN n_p[61]
    DIRECTION OUTPUT ;
    USE SIGNAL ;
    PORT
      LAYER M4 ;
        RECT  -0.042 57.264 0.042 57.288 ;
    END
  END n_p[61]
  PIN n_p[62]
    DIRECTION OUTPUT ;
    USE SIGNAL ;
    PORT
      LAYER M4 ;
        RECT  -0.042 57.36 0.042 57.384 ;
    END
  END n_p[62]
  PIN n_p[63]
    DIRECTION OUTPUT ;
    USE SIGNAL ;
    PORT
      LAYER M4 ;
        RECT  -0.042 57.456 0.042 57.48 ;
    END
  END n_p[63]
  PIN n_p[64]
    DIRECTION OUTPUT ;
    USE SIGNAL ;
    PORT
      LAYER M4 ;
        RECT  -0.042 57.552 0.042 57.576 ;
    END
  END n_p[64]
  PIN n_p[65]
    DIRECTION OUTPUT ;
    USE SIGNAL ;
    PORT
      LAYER M4 ;
        RECT  -0.042 57.648 0.042 57.672 ;
    END
  END n_p[65]
  PIN n_p[66]
    DIRECTION OUTPUT ;
    USE SIGNAL ;
    PORT
      LAYER M4 ;
        RECT  -0.042 57.744 0.042 57.768 ;
    END
  END n_p[66]
  PIN n_p[67]
    DIRECTION OUTPUT ;
    USE SIGNAL ;
    PORT
      LAYER M4 ;
        RECT  -0.042 57.84 0.042 57.864 ;
    END
  END n_p[67]
  PIN n_p[68]
    DIRECTION OUTPUT ;
    USE SIGNAL ;
    PORT
      LAYER M4 ;
        RECT  -0.042 57.936 0.042 57.96 ;
    END
  END n_p[68]
  PIN n_p[69]
    DIRECTION OUTPUT ;
    USE SIGNAL ;
    PORT
      LAYER M4 ;
        RECT  -0.042 58.032 0.042 58.056 ;
    END
  END n_p[69]
  PIN n_p[6]
    DIRECTION OUTPUT ;
    USE SIGNAL ;
    PORT
      LAYER M4 ;
        RECT  -0.042 51.984 0.042 52.008 ;
    END
  END n_p[6]
  PIN n_p[70]
    DIRECTION OUTPUT ;
    USE SIGNAL ;
    PORT
      LAYER M4 ;
        RECT  -0.042 58.128 0.042 58.152 ;
    END
  END n_p[70]
  PIN n_p[71]
    DIRECTION OUTPUT ;
    USE SIGNAL ;
    PORT
      LAYER M4 ;
        RECT  -0.042 58.224 0.042 58.248 ;
    END
  END n_p[71]
  PIN n_p[72]
    DIRECTION OUTPUT ;
    USE SIGNAL ;
    PORT
      LAYER M4 ;
        RECT  -0.042 58.32 0.042 58.344 ;
    END
  END n_p[72]
  PIN n_p[73]
    DIRECTION OUTPUT ;
    USE SIGNAL ;
    PORT
      LAYER M4 ;
        RECT  -0.042 58.416 0.042 58.44 ;
    END
  END n_p[73]
  PIN n_p[74]
    DIRECTION OUTPUT ;
    USE SIGNAL ;
    PORT
      LAYER M4 ;
        RECT  -0.042 58.512 0.042 58.536 ;
    END
  END n_p[74]
  PIN n_p[75]
    DIRECTION OUTPUT ;
    USE SIGNAL ;
    PORT
      LAYER M4 ;
        RECT  -0.042 58.608 0.042 58.632 ;
    END
  END n_p[75]
  PIN n_p[76]
    DIRECTION OUTPUT ;
    USE SIGNAL ;
    PORT
      LAYER M4 ;
        RECT  -0.042 58.704 0.042 58.728 ;
    END
  END n_p[76]
  PIN n_p[77]
    DIRECTION OUTPUT ;
    USE SIGNAL ;
    PORT
      LAYER M4 ;
        RECT  -0.042 58.8 0.042 58.824 ;
    END
  END n_p[77]
  PIN n_p[78]
    DIRECTION OUTPUT ;
    USE SIGNAL ;
    PORT
      LAYER M4 ;
        RECT  -0.042 58.896 0.042 58.92 ;
    END
  END n_p[78]
  PIN n_p[79]
    DIRECTION OUTPUT ;
    USE SIGNAL ;
    PORT
      LAYER M4 ;
        RECT  -0.042 58.992 0.042 59.016 ;
    END
  END n_p[79]
  PIN n_p[7]
    DIRECTION OUTPUT ;
    USE SIGNAL ;
    PORT
      LAYER M4 ;
        RECT  -0.042 52.08 0.042 52.104 ;
    END
  END n_p[7]
  PIN n_p[80]
    DIRECTION OUTPUT ;
    USE SIGNAL ;
    PORT
      LAYER M4 ;
        RECT  -0.042 59.088 0.042 59.112 ;
    END
  END n_p[80]
  PIN n_p[81]
    DIRECTION OUTPUT ;
    USE SIGNAL ;
    PORT
      LAYER M4 ;
        RECT  -0.042 59.184 0.042 59.208 ;
    END
  END n_p[81]
  PIN n_p[82]
    DIRECTION OUTPUT ;
    USE SIGNAL ;
    PORT
      LAYER M4 ;
        RECT  -0.042 59.28 0.042 59.304 ;
    END
  END n_p[82]
  PIN n_p[83]
    DIRECTION OUTPUT ;
    USE SIGNAL ;
    PORT
      LAYER M4 ;
        RECT  -0.042 59.376 0.042 59.4 ;
    END
  END n_p[83]
  PIN n_p[84]
    DIRECTION OUTPUT ;
    USE SIGNAL ;
    PORT
      LAYER M4 ;
        RECT  -0.042 59.472 0.042 59.496 ;
    END
  END n_p[84]
  PIN n_p[85]
    DIRECTION OUTPUT ;
    USE SIGNAL ;
    PORT
      LAYER M4 ;
        RECT  -0.042 59.568 0.042 59.592 ;
    END
  END n_p[85]
  PIN n_p[86]
    DIRECTION OUTPUT ;
    USE SIGNAL ;
    PORT
      LAYER M4 ;
        RECT  -0.042 59.664 0.042 59.688 ;
    END
  END n_p[86]
  PIN n_p[87]
    DIRECTION OUTPUT ;
    USE SIGNAL ;
    PORT
      LAYER M4 ;
        RECT  -0.042 59.76 0.042 59.784 ;
    END
  END n_p[87]
  PIN n_p[88]
    DIRECTION OUTPUT ;
    USE SIGNAL ;
    PORT
      LAYER M4 ;
        RECT  -0.042 59.856 0.042 59.88 ;
    END
  END n_p[88]
  PIN n_p[89]
    DIRECTION OUTPUT ;
    USE SIGNAL ;
    PORT
      LAYER M4 ;
        RECT  -0.042 59.952 0.042 59.976 ;
    END
  END n_p[89]
  PIN n_p[8]
    DIRECTION OUTPUT ;
    USE SIGNAL ;
    PORT
      LAYER M4 ;
        RECT  -0.042 52.176 0.042 52.2 ;
    END
  END n_p[8]
  PIN n_p[90]
    DIRECTION OUTPUT ;
    USE SIGNAL ;
    PORT
      LAYER M4 ;
        RECT  -0.042 60.048 0.042 60.072 ;
    END
  END n_p[90]
  PIN n_p[91]
    DIRECTION OUTPUT ;
    USE SIGNAL ;
    PORT
      LAYER M4 ;
        RECT  -0.042 60.144 0.042 60.168 ;
    END
  END n_p[91]
  PIN n_p[92]
    DIRECTION OUTPUT ;
    USE SIGNAL ;
    PORT
      LAYER M4 ;
        RECT  -0.042 60.24 0.042 60.264 ;
    END
  END n_p[92]
  PIN n_p[93]
    DIRECTION OUTPUT ;
    USE SIGNAL ;
    PORT
      LAYER M4 ;
        RECT  -0.042 60.336 0.042 60.36 ;
    END
  END n_p[93]
  PIN n_p[94]
    DIRECTION OUTPUT ;
    USE SIGNAL ;
    PORT
      LAYER M4 ;
        RECT  -0.042 60.432 0.042 60.456 ;
    END
  END n_p[94]
  PIN n_p[95]
    DIRECTION OUTPUT ;
    USE SIGNAL ;
    PORT
      LAYER M4 ;
        RECT  -0.042 60.528 0.042 60.552 ;
    END
  END n_p[95]
  PIN n_p[96]
    DIRECTION OUTPUT ;
    USE SIGNAL ;
    PORT
      LAYER M4 ;
        RECT  -0.042 60.624 0.042 60.648 ;
    END
  END n_p[96]
  PIN n_p[97]
    DIRECTION OUTPUT ;
    USE SIGNAL ;
    PORT
      LAYER M4 ;
        RECT  -0.042 60.72 0.042 60.744 ;
    END
  END n_p[97]
  PIN n_p[98]
    DIRECTION OUTPUT ;
    USE SIGNAL ;
    PORT
      LAYER M4 ;
        RECT  -0.042 60.816 0.042 60.84 ;
    END
  END n_p[98]
  PIN n_p[99]
    DIRECTION OUTPUT ;
    USE SIGNAL ;
    PORT
      LAYER M4 ;
        RECT  -0.042 60.912 0.042 60.936 ;
    END
  END n_p[99]
  PIN n_p[9]
    DIRECTION OUTPUT ;
    USE SIGNAL ;
    PORT
      LAYER M4 ;
        RECT  -0.042 52.272 0.042 52.296 ;
    END
  END n_p[9]
  PIN n_v
    DIRECTION OUTPUT ;
    USE SIGNAL ;
    PORT
      LAYER M4 ;
        RECT  -0.042 86.4 0.042 86.424 ;
    END
    PORT
      LAYER M4 ;
        RECT  0.012 86.4 2.408 86.424 ;
    END
  END n_v
  PIN rn
    DIRECTION INPUT ;
    USE SIGNAL ;
    PORT
      LAYER M4 ;
        RECT  -0.042 109.44 0.042 109.464 ;
    END
    PORT
      LAYER M4 ;
        RECT  0.012 109.44 2.408 109.464 ;
    END
  END rn
  PIN VDD
    DIRECTION INOUT ;
    USE POWER ;
    PORT
      LAYER M5 ;
        RECT  83.592 2.151 83.712 127.449 ;
        RECT  78.192 2.151 78.312 127.449 ;
        RECT  72.792 2.151 72.912 127.449 ;
        RECT  67.392 2.151 67.512 127.449 ;
        RECT  61.992 2.151 62.112 127.449 ;
        RECT  56.592 2.151 56.712 127.449 ;
        RECT  51.192 2.151 51.312 127.449 ;
        RECT  45.792 2.151 45.912 127.449 ;
        RECT  40.392 2.151 40.512 127.449 ;
        RECT  34.992 2.151 35.112 127.449 ;
        RECT  29.592 2.151 29.712 127.449 ;
        RECT  24.192 2.151 24.312 127.449 ;
        RECT  18.792 2.151 18.912 127.449 ;
        RECT  13.392 2.151 13.512 127.449 ;
        RECT  7.992 2.151 8.112 127.449 ;
        RECT  2.592 2.151 2.712 127.449 ;
    END
  END VDD
  PIN VSS
    DIRECTION INOUT ;
    USE GROUND ;
    PORT
      LAYER M5 ;
        RECT  83.4 2.137 83.52 127.463 ;
        RECT  78 2.137 78.12 127.463 ;
        RECT  72.6 2.137 72.72 127.463 ;
        RECT  67.2 2.137 67.32 127.463 ;
        RECT  61.8 2.137 61.92 127.463 ;
        RECT  56.4 2.137 56.52 127.463 ;
        RECT  51 2.137 51.12 127.463 ;
        RECT  45.6 2.137 45.72 127.463 ;
        RECT  40.2 2.137 40.32 127.463 ;
        RECT  34.8 2.137 34.92 127.463 ;
        RECT  29.4 2.137 29.52 127.463 ;
        RECT  24 2.137 24.12 127.463 ;
        RECT  18.6 2.137 18.72 127.463 ;
        RECT  13.2 2.137 13.32 127.463 ;
        RECT  7.8 2.137 7.92 127.463 ;
        RECT  2.4 2.137 2.52 127.463 ;
    END
  END VSS
  # OT_OBS_CLOSED layer=M5 d_um=1.536 added=8
  OBS
    LAYER RVTN ;
     RECT  2.16 2.16 84.24 2.295 ;
     RECT  2.16 2.565 84.24 2.835 ;
     RECT  2.16 3.105 84.24 3.375 ;
     RECT  2.16 3.645 84.24 3.915 ;
     RECT  2.16 4.185 84.24 4.455 ;
     RECT  2.16 4.725 84.24 4.995 ;
     RECT  2.16 5.265 84.24 5.535 ;
     RECT  2.16 5.805 84.24 6.075 ;
     RECT  2.16 6.345 84.24 6.615 ;
     RECT  2.16 6.885 84.24 7.155 ;
     RECT  2.16 7.425 84.24 7.695 ;
     RECT  2.16 7.965 84.24 8.235 ;
     RECT  2.16 8.505 84.24 8.775 ;
     RECT  2.16 9.045 84.24 9.315 ;
     RECT  2.16 9.585 84.24 9.855 ;
     RECT  2.16 10.125 84.24 10.395 ;
     RECT  2.16 10.665 84.24 10.935 ;
     RECT  2.16 11.205 84.24 11.475 ;
     RECT  2.16 11.745 84.24 12.015 ;
     RECT  2.16 12.285 84.24 12.555 ;
     RECT  2.16 12.825 84.24 13.095 ;
     RECT  2.16 13.365 84.24 13.635 ;
     RECT  2.16 13.905 84.24 14.175 ;
     RECT  2.16 14.445 84.24 14.715 ;
     RECT  2.16 14.985 84.24 15.255 ;
     RECT  2.16 15.525 84.24 15.795 ;
     RECT  2.16 16.065 84.24 16.335 ;
     RECT  2.16 16.605 84.24 16.875 ;
     RECT  2.16 17.145 84.24 17.415 ;
     RECT  2.16 17.685 84.24 17.955 ;
     RECT  2.16 18.225 84.24 18.495 ;
     RECT  2.16 18.765 84.24 19.035 ;
     RECT  2.16 19.305 84.24 19.575 ;
     RECT  2.16 19.845 84.24 20.115 ;
     RECT  2.16 20.385 84.24 20.655 ;
     RECT  2.16 20.925 84.24 21.195 ;
     RECT  2.16 21.465 84.24 21.735 ;
     RECT  2.16 22.005 84.24 22.275 ;
     RECT  2.16 22.545 84.24 22.815 ;
     RECT  2.16 23.085 84.24 23.355 ;
     RECT  2.16 23.625 84.24 23.895 ;
     RECT  2.16 24.165 84.24 24.435 ;
     RECT  2.16 24.705 84.24 24.975 ;
     RECT  2.16 25.245 84.24 25.515 ;
     RECT  2.16 25.785 84.24 26.055 ;
     RECT  2.16 26.325 84.24 26.595 ;
     RECT  2.16 26.865 84.24 27.135 ;
     RECT  2.16 27.405 84.24 27.675 ;
     RECT  2.16 27.945 84.24 28.215 ;
     RECT  2.16 28.485 84.24 28.755 ;
     RECT  2.16 29.025 84.24 29.295 ;
     RECT  2.16 29.565 84.24 29.835 ;
     RECT  2.16 30.105 84.24 30.375 ;
     RECT  2.16 30.645 84.24 30.915 ;
     RECT  2.16 31.185 84.24 31.455 ;
     RECT  2.16 31.725 84.24 31.995 ;
     RECT  2.16 32.265 84.24 32.535 ;
     RECT  2.16 32.805 84.24 33.075 ;
     RECT  2.16 33.345 84.24 33.615 ;
     RECT  2.16 33.885 84.24 34.155 ;
     RECT  2.16 34.425 84.24 34.695 ;
     RECT  2.16 34.965 84.24 35.235 ;
     RECT  2.16 35.505 84.24 35.775 ;
     RECT  2.16 36.045 84.24 36.315 ;
     RECT  2.16 36.585 84.24 36.855 ;
     RECT  2.16 37.125 84.24 37.395 ;
     RECT  2.16 37.665 84.24 37.935 ;
     RECT  2.16 38.205 84.24 38.475 ;
     RECT  2.16 38.745 84.24 39.015 ;
     RECT  2.16 39.285 84.24 39.555 ;
     RECT  2.16 39.825 84.24 40.095 ;
     RECT  2.16 40.365 84.24 40.635 ;
     RECT  2.16 40.905 84.24 41.175 ;
     RECT  2.16 41.445 84.24 41.715 ;
     RECT  2.16 41.985 84.24 42.255 ;
     RECT  2.16 42.525 84.24 42.795 ;
     RECT  2.16 43.065 84.24 43.335 ;
     RECT  2.16 43.605 84.24 43.875 ;
     RECT  2.16 44.145 84.24 44.415 ;
     RECT  2.16 44.685 84.24 44.955 ;
     RECT  2.16 45.225 84.24 45.495 ;
     RECT  2.16 45.765 84.24 46.035 ;
     RECT  2.16 46.305 84.24 46.575 ;
     RECT  2.16 46.845 84.24 47.115 ;
     RECT  2.16 47.385 84.24 47.655 ;
     RECT  2.16 47.925 84.24 48.195 ;
     RECT  2.16 48.465 84.24 48.735 ;
     RECT  2.16 49.005 84.24 49.275 ;
     RECT  2.16 49.545 84.24 49.815 ;
     RECT  2.16 50.085 84.24 50.355 ;
     RECT  2.16 50.625 84.24 50.895 ;
     RECT  2.16 51.165 84.24 51.435 ;
     RECT  2.16 51.705 84.24 51.975 ;
     RECT  2.16 52.245 84.24 52.515 ;
     RECT  2.16 52.785 84.24 53.055 ;
     RECT  2.16 53.325 84.24 53.595 ;
     RECT  2.16 53.865 84.24 54.135 ;
     RECT  2.16 54.405 84.24 54.675 ;
     RECT  2.16 54.945 84.24 55.215 ;
     RECT  2.16 55.485 84.24 55.755 ;
     RECT  2.16 56.025 84.24 56.295 ;
     RECT  2.16 56.565 84.24 56.835 ;
     RECT  2.16 57.105 84.24 57.375 ;
     RECT  2.16 57.645 84.24 57.915 ;
     RECT  2.16 58.185 84.24 58.455 ;
     RECT  2.16 58.725 84.24 58.995 ;
     RECT  2.16 59.265 84.24 59.535 ;
     RECT  2.16 59.805 84.24 60.075 ;
     RECT  2.16 60.345 84.24 60.615 ;
     RECT  2.16 60.885 84.24 61.155 ;
     RECT  2.16 61.425 84.24 61.695 ;
     RECT  2.16 61.965 84.24 62.235 ;
     RECT  2.16 62.505 84.24 62.775 ;
     RECT  2.16 63.045 84.24 63.315 ;
     RECT  2.16 63.585 84.24 63.855 ;
     RECT  2.16 64.125 84.24 64.395 ;
     RECT  2.16 64.665 84.24 64.935 ;
     RECT  2.16 65.205 84.24 65.475 ;
     RECT  2.16 65.745 84.24 66.015 ;
     RECT  2.16 66.285 84.24 66.555 ;
     RECT  2.16 66.825 84.24 67.095 ;
     RECT  2.16 67.365 84.24 67.635 ;
     RECT  2.16 67.905 84.24 68.175 ;
     RECT  2.16 68.445 84.24 68.715 ;
     RECT  2.16 68.985 84.24 69.255 ;
     RECT  2.16 69.525 84.24 69.795 ;
     RECT  2.16 70.065 84.24 70.335 ;
     RECT  2.16 70.605 84.24 70.875 ;
     RECT  2.16 71.145 84.24 71.415 ;
     RECT  2.16 71.685 84.24 71.955 ;
     RECT  2.16 72.225 84.24 72.495 ;
     RECT  2.16 72.765 84.24 73.035 ;
     RECT  2.16 73.305 84.24 73.575 ;
     RECT  2.16 73.845 84.24 74.115 ;
     RECT  2.16 74.385 84.24 74.655 ;
     RECT  2.16 74.925 84.24 75.195 ;
     RECT  2.16 75.465 84.24 75.735 ;
     RECT  2.16 76.005 84.24 76.275 ;
     RECT  2.16 76.545 84.24 76.815 ;
     RECT  2.16 77.085 84.24 77.355 ;
     RECT  2.16 77.625 84.24 77.895 ;
     RECT  2.16 78.165 84.24 78.435 ;
     RECT  2.16 78.705 84.24 78.975 ;
     RECT  2.16 79.245 84.24 79.515 ;
     RECT  2.16 79.785 84.24 80.055 ;
     RECT  2.16 80.325 84.24 80.595 ;
     RECT  2.16 80.865 84.24 81.135 ;
     RECT  2.16 81.405 84.24 81.675 ;
     RECT  2.16 81.945 84.24 82.215 ;
     RECT  2.16 82.485 84.24 82.755 ;
     RECT  2.16 83.025 84.24 83.295 ;
     RECT  2.16 83.565 84.24 83.835 ;
     RECT  2.16 84.105 84.24 84.375 ;
     RECT  2.16 84.645 84.24 84.915 ;
     RECT  2.16 85.185 84.24 85.455 ;
     RECT  2.16 85.725 84.24 85.995 ;
     RECT  2.16 86.265 84.24 86.535 ;
     RECT  2.16 86.805 84.24 87.075 ;
     RECT  2.16 87.345 84.24 87.615 ;
     RECT  2.16 87.885 84.24 88.155 ;
     RECT  2.16 88.425 84.24 88.695 ;
     RECT  2.16 88.965 84.24 89.235 ;
     RECT  2.16 89.505 84.24 89.775 ;
     RECT  2.16 90.045 84.24 90.315 ;
     RECT  2.16 90.585 84.24 90.855 ;
     RECT  2.16 91.125 84.24 91.395 ;
     RECT  2.16 91.665 84.24 91.935 ;
     RECT  2.16 92.205 84.24 92.475 ;
     RECT  2.16 92.745 84.24 93.015 ;
     RECT  2.16 93.285 84.24 93.555 ;
     RECT  2.16 93.825 84.24 94.095 ;
     RECT  2.16 94.365 84.24 94.635 ;
     RECT  2.16 94.905 84.24 95.175 ;
     RECT  2.16 95.445 84.24 95.715 ;
     RECT  2.16 95.985 84.24 96.255 ;
     RECT  2.16 96.525 84.24 96.795 ;
     RECT  2.16 97.065 84.24 97.335 ;
     RECT  2.16 97.605 84.24 97.875 ;
     RECT  2.16 98.145 84.24 98.415 ;
     RECT  2.16 98.685 84.24 98.955 ;
     RECT  2.16 99.225 84.24 99.495 ;
     RECT  2.16 99.765 84.24 100.035 ;
     RECT  2.16 100.305 84.24 100.575 ;
     RECT  2.16 100.845 84.24 101.115 ;
     RECT  2.16 101.385 84.24 101.655 ;
     RECT  2.16 101.925 84.24 102.195 ;
     RECT  2.16 102.465 84.24 102.735 ;
     RECT  2.16 103.005 84.24 103.275 ;
     RECT  2.16 103.545 84.24 103.815 ;
     RECT  2.16 104.085 84.24 104.355 ;
     RECT  2.16 104.625 84.24 104.895 ;
     RECT  2.16 105.165 84.24 105.435 ;
     RECT  2.16 105.705 84.24 105.975 ;
     RECT  2.16 106.245 84.24 106.515 ;
     RECT  2.16 106.785 84.24 107.055 ;
     RECT  2.16 107.325 84.24 107.595 ;
     RECT  2.16 107.865 84.24 108.135 ;
     RECT  2.16 108.405 84.24 108.675 ;
     RECT  2.16 108.945 84.24 109.215 ;
     RECT  2.16 109.485 84.24 109.755 ;
     RECT  2.16 110.025 84.24 110.295 ;
     RECT  2.16 110.565 84.24 110.835 ;
     RECT  2.16 111.105 84.24 111.375 ;
     RECT  2.16 111.645 84.24 111.915 ;
     RECT  2.16 112.185 84.24 112.455 ;
     RECT  2.16 112.725 84.24 112.995 ;
     RECT  2.16 113.265 84.24 113.535 ;
     RECT  2.16 113.805 84.24 114.075 ;
     RECT  2.16 114.345 84.24 114.615 ;
     RECT  2.16 114.885 84.24 115.155 ;
     RECT  2.16 115.425 84.24 115.695 ;
     RECT  2.16 115.965 84.24 116.235 ;
     RECT  2.16 116.505 84.24 116.775 ;
     RECT  2.16 117.045 84.24 117.315 ;
     RECT  2.16 117.585 84.24 117.855 ;
     RECT  2.16 118.125 84.24 118.395 ;
     RECT  2.16 118.665 84.24 118.935 ;
     RECT  2.16 119.205 84.24 119.475 ;
     RECT  2.16 119.745 84.24 120.015 ;
     RECT  2.16 120.285 84.24 120.555 ;
     RECT  2.16 120.825 84.24 121.095 ;
     RECT  2.16 121.365 84.24 121.635 ;
     RECT  2.16 121.905 84.24 122.175 ;
     RECT  2.16 122.445 84.24 122.715 ;
     RECT  2.16 122.985 84.24 123.255 ;
     RECT  2.16 123.525 84.24 123.795 ;
     RECT  2.16 124.065 84.24 124.335 ;
     RECT  2.16 124.605 84.24 124.875 ;
     RECT  2.16 125.145 84.24 125.415 ;
     RECT  2.16 125.685 84.24 125.955 ;
     RECT  2.16 126.225 84.24 126.495 ;
     RECT  2.16 126.765 84.24 127.035 ;
     RECT  2.16 127.305 84.24 127.44 ;
    LAYER RVTP ;
     RECT  2.16 2.295 84.24 2.565 ;
     RECT  2.16 2.835 84.24 3.105 ;
     RECT  2.16 3.375 84.24 3.645 ;
     RECT  2.16 3.915 84.24 4.185 ;
     RECT  2.16 4.455 84.24 4.725 ;
     RECT  2.16 4.995 84.24 5.265 ;
     RECT  2.16 5.535 84.24 5.805 ;
     RECT  2.16 6.075 84.24 6.345 ;
     RECT  2.16 6.615 84.24 6.885 ;
     RECT  2.16 7.155 84.24 7.425 ;
     RECT  2.16 7.695 84.24 7.965 ;
     RECT  2.16 8.235 84.24 8.505 ;
     RECT  2.16 8.775 84.24 9.045 ;
     RECT  2.16 9.315 84.24 9.585 ;
     RECT  2.16 9.855 84.24 10.125 ;
     RECT  2.16 10.395 84.24 10.665 ;
     RECT  2.16 10.935 84.24 11.205 ;
     RECT  2.16 11.475 84.24 11.745 ;
     RECT  2.16 12.015 84.24 12.285 ;
     RECT  2.16 12.555 84.24 12.825 ;
     RECT  2.16 13.095 84.24 13.365 ;
     RECT  2.16 13.635 84.24 13.905 ;
     RECT  2.16 14.175 84.24 14.445 ;
     RECT  2.16 14.715 84.24 14.985 ;
     RECT  2.16 15.255 84.24 15.525 ;
     RECT  2.16 15.795 84.24 16.065 ;
     RECT  2.16 16.335 84.24 16.605 ;
     RECT  2.16 16.875 84.24 17.145 ;
     RECT  2.16 17.415 84.24 17.685 ;
     RECT  2.16 17.955 84.24 18.225 ;
     RECT  2.16 18.495 84.24 18.765 ;
     RECT  2.16 19.035 84.24 19.305 ;
     RECT  2.16 19.575 84.24 19.845 ;
     RECT  2.16 20.115 84.24 20.385 ;
     RECT  2.16 20.655 84.24 20.925 ;
     RECT  2.16 21.195 84.24 21.465 ;
     RECT  2.16 21.735 84.24 22.005 ;
     RECT  2.16 22.275 84.24 22.545 ;
     RECT  2.16 22.815 84.24 23.085 ;
     RECT  2.16 23.355 84.24 23.625 ;
     RECT  2.16 23.895 84.24 24.165 ;
     RECT  2.16 24.435 84.24 24.705 ;
     RECT  2.16 24.975 84.24 25.245 ;
     RECT  2.16 25.515 84.24 25.785 ;
     RECT  2.16 26.055 84.24 26.325 ;
     RECT  2.16 26.595 84.24 26.865 ;
     RECT  2.16 27.135 84.24 27.405 ;
     RECT  2.16 27.675 84.24 27.945 ;
     RECT  2.16 28.215 84.24 28.485 ;
     RECT  2.16 28.755 84.24 29.025 ;
     RECT  2.16 29.295 84.24 29.565 ;
     RECT  2.16 29.835 84.24 30.105 ;
     RECT  2.16 30.375 84.24 30.645 ;
     RECT  2.16 30.915 84.24 31.185 ;
     RECT  2.16 31.455 84.24 31.725 ;
     RECT  2.16 31.995 84.24 32.265 ;
     RECT  2.16 32.535 84.24 32.805 ;
     RECT  2.16 33.075 84.24 33.345 ;
     RECT  2.16 33.615 84.24 33.885 ;
     RECT  2.16 34.155 84.24 34.425 ;
     RECT  2.16 34.695 84.24 34.965 ;
     RECT  2.16 35.235 84.24 35.505 ;
     RECT  2.16 35.775 84.24 36.045 ;
     RECT  2.16 36.315 84.24 36.585 ;
     RECT  2.16 36.855 84.24 37.125 ;
     RECT  2.16 37.395 84.24 37.665 ;
     RECT  2.16 37.935 84.24 38.205 ;
     RECT  2.16 38.475 84.24 38.745 ;
     RECT  2.16 39.015 84.24 39.285 ;
     RECT  2.16 39.555 84.24 39.825 ;
     RECT  2.16 40.095 84.24 40.365 ;
     RECT  2.16 40.635 84.24 40.905 ;
     RECT  2.16 41.175 84.24 41.445 ;
     RECT  2.16 41.715 84.24 41.985 ;
     RECT  2.16 42.255 84.24 42.525 ;
     RECT  2.16 42.795 84.24 43.065 ;
     RECT  2.16 43.335 84.24 43.605 ;
     RECT  2.16 43.875 84.24 44.145 ;
     RECT  2.16 44.415 84.24 44.685 ;
     RECT  2.16 44.955 84.24 45.225 ;
     RECT  2.16 45.495 84.24 45.765 ;
     RECT  2.16 46.035 84.24 46.305 ;
     RECT  2.16 46.575 84.24 46.845 ;
     RECT  2.16 47.115 84.24 47.385 ;
     RECT  2.16 47.655 84.24 47.925 ;
     RECT  2.16 48.195 84.24 48.465 ;
     RECT  2.16 48.735 84.24 49.005 ;
     RECT  2.16 49.275 84.24 49.545 ;
     RECT  2.16 49.815 84.24 50.085 ;
     RECT  2.16 50.355 84.24 50.625 ;
     RECT  2.16 50.895 84.24 51.165 ;
     RECT  2.16 51.435 84.24 51.705 ;
     RECT  2.16 51.975 84.24 52.245 ;
     RECT  2.16 52.515 84.24 52.785 ;
     RECT  2.16 53.055 84.24 53.325 ;
     RECT  2.16 53.595 84.24 53.865 ;
     RECT  2.16 54.135 84.24 54.405 ;
     RECT  2.16 54.675 84.24 54.945 ;
     RECT  2.16 55.215 84.24 55.485 ;
     RECT  2.16 55.755 84.24 56.025 ;
     RECT  2.16 56.295 84.24 56.565 ;
     RECT  2.16 56.835 84.24 57.105 ;
     RECT  2.16 57.375 84.24 57.645 ;
     RECT  2.16 57.915 84.24 58.185 ;
     RECT  2.16 58.455 84.24 58.725 ;
     RECT  2.16 58.995 84.24 59.265 ;
     RECT  2.16 59.535 84.24 59.805 ;
     RECT  2.16 60.075 84.24 60.345 ;
     RECT  2.16 60.615 84.24 60.885 ;
     RECT  2.16 61.155 84.24 61.425 ;
     RECT  2.16 61.695 84.24 61.965 ;
     RECT  2.16 62.235 84.24 62.505 ;
     RECT  2.16 62.775 84.24 63.045 ;
     RECT  2.16 63.315 84.24 63.585 ;
     RECT  2.16 63.855 84.24 64.125 ;
     RECT  2.16 64.395 84.24 64.665 ;
     RECT  2.16 64.935 84.24 65.205 ;
     RECT  2.16 65.475 84.24 65.745 ;
     RECT  2.16 66.015 84.24 66.285 ;
     RECT  2.16 66.555 84.24 66.825 ;
     RECT  2.16 67.095 84.24 67.365 ;
     RECT  2.16 67.635 84.24 67.905 ;
     RECT  2.16 68.175 84.24 68.445 ;
     RECT  2.16 68.715 84.24 68.985 ;
     RECT  2.16 69.255 84.24 69.525 ;
     RECT  2.16 69.795 84.24 70.065 ;
     RECT  2.16 70.335 84.24 70.605 ;
     RECT  2.16 70.875 84.24 71.145 ;
     RECT  2.16 71.415 84.24 71.685 ;
     RECT  2.16 71.955 84.24 72.225 ;
     RECT  2.16 72.495 84.24 72.765 ;
     RECT  2.16 73.035 84.24 73.305 ;
     RECT  2.16 73.575 84.24 73.845 ;
     RECT  2.16 74.115 84.24 74.385 ;
     RECT  2.16 74.655 84.24 74.925 ;
     RECT  2.16 75.195 84.24 75.465 ;
     RECT  2.16 75.735 84.24 76.005 ;
     RECT  2.16 76.275 84.24 76.545 ;
     RECT  2.16 76.815 84.24 77.085 ;
     RECT  2.16 77.355 84.24 77.625 ;
     RECT  2.16 77.895 84.24 78.165 ;
     RECT  2.16 78.435 84.24 78.705 ;
     RECT  2.16 78.975 84.24 79.245 ;
     RECT  2.16 79.515 84.24 79.785 ;
     RECT  2.16 80.055 84.24 80.325 ;
     RECT  2.16 80.595 84.24 80.865 ;
     RECT  2.16 81.135 84.24 81.405 ;
     RECT  2.16 81.675 84.24 81.945 ;
     RECT  2.16 82.215 84.24 82.485 ;
     RECT  2.16 82.755 84.24 83.025 ;
     RECT  2.16 83.295 84.24 83.565 ;
     RECT  2.16 83.835 84.24 84.105 ;
     RECT  2.16 84.375 84.24 84.645 ;
     RECT  2.16 84.915 84.24 85.185 ;
     RECT  2.16 85.455 84.24 85.725 ;
     RECT  2.16 85.995 84.24 86.265 ;
     RECT  2.16 86.535 84.24 86.805 ;
     RECT  2.16 87.075 84.24 87.345 ;
     RECT  2.16 87.615 84.24 87.885 ;
     RECT  2.16 88.155 84.24 88.425 ;
     RECT  2.16 88.695 84.24 88.965 ;
     RECT  2.16 89.235 84.24 89.505 ;
     RECT  2.16 89.775 84.24 90.045 ;
     RECT  2.16 90.315 84.24 90.585 ;
     RECT  2.16 90.855 84.24 91.125 ;
     RECT  2.16 91.395 84.24 91.665 ;
     RECT  2.16 91.935 84.24 92.205 ;
     RECT  2.16 92.475 84.24 92.745 ;
     RECT  2.16 93.015 84.24 93.285 ;
     RECT  2.16 93.555 84.24 93.825 ;
     RECT  2.16 94.095 84.24 94.365 ;
     RECT  2.16 94.635 84.24 94.905 ;
     RECT  2.16 95.175 84.24 95.445 ;
     RECT  2.16 95.715 84.24 95.985 ;
     RECT  2.16 96.255 84.24 96.525 ;
     RECT  2.16 96.795 84.24 97.065 ;
     RECT  2.16 97.335 84.24 97.605 ;
     RECT  2.16 97.875 84.24 98.145 ;
     RECT  2.16 98.415 84.24 98.685 ;
     RECT  2.16 98.955 84.24 99.225 ;
     RECT  2.16 99.495 84.24 99.765 ;
     RECT  2.16 100.035 84.24 100.305 ;
     RECT  2.16 100.575 84.24 100.845 ;
     RECT  2.16 101.115 84.24 101.385 ;
     RECT  2.16 101.655 84.24 101.925 ;
     RECT  2.16 102.195 84.24 102.465 ;
     RECT  2.16 102.735 84.24 103.005 ;
     RECT  2.16 103.275 84.24 103.545 ;
     RECT  2.16 103.815 84.24 104.085 ;
     RECT  2.16 104.355 84.24 104.625 ;
     RECT  2.16 104.895 84.24 105.165 ;
     RECT  2.16 105.435 84.24 105.705 ;
     RECT  2.16 105.975 84.24 106.245 ;
     RECT  2.16 106.515 84.24 106.785 ;
     RECT  2.16 107.055 84.24 107.325 ;
     RECT  2.16 107.595 84.24 107.865 ;
     RECT  2.16 108.135 84.24 108.405 ;
     RECT  2.16 108.675 84.24 108.945 ;
     RECT  2.16 109.215 84.24 109.485 ;
     RECT  2.16 109.755 84.24 110.025 ;
     RECT  2.16 110.295 84.24 110.565 ;
     RECT  2.16 110.835 84.24 111.105 ;
     RECT  2.16 111.375 84.24 111.645 ;
     RECT  2.16 111.915 84.24 112.185 ;
     RECT  2.16 112.455 84.24 112.725 ;
     RECT  2.16 112.995 84.24 113.265 ;
     RECT  2.16 113.535 84.24 113.805 ;
     RECT  2.16 114.075 84.24 114.345 ;
     RECT  2.16 114.615 84.24 114.885 ;
     RECT  2.16 115.155 84.24 115.425 ;
     RECT  2.16 115.695 84.24 115.965 ;
     RECT  2.16 116.235 84.24 116.505 ;
     RECT  2.16 116.775 84.24 117.045 ;
     RECT  2.16 117.315 84.24 117.585 ;
     RECT  2.16 117.855 84.24 118.125 ;
     RECT  2.16 118.395 84.24 118.665 ;
     RECT  2.16 118.935 84.24 119.205 ;
     RECT  2.16 119.475 84.24 119.745 ;
     RECT  2.16 120.015 84.24 120.285 ;
     RECT  2.16 120.555 84.24 120.825 ;
     RECT  2.16 121.095 84.24 121.365 ;
     RECT  2.16 121.635 84.24 121.905 ;
     RECT  2.16 122.175 84.24 122.445 ;
     RECT  2.16 122.715 84.24 122.985 ;
     RECT  2.16 123.255 84.24 123.525 ;
     RECT  2.16 123.795 84.24 124.065 ;
     RECT  2.16 124.335 84.24 124.605 ;
     RECT  2.16 124.875 84.24 125.145 ;
     RECT  2.16 125.415 84.24 125.685 ;
     RECT  2.16 125.955 84.24 126.225 ;
     RECT  2.16 126.495 84.24 126.765 ;
     RECT  2.16 127.035 84.24 127.305 ;
    LAYER M1 ;
     RECT  2.16 2.151 84.24 127.449 ;
    LAYER M2 ;
     RECT  0.031 54.954 0.067 55.674 ;
     RECT  0.031 51.786 0.131 51.804 ;
     RECT  0.067 54.648 0.131 56.124 ;
     RECT  0.031 57.456 0.131 57.474 ;
     RECT  0.031 58.626 0.131 59.094 ;
     RECT  0.031 59.976 0.131 60.714 ;
     RECT  0.031 65.214 0.131 66.384 ;
     RECT  0.031 68.616 0.131 69.444 ;
     RECT  0.031 72.162 0.131 72.18 ;
     RECT  0.031 73.386 0.131 73.674 ;
     RECT  0.031 75.006 0.131 75.024 ;
     RECT  0.131 54.648 0.139 54.972 ;
     RECT  0.139 54.576 0.203 54.972 ;
     RECT  0.131 56.106 0.239 56.124 ;
     RECT  0.131 59.076 0.239 59.094 ;
     RECT  0.131 65.214 0.239 65.538 ;
     RECT  0.131 69.3 0.239 69.444 ;
     RECT  0.203 54.576 0.275 54.666 ;
     RECT  0.239 69.426 0.275 69.444 ;
     RECT  0.275 54.576 0.311 54.594 ;
     RECT  0.535 51.246 1.147 51.264 ;
     RECT  1.651 53.451 1.687 53.469 ;
     RECT  1.147 51.246 1.723 51.732 ;
     RECT  1.687 53.298 1.723 53.469 ;
     RECT  1.723 54.414 1.759 56.592 ;
     RECT  1.723 57.384 1.759 57.402 ;
     RECT  1.723 58.536 1.759 58.554 ;
     RECT  1.723 59.616 1.759 62.262 ;
     RECT  1.723 63.126 1.759 63.684 ;
     RECT  1.723 64.746 1.759 64.764 ;
     RECT  1.723 65.754 1.759 65.772 ;
     RECT  1.723 66.636 1.759 66.924 ;
     RECT  1.723 67.716 1.759 67.734 ;
     RECT  1.723 69.336 1.759 70.902 ;
     RECT  1.723 72.846 1.759 73.134 ;
     RECT  1.723 74.466 1.759 74.646 ;
     RECT  1.723 76.086 1.759 76.104 ;
     RECT  1.723 76.896 1.759 76.914 ;
     RECT  1.723 78.516 1.759 78.534 ;
     RECT  0.823 82.764 1.759 82.782 ;
     RECT  1.759 64.746 1.795 64.962 ;
     RECT  1.759 65.754 1.795 67.734 ;
     RECT  1.759 68.724 1.795 70.902 ;
     RECT  1.759 73.926 1.795 76.914 ;
     RECT  1.759 54.414 1.831 63.684 ;
     RECT  1.795 64.476 1.831 64.962 ;
     RECT  1.795 65.754 1.831 71.784 ;
     RECT  1.759 72.576 1.831 73.134 ;
     RECT  1.795 73.926 1.831 77.184 ;
     RECT  1.759 77.976 1.831 78.534 ;
     RECT  1.723 51.246 1.939 51.894 ;
     RECT  1.759 80.91 1.975 80.928 ;
     RECT  1.939 51.138 2.047 51.894 ;
     RECT  1.723 52.866 2.047 53.469 ;
     RECT  2.047 51.138 2.083 53.469 ;
     RECT  1.975 46.926 2.16 46.944 ;
     RECT  0.031 47.736 2.16 47.754 ;
     RECT  2.011 48.744 2.16 48.762 ;
     RECT  0.067 49.896 2.16 49.914 ;
     RECT  2.083 50.706 2.16 53.469 ;
     RECT  1.831 54.414 2.16 78.534 ;
     RECT  0.031 79.596 2.16 79.614 ;
     RECT  1.975 80.91 2.16 81.504 ;
     RECT  1.759 82.566 2.16 82.782 ;
     RECT  2.16 2.151 84.24 127.449 ;
     RECT  84.24 18.576 84.263 21.024 ;
     RECT  84.24 59.346 84.263 63.072 ;
     RECT  84.24 103.086 84.263 112.248 ;
     RECT  84.24 79.02 84.299 79.038 ;
     RECT  84.24 93.6 84.299 101.988 ;
     RECT  84.263 63.018 84.335 63.072 ;
     RECT  84.24 113.58 84.371 119.538 ;
     RECT  84.24 40.878 84.407 46.368 ;
     RECT  84.371 113.58 84.407 119.124 ;
     RECT  84.24 39.096 84.443 40.086 ;
     RECT  84.263 103.086 84.443 107.154 ;
     RECT  84.407 114.39 84.443 118.998 ;
     RECT  84.407 40.878 84.479 44.946 ;
     RECT  84.24 64.368 84.479 67.662 ;
     RECT  84.479 65.25 84.515 67.662 ;
     RECT  84.24 33.39 84.587 33.408 ;
     RECT  84.479 43.65 84.659 44.946 ;
     RECT  84.24 47.16 84.659 47.88 ;
     RECT  84.479 40.878 84.695 42.624 ;
     RECT  84.24 50.328 84.695 51.732 ;
     RECT  84.24 38.25 84.731 38.268 ;
     RECT  84.263 107.91 84.731 112.248 ;
     RECT  84.24 23.13 84.767 23.886 ;
     RECT  84.24 24.984 84.767 28.476 ;
     RECT  84.24 74.736 84.767 76.266 ;
     RECT  84.299 93.6 84.767 100.26 ;
     RECT  84.695 40.878 84.803 42.516 ;
     RECT  84.24 52.758 84.803 52.884 ;
     RECT  84.443 103.086 84.803 107.082 ;
     RECT  84.263 59.346 84.839 62.028 ;
     RECT  84.803 103.086 84.839 106.308 ;
     RECT  84.803 52.758 84.875 52.848 ;
     RECT  84.839 59.346 84.911 60.444 ;
     RECT  84.24 69.3 84.911 70.596 ;
     RECT  84.767 94.032 84.911 100.26 ;
     RECT  84.443 114.39 84.911 118.962 ;
     RECT  84.24 121.68 84.911 121.698 ;
     RECT  84.24 6.93 84.947 8.298 ;
     RECT  84.767 75.168 84.947 76.266 ;
     RECT  84.731 109.566 84.947 112.248 ;
     RECT  84.911 114.39 84.947 115.65 ;
     RECT  84.24 29.61 84.983 31.104 ;
     RECT  84.695 50.328 84.983 51.696 ;
     RECT  84.515 65.754 84.983 67.662 ;
     RECT  84.947 111.69 84.983 112.248 ;
     RECT  84.911 116.478 84.983 118.926 ;
     RECT  84.911 94.032 85.019 97.398 ;
     RECT  84.767 27.846 85.027 28.476 ;
     RECT  84.983 29.61 85.027 30.132 ;
     RECT  84.911 98.154 85.055 100.26 ;
     RECT  84.443 39.798 85.091 40.086 ;
     RECT  85.019 94.95 85.091 97.398 ;
     RECT  84.947 109.566 85.127 110.664 ;
     RECT  84.803 40.878 85.163 42.048 ;
     RECT  84.24 35.586 85.199 35.604 ;
     RECT  84.24 37.134 85.199 37.152 ;
     RECT  84.299 101.43 85.199 101.448 ;
     RECT  85.127 109.566 85.199 110.592 ;
     RECT  84.947 114.471 85.199 115.65 ;
     RECT  84.24 84.888 85.235 84.906 ;
     RECT  84.24 89.856 85.235 90.036 ;
     RECT  85.199 114.516 85.235 115.65 ;
     RECT  84.24 48.942 85.271 49.536 ;
     RECT  84.263 18.576 85.307 20.178 ;
     RECT  84.767 23.166 85.307 23.886 ;
     RECT  84.947 75.168 85.307 75.456 ;
     RECT  84.24 81.918 85.307 82.008 ;
     RECT  84.24 15.498 85.343 17.676 ;
     RECT  84.24 71.928 85.343 72.558 ;
     RECT  85.343 16.11 85.379 17.676 ;
     RECT  84.407 46.008 85.379 46.368 ;
     RECT  84.983 51.48 85.379 51.696 ;
     RECT  85.307 18.576 85.415 19.908 ;
     RECT  85.379 46.008 85.415 46.026 ;
     RECT  84.875 52.83 85.415 52.848 ;
     RECT  84.839 103.086 85.415 106.002 ;
     RECT  85.415 19.008 85.451 19.908 ;
     RECT  84.911 59.346 85.451 59.796 ;
     RECT  84.839 61.398 85.451 62.028 ;
     RECT  84.947 6.93 85.487 7.722 ;
     RECT  84.24 55.26 85.487 55.476 ;
     RECT  85.019 94.032 85.487 94.05 ;
     RECT  84.983 112.23 85.487 112.248 ;
     RECT  84.983 116.478 85.487 116.496 ;
     RECT  84.983 117.252 85.487 118.926 ;
     RECT  85.379 16.11 85.523 16.596 ;
     RECT  85.271 48.978 85.523 49.536 ;
     RECT  84.803 107.064 85.523 107.082 ;
     RECT  84.731 107.91 85.523 108.198 ;
     RECT  85.235 114.516 85.523 115.524 ;
     RECT  85.487 117.252 85.523 118.584 ;
     RECT  85.523 49.248 85.559 49.536 ;
     RECT  85.487 55.26 85.559 55.278 ;
     RECT  85.523 107.91 85.559 107.928 ;
     RECT  85.199 109.566 85.559 110.358 ;
     RECT  85.523 114.552 85.559 115.524 ;
     RECT  85.523 117.36 85.559 118.584 ;
     RECT  84.24 57.348 85.595 57.366 ;
     RECT  84.983 66.6 85.595 67.662 ;
     RECT  85.559 109.566 85.595 109.98 ;
     RECT  85.559 117.36 85.595 117.378 ;
     RECT  85.559 118.17 85.595 118.584 ;
     RECT  84.24 31.896 85.603 32.328 ;
     RECT  84.983 65.754 85.631 65.772 ;
     RECT  85.415 103.086 85.631 105.426 ;
     RECT  85.595 109.566 85.639 109.899 ;
     RECT  85.595 66.6 85.667 67.158 ;
     RECT  85.343 72.54 85.667 72.558 ;
     RECT  85.595 118.404 85.667 118.584 ;
     RECT  84.767 24.984 85.675 26.964 ;
     RECT  85.027 27.846 85.675 30.132 ;
     RECT  85.451 59.346 85.703 59.364 ;
     RECT  85.451 61.398 85.703 61.416 ;
     RECT  85.091 94.986 85.711 97.398 ;
     RECT  85.055 98.154 85.711 99.756 ;
     RECT  84.983 30.996 85.739 31.104 ;
     RECT  84.335 63.018 85.739 63.036 ;
     RECT  84.479 64.368 85.739 64.386 ;
     RECT  85.739 30.996 85.775 31.014 ;
     RECT  84.911 69.57 85.775 70.596 ;
     RECT  85.639 108.801 85.775 109.899 ;
     RECT  85.307 23.166 85.811 23.724 ;
     RECT  85.379 51.678 85.811 51.696 ;
     RECT  85.775 69.57 85.811 69.624 ;
     RECT  85.451 19.008 85.847 19.026 ;
     RECT  85.775 70.578 85.847 70.596 ;
     RECT  85.711 94.986 85.847 99.756 ;
     RECT  85.775 108.846 85.847 109.899 ;
     RECT  84.24 11.916 85.855 12.546 ;
     RECT  85.559 49.518 85.883 49.536 ;
     RECT  84.24 73.386 85.883 73.872 ;
     RECT  85.631 104.13 85.883 105.426 ;
     RECT  85.855 11.916 85.919 13.284 ;
     RECT  85.675 24.984 85.919 30.132 ;
     RECT  85.603 31.896 85.919 32.364 ;
     RECT  85.811 69.57 85.919 69.588 ;
     RECT  85.307 75.168 85.919 75.186 ;
     RECT  85.811 23.166 85.955 23.184 ;
     RECT  85.163 41.256 85.955 42.048 ;
     RECT  84.947 76.248 85.955 76.266 ;
     RECT  85.883 104.256 85.955 105.426 ;
     RECT  85.847 94.986 85.963 99.639 ;
     RECT  85.919 24.984 85.991 28.98 ;
     RECT  85.667 67.14 85.991 67.158 ;
     RECT  85.963 94.644 85.991 99.639 ;
     RECT  85.711 100.782 85.991 100.8 ;
     RECT  85.991 24.984 86.027 27.972 ;
     RECT  84.983 50.328 86.027 50.346 ;
     RECT  86.027 24.984 86.063 26.694 ;
     RECT  85.963 30.186 86.063 30.204 ;
     RECT  85.919 32.346 86.063 32.364 ;
     RECT  86.063 25.254 86.099 26.694 ;
     RECT  85.991 94.644 86.099 97.209 ;
     RECT  86.099 25.758 86.135 26.694 ;
     RECT  86.027 27.846 86.135 27.972 ;
     RECT  85.955 104.976 86.135 105.426 ;
     RECT  85.523 16.146 86.143 16.596 ;
     RECT  85.379 17.388 86.143 17.676 ;
     RECT  86.143 16.146 86.171 17.676 ;
     RECT  85.955 41.256 86.171 41.436 ;
     RECT  86.099 94.644 86.171 95.508 ;
     RECT  85.451 19.89 86.207 19.908 ;
     RECT  84.263 21.006 86.207 21.024 ;
     RECT  86.135 27.954 86.207 27.972 ;
     RECT  85.991 28.881 86.207 28.98 ;
     RECT  84.659 47.862 86.207 47.88 ;
     RECT  85.991 98.082 86.207 99.639 ;
     RECT  86.171 41.256 86.243 41.274 ;
     RECT  86.099 96.336 86.243 97.209 ;
     RECT  86.135 105.021 86.243 105.426 ;
     RECT  86.071 107.721 86.243 107.739 ;
     RECT  85.559 114.552 86.243 115.029 ;
     RECT  85.855 14.616 86.251 14.634 ;
     RECT  86.243 105.138 86.251 105.426 ;
     RECT  85.091 40.068 86.279 40.086 ;
     RECT  86.243 96.336 86.279 97.128 ;
     RECT  85.631 103.086 86.279 103.104 ;
     RECT  85.667 118.476 86.279 118.584 ;
     RECT  86.279 118.566 86.287 118.584 ;
     RECT  86.171 16.308 86.315 17.676 ;
     RECT  84.659 43.65 86.315 44.136 ;
     RECT  85.883 73.386 86.315 73.764 ;
     RECT  86.279 96.732 86.315 97.056 ;
     RECT  86.207 98.766 86.315 99.639 ;
     RECT  84.407 113.58 86.315 113.598 ;
     RECT  86.287 118.566 86.315 118.656 ;
     RECT  85.487 7.128 86.351 7.722 ;
     RECT  86.251 8.946 86.351 8.964 ;
     RECT  86.251 10.296 86.351 10.314 ;
     RECT  85.919 12.528 86.351 13.284 ;
     RECT  86.251 14.616 86.351 14.814 ;
     RECT  86.315 16.308 86.351 17.136 ;
     RECT  84.659 44.928 86.351 44.946 ;
     RECT  86.315 73.746 86.351 73.764 ;
     RECT  85.235 89.856 86.351 89.874 ;
     RECT  86.251 105.138 86.351 106.704 ;
     RECT  85.847 108.846 86.351 109.818 ;
     RECT  86.243 114.552 86.351 114.804 ;
     RECT  86.351 14.796 86.387 14.814 ;
     RECT  86.315 44.118 86.387 44.136 ;
     RECT  85.307 81.918 86.387 81.936 ;
     RECT  86.171 94.644 86.387 95.004 ;
     RECT  86.251 100.818 86.387 100.908 ;
     RECT  86.351 108.846 86.387 108.864 ;
     RECT  86.351 109.8 86.387 109.818 ;
     RECT  86.315 118.638 86.387 118.656 ;
    LAYER M3 ;
     RECT  2.415 2.143 2.505 2.413 ;
     RECT  7.815 2.143 7.905 2.413 ;
     RECT  13.215 2.143 13.305 2.413 ;
     RECT  18.615 2.143 18.705 2.413 ;
     RECT  24.015 2.143 24.105 2.413 ;
     RECT  29.415 2.143 29.505 2.413 ;
     RECT  34.815 2.143 34.905 2.413 ;
     RECT  40.215 2.143 40.305 2.413 ;
     RECT  45.615 2.143 45.705 2.413 ;
     RECT  51.015 2.143 51.105 2.413 ;
     RECT  56.415 2.143 56.505 2.413 ;
     RECT  61.815 2.143 61.905 2.413 ;
     RECT  67.215 2.143 67.305 2.413 ;
     RECT  72.615 2.143 72.705 2.413 ;
     RECT  78.015 2.143 78.105 2.413 ;
     RECT  83.415 2.143 83.505 2.413 ;
     RECT  83.415 2.413 83.697 5.755 ;
     RECT  86.184 5.851 86.202 5.947 ;
     RECT  86.04 5.947 86.202 6.139 ;
     RECT  85.284 6.235 85.302 6.331 ;
     RECT  83.415 5.755 83.898 6.619 ;
     RECT  84.744 6.331 85.302 6.619 ;
     RECT  83.415 6.619 85.302 6.811 ;
     RECT  86.04 6.139 86.31 6.811 ;
     RECT  79.704 3.643 79.722 6.853 ;
     RECT  83.376 6.811 86.31 6.853 ;
     RECT  83.268 6.853 86.31 6.953 ;
     RECT  82.296 6.925 82.314 6.961 ;
     RECT  83.268 6.953 85.302 6.961 ;
     RECT  82.26 6.961 85.302 7.051 ;
     RECT  79.704 6.853 80.262 7.087 ;
     RECT  81.576 7.051 85.302 7.087 ;
     RECT  86.04 6.953 86.31 7.099 ;
     RECT  79.596 7.087 80.262 7.159 ;
     RECT  81.288 7.087 85.302 7.159 ;
     RECT  79.596 7.159 85.302 7.349 ;
     RECT  81.576 7.349 85.302 7.421 ;
     RECT  86.04 7.099 86.346 7.727 ;
     RECT  82.368 7.421 85.302 8.251 ;
     RECT  86.04 7.727 86.31 8.251 ;
     RECT  81.576 7.421 81.594 8.311 ;
     RECT  82.368 8.251 86.31 8.311 ;
     RECT  79.596 7.349 80.802 8.491 ;
     RECT  81.576 8.311 86.31 8.491 ;
     RECT  79.596 8.491 86.31 8.683 ;
     RECT  78.015 2.413 78.297 8.731 ;
     RECT  77.904 8.731 78.297 8.827 ;
     RECT  79.092 8.683 86.31 8.827 ;
     RECT  77.904 8.827 86.31 8.923 ;
     RECT  77.904 8.923 86.346 8.969 ;
     RECT  77.904 8.969 86.31 9.547 ;
     RECT  77.328 9.547 86.31 10.267 ;
     RECT  77.328 10.267 86.346 13.289 ;
     RECT  77.328 13.289 86.31 14.587 ;
     RECT  77.328 14.587 86.346 14.791 ;
     RECT  77.328 14.791 86.382 15.421 ;
     RECT  75.42 15.961 75.438 16.303 ;
     RECT  75.42 16.303 76.086 16.501 ;
     RECT  75.348 16.501 76.086 17.419 ;
     RECT  76.86 15.421 86.382 17.419 ;
     RECT  75.348 17.419 86.382 19.771 ;
     RECT  74.556 19.771 86.382 19.901 ;
     RECT  74.556 19.901 74.574 20.821 ;
     RECT  75.348 19.901 86.382 20.821 ;
     RECT  72.615 2.413 72.897 20.827 ;
     RECT  72.615 20.827 73.494 20.923 ;
     RECT  72.144 20.923 73.494 20.971 ;
     RECT  71.748 20.971 73.494 21.211 ;
     RECT  71.676 21.211 73.494 21.403 ;
     RECT  70.668 21.787 70.686 26.251 ;
     RECT  68.652 23.791 68.67 26.635 ;
     RECT  71.532 21.403 73.494 28.411 ;
     RECT  74.556 20.821 86.382 28.411 ;
     RECT  70.02 26.251 70.686 28.939 ;
     RECT  68.616 26.635 68.67 29.227 ;
     RECT  69.408 28.939 70.686 29.227 ;
     RECT  13.215 2.413 13.497 35.851 ;
     RECT  12.816 35.851 13.497 36.085 ;
     RECT  68.616 29.227 70.686 37.057 ;
     RECT  10.512 36.787 10.53 38.011 ;
     RECT  7.815 2.413 8.097 38.209 ;
     RECT  34.815 2.413 35.097 39.445 ;
     RECT  24.015 2.413 24.297 39.451 ;
     RECT  45.615 2.413 45.897 39.451 ;
     RECT  56.415 2.413 56.697 39.451 ;
     RECT  67.215 2.413 67.497 39.451 ;
     RECT  34.704 39.445 35.097 39.485 ;
     RECT  23.904 39.451 24.297 39.488 ;
     RECT  45.504 39.451 45.897 39.488 ;
     RECT  56.304 39.451 56.697 39.488 ;
     RECT  67.104 39.451 67.497 39.488 ;
     RECT  9.396 39.451 9.414 40.315 ;
     RECT  10.512 38.011 11.106 41.215 ;
     RECT  12.24 36.085 13.497 41.215 ;
     RECT  8.82 40.315 9.414 41.449 ;
     RECT  10.512 41.215 13.497 41.449 ;
     RECT  71.532 28.411 86.382 44.141 ;
     RECT  68.364 37.057 70.686 44.149 ;
     RECT  71.532 44.141 86.346 44.951 ;
     RECT  2.415 2.413 2.697 45.301 ;
     RECT  2.415 45.301 2.862 46.849 ;
     RECT  2.415 46.849 2.934 46.921 ;
     RECT  4.5 47.011 4.518 47.155 ;
     RECT  1.98 46.921 2.97 47.191 ;
     RECT  3.78 47.155 4.518 47.191 ;
     RECT  1.98 47.191 3.006 47.281 ;
     RECT  3.744 47.191 4.518 47.281 ;
     RECT  1.98 47.281 4.518 47.623 ;
     RECT  71.532 44.951 86.202 47.885 ;
     RECT  1.98 47.623 4.698 48.199 ;
     RECT  68.292 44.149 70.686 48.541 ;
     RECT  7.092 38.209 8.097 48.569 ;
     RECT  8.82 41.449 13.497 49.037 ;
     RECT  1.98 48.199 5.238 49.199 ;
     RECT  7.128 48.569 8.097 49.711 ;
     RECT  68.292 48.541 70.722 49.819 ;
     RECT  71.532 47.885 86.022 49.819 ;
     RECT  0.036 47.731 0.054 49.891 ;
     RECT  68.292 49.819 86.022 50.351 ;
     RECT  1.98 49.199 5.13 50.657 ;
     RECT  6.84 49.711 8.097 50.827 ;
     RECT  1.98 50.657 4.77 51.133 ;
     RECT  0.036 49.891 0.09 51.241 ;
     RECT  6.804 50.827 8.097 51.331 ;
     RECT  6.228 51.331 8.097 51.367 ;
     RECT  1.944 51.133 4.77 51.475 ;
     RECT  5.976 51.367 8.097 51.475 ;
     RECT  61.815 2.413 62.097 51.511 ;
     RECT  8.82 49.037 12.294 51.539 ;
     RECT  34.815 39.485 35.097 51.601 ;
     RECT  35.928 51.403 35.946 51.601 ;
     RECT  0.036 51.241 0.558 51.709 ;
     RECT  13.215 49.037 13.497 51.745 ;
     RECT  0.036 51.709 1.17 51.821 ;
     RECT  0.072 51.821 1.17 51.871 ;
     RECT  1.944 51.475 8.097 51.871 ;
     RECT  0.072 51.871 8.097 51.971 ;
     RECT  6.732 51.971 8.097 52.079 ;
     RECT  0.072 51.971 5.706 52.169 ;
     RECT  34.815 51.601 35.946 52.169 ;
     RECT  0.072 52.169 5.562 52.205 ;
     RECT  1.728 52.205 5.562 52.511 ;
     RECT  0.072 52.205 0.558 52.781 ;
     RECT  1.728 52.511 5.382 53.293 ;
     RECT  6.804 52.079 8.097 53.365 ;
     RECT  8.82 51.539 11.214 53.365 ;
     RECT  68.292 50.351 85.986 53.401 ;
     RECT  1.692 53.293 5.382 53.446 ;
     RECT  1.656 53.446 5.382 53.563 ;
     RECT  6.804 53.365 11.214 53.563 ;
     RECT  1.656 53.563 11.214 53.789 ;
     RECT  0.54 52.781 0.558 53.837 ;
     RECT  13.215 51.745 13.698 54.059 ;
     RECT  1.656 53.789 5.922 54.203 ;
     RECT  1.656 54.203 5.49 54.329 ;
     RECT  61.815 51.511 62.154 54.509 ;
     RECT  0.108 53.851 0.126 54.571 ;
     RECT  0.108 54.571 0.306 54.643 ;
     RECT  6.84 53.789 11.214 54.667 ;
     RECT  0.072 54.643 0.306 54.701 ;
     RECT  34.815 52.169 35.622 54.743 ;
     RECT  0.072 54.701 0.27 54.893 ;
     RECT  0.072 54.893 0.198 54.949 ;
     RECT  68.256 53.401 85.986 54.949 ;
     RECT  0.036 54.949 0.198 54.977 ;
     RECT  0.036 54.977 0.162 54.989 ;
     RECT  1.656 54.329 5.058 55.111 ;
     RECT  6.552 54.667 11.214 55.211 ;
     RECT  1.656 55.111 5.562 55.291 ;
     RECT  9.936 55.211 11.214 55.319 ;
     RECT  1.656 55.291 5.67 55.409 ;
     RECT  6.552 55.211 9.018 55.525 ;
     RECT  12.276 51.539 12.294 55.553 ;
     RECT  0.036 54.989 0.126 55.679 ;
     RECT  9.936 55.319 10.098 55.679 ;
     RECT  9.936 55.679 10.062 55.751 ;
     RECT  6.408 55.525 9.018 55.759 ;
     RECT  1.656 55.409 5.202 55.853 ;
     RECT  0.072 55.679 0.126 55.915 ;
     RECT  0.072 55.915 0.306 56.045 ;
     RECT  11.196 55.319 11.214 56.093 ;
     RECT  1.728 55.853 5.202 56.191 ;
     RECT  6.228 55.759 9.018 56.191 ;
     RECT  13.215 54.059 13.497 56.191 ;
     RECT  24.015 39.488 24.297 56.191 ;
     RECT  34.815 54.743 35.097 56.191 ;
     RECT  45.615 39.488 45.897 56.191 ;
     RECT  56.415 39.488 56.697 56.191 ;
     RECT  67.215 39.488 67.497 56.191 ;
     RECT  61.815 54.509 62.097 56.299 ;
     RECT  0.072 56.045 0.234 56.333 ;
     RECT  1.728 56.191 9.018 56.573 ;
     RECT  8.82 56.573 9.018 56.731 ;
     RECT  34.704 56.191 35.097 56.765 ;
     RECT  13.104 56.191 13.497 56.768 ;
     RECT  23.904 56.191 24.297 56.768 ;
     RECT  45.504 56.191 45.897 56.768 ;
     RECT  56.304 56.191 56.697 56.768 ;
     RECT  67.104 56.191 67.497 56.768 ;
     RECT  67.215 56.768 67.497 56.911 ;
     RECT  68.22 54.949 85.986 56.911 ;
     RECT  0.108 57.115 0.126 57.451 ;
     RECT  0.036 57.451 0.126 57.488 ;
     RECT  0.144 57.595 0.162 57.739 ;
     RECT  0.144 57.739 0.27 57.869 ;
     RECT  9.936 55.751 9.954 58.171 ;
     RECT  61.815 56.299 62.622 58.289 ;
     RECT  9.936 58.171 9.99 58.559 ;
     RECT  0.108 58.315 0.126 58.603 ;
     RECT  8.82 56.731 9.126 58.793 ;
     RECT  0.036 58.603 0.126 58.891 ;
     RECT  0.036 58.891 0.306 59.021 ;
     RECT  0.036 59.021 0.234 59.099 ;
     RECT  0.036 59.099 0.162 59.117 ;
     RECT  0.108 59.117 0.126 59.947 ;
     RECT  1.728 56.573 8.097 60.071 ;
     RECT  0.036 59.947 0.126 60.235 ;
     RECT  0.036 60.235 0.198 60.413 ;
     RECT  9.972 58.559 9.99 60.683 ;
     RECT  0.036 60.413 0.126 60.749 ;
     RECT  10.8 60.691 10.818 60.881 ;
     RECT  0.108 60.749 0.126 61.181 ;
     RECT  10.764 61.087 10.782 61.187 ;
     RECT  1.728 60.071 6.858 61.195 ;
     RECT  7.815 60.071 8.097 61.195 ;
     RECT  8.82 58.793 8.874 61.259 ;
     RECT  0.108 62.491 0.126 62.971 ;
     RECT  0.108 62.971 0.198 63.149 ;
     RECT  0.108 63.149 0.126 63.581 ;
     RECT  61.815 58.289 62.097 63.589 ;
     RECT  10.836 63.589 10.854 63.643 ;
     RECT  13.215 56.768 13.497 63.643 ;
     RECT  24.015 56.768 24.297 63.643 ;
     RECT  34.815 56.765 35.097 63.643 ;
     RECT  45.615 56.768 45.897 63.643 ;
     RECT  56.415 56.768 56.697 63.643 ;
     RECT  67.215 56.911 85.986 63.643 ;
     RECT  9.936 63.595 9.954 63.661 ;
     RECT  10.8 63.643 10.854 63.661 ;
     RECT  9.936 63.661 10.854 63.689 ;
     RECT  13.104 63.643 13.497 63.689 ;
     RECT  22.824 63.589 22.842 63.689 ;
     RECT  23.904 63.643 24.297 63.689 ;
     RECT  30.78 63.589 30.798 63.689 ;
     RECT  34.704 63.643 35.097 63.689 ;
     RECT  42.768 63.589 42.786 63.689 ;
     RECT  45.504 63.643 45.897 63.689 ;
     RECT  54.72 63.589 54.738 63.689 ;
     RECT  56.304 63.643 56.697 63.689 ;
     RECT  61.815 63.589 62.73 63.689 ;
     RECT  67.104 63.643 85.986 63.689 ;
     RECT  1.728 61.195 8.097 63.691 ;
     RECT  8.82 61.259 8.838 63.691 ;
     RECT  1.728 63.691 8.838 64.129 ;
     RECT  0.288 65.035 0.306 65.083 ;
     RECT  0.216 65.083 0.306 65.131 ;
     RECT  0.144 65.131 0.306 65.209 ;
     RECT  9.936 63.689 10.818 65.309 ;
     RECT  0.036 65.209 0.306 65.453 ;
     RECT  9.936 65.309 10.782 65.471 ;
     RECT  0.036 65.453 0.234 65.543 ;
     RECT  0.036 65.543 0.162 65.549 ;
     RECT  10.764 65.471 10.782 66.119 ;
     RECT  0.036 65.549 0.126 66.389 ;
     RECT  0.036 66.389 0.054 66.413 ;
     RECT  66.132 64.057 66.15 67.085 ;
     RECT  1.728 64.129 9.162 67.133 ;
     RECT  67.215 63.689 85.986 67.163 ;
     RECT  13.215 63.689 13.497 67.261 ;
     RECT  24.015 63.689 24.297 67.261 ;
     RECT  34.815 63.689 35.097 67.261 ;
     RECT  45.615 63.689 45.897 67.261 ;
     RECT  56.415 63.689 56.697 67.261 ;
     RECT  61.815 63.689 62.097 67.261 ;
     RECT  63.288 65.947 63.306 67.261 ;
     RECT  10.836 67.261 10.854 67.369 ;
     RECT  22.824 67.261 22.842 67.369 ;
     RECT  30.78 67.261 30.798 67.369 ;
     RECT  42.768 67.261 42.786 67.369 ;
     RECT  54.72 67.261 54.738 67.369 ;
     RECT  10.836 67.369 10.926 67.397 ;
     RECT  13.215 67.261 13.554 67.397 ;
     RECT  22.824 67.369 22.914 67.397 ;
     RECT  24.015 67.261 24.354 67.397 ;
     RECT  30.78 67.369 30.87 67.397 ;
     RECT  34.815 67.261 35.154 67.397 ;
     RECT  42.768 67.369 42.858 67.397 ;
     RECT  45.615 67.261 45.954 67.397 ;
     RECT  54.72 67.369 54.81 67.397 ;
     RECT  56.415 67.261 56.754 67.397 ;
     RECT  8.82 67.133 9.162 67.405 ;
     RECT  9.936 65.471 9.954 67.405 ;
     RECT  13.215 67.397 13.497 67.432 ;
     RECT  24.015 67.397 24.297 67.432 ;
     RECT  34.815 67.397 35.097 67.432 ;
     RECT  45.615 67.397 45.897 67.432 ;
     RECT  56.415 67.397 56.697 67.432 ;
     RECT  67.215 67.163 85.914 67.432 ;
     RECT  8.82 67.405 9.954 67.469 ;
     RECT  10.908 67.397 10.926 67.469 ;
     RECT  22.896 67.397 22.914 67.469 ;
     RECT  30.852 67.397 30.87 67.469 ;
     RECT  42.84 67.397 42.858 67.469 ;
     RECT  54.792 67.397 54.81 67.469 ;
     RECT  61.815 67.261 63.306 67.469 ;
     RECT  67.104 67.432 85.914 67.531 ;
     RECT  34.704 67.432 35.097 67.565 ;
     RECT  13.104 67.432 13.497 67.568 ;
     RECT  23.904 67.432 24.297 67.568 ;
     RECT  45.504 67.432 45.897 67.568 ;
     RECT  56.304 67.432 56.697 67.568 ;
     RECT  63.288 67.469 63.306 67.661 ;
     RECT  66.708 67.531 85.914 67.709 ;
     RECT  0.036 68.587 0.054 68.611 ;
     RECT  8.82 67.469 9.486 68.917 ;
     RECT  1.728 67.133 8.097 68.953 ;
     RECT  8.82 68.917 9.99 68.953 ;
     RECT  0.036 68.611 0.126 69.067 ;
     RECT  1.728 68.953 9.99 69.341 ;
     RECT  0.036 69.067 0.27 69.449 ;
     RECT  0.036 69.449 0.162 69.485 ;
     RECT  67.215 67.709 85.914 69.485 ;
     RECT  74.16 69.485 85.914 69.593 ;
     RECT  61.815 67.469 62.097 69.799 ;
     RECT  10.8 69.601 10.818 69.827 ;
     RECT  0.252 70.219 0.27 70.315 ;
     RECT  0.144 70.315 0.27 70.349 ;
     RECT  8.82 69.341 9.99 70.573 ;
     RECT  74.16 69.593 85.806 70.573 ;
     RECT  0.144 70.349 0.162 70.589 ;
     RECT  0.108 70.699 0.126 70.877 ;
     RECT  61.815 69.799 62.154 71.041 ;
     RECT  8.82 70.573 10.566 71.113 ;
     RECT  61.815 71.041 62.73 71.653 ;
     RECT  8.82 71.113 10.854 71.689 ;
     RECT  11.664 69.223 11.682 71.689 ;
     RECT  0.144 71.803 0.162 71.851 ;
     RECT  8.82 71.689 11.682 71.887 ;
     RECT  0.144 71.851 0.27 71.981 ;
     RECT  8.82 71.887 11.826 72.121 ;
     RECT  0.036 72.139 0.126 72.185 ;
     RECT  0.108 72.185 0.126 72.221 ;
     RECT  67.215 69.485 73.422 72.229 ;
     RECT  74.16 70.573 85.842 72.229 ;
     RECT  61.815 71.653 63.306 72.329 ;
     RECT  67.215 72.229 85.842 72.365 ;
     RECT  1.728 69.341 8.097 72.689 ;
     RECT  6.912 72.689 8.097 72.797 ;
     RECT  63.288 72.329 63.306 72.869 ;
     RECT  0.108 73.051 0.126 73.381 ;
     RECT  74.16 72.365 85.842 73.381 ;
     RECT  74.16 73.381 86.31 73.435 ;
     RECT  1.728 72.689 6.138 73.651 ;
     RECT  0.036 73.381 0.126 73.679 ;
     RECT  0.036 73.679 0.054 73.709 ;
     RECT  74.16 73.435 86.346 73.769 ;
     RECT  8.82 72.121 12.294 73.813 ;
     RECT  13.215 67.568 13.497 73.813 ;
     RECT  1.728 73.651 6.354 73.841 ;
     RECT  0.108 74.731 0.126 75.001 ;
     RECT  0.036 75.001 0.126 75.029 ;
     RECT  0.036 75.029 0.054 75.053 ;
     RECT  1.728 73.841 6.138 75.091 ;
     RECT  7.092 72.797 8.097 75.091 ;
     RECT  8.82 73.813 13.497 75.127 ;
     RECT  14.256 74.929 14.274 75.127 ;
     RECT  74.16 73.769 85.878 75.163 ;
     RECT  8.82 75.127 14.274 76.109 ;
     RECT  1.728 75.091 8.097 76.199 ;
     RECT  74.16 75.163 85.914 76.243 ;
     RECT  1.728 76.199 5.274 76.469 ;
     RECT  1.728 76.469 5.202 77.009 ;
     RECT  8.82 76.109 13.698 77.189 ;
     RECT  61.815 72.329 62.406 77.387 ;
     RECT  1.728 77.009 4.842 77.899 ;
     RECT  14.544 76.279 14.562 77.971 ;
     RECT  1.728 77.899 5.13 78.061 ;
     RECT  1.728 78.061 5.31 78.331 ;
     RECT  6.12 76.199 8.097 78.331 ;
     RECT  8.82 77.189 13.497 78.403 ;
     RECT  14.508 77.971 14.562 78.403 ;
     RECT  1.728 78.331 8.097 78.539 ;
     RECT  8.82 78.403 14.562 78.907 ;
     RECT  15.408 77.053 15.426 78.907 ;
     RECT  1.98 78.539 8.097 79.205 ;
     RECT  5.436 79.205 8.097 79.313 ;
     RECT  74.16 76.243 85.95 79.349 ;
     RECT  8.82 78.907 15.426 79.547 ;
     RECT  0.036 77.707 0.054 79.619 ;
     RECT  20.196 73.771 20.214 80.159 ;
     RECT  6.408 79.313 8.097 80.527 ;
     RECT  6.336 80.527 8.097 80.699 ;
     RECT  1.98 79.205 4.698 80.905 ;
     RECT  5.436 79.313 5.454 80.933 ;
     RECT  74.736 79.349 85.95 80.969 ;
     RECT  61.815 77.387 62.097 81.373 ;
     RECT  1.764 80.905 4.698 81.869 ;
     RECT  74.808 80.969 85.95 81.913 ;
     RECT  1.764 81.869 4.518 82.409 ;
     RECT  6.804 80.699 8.097 82.481 ;
     RECT  67.215 72.365 73.422 82.489 ;
     RECT  1.764 82.409 3.69 82.589 ;
     RECT  66.708 82.489 73.422 82.589 ;
     RECT  0.828 77.611 0.846 82.787 ;
     RECT  2.415 82.589 3.69 82.949 ;
     RECT  3.672 82.949 3.69 83.489 ;
     RECT  4.5 82.409 4.518 83.525 ;
     RECT  74.808 81.913 86.382 85.289 ;
     RECT  8.82 79.547 15.102 85.415 ;
     RECT  74.952 85.289 86.382 85.559 ;
     RECT  2.415 82.949 2.697 86.035 ;
     RECT  75.024 85.559 86.382 86.503 ;
     RECT  3.96 86.611 3.978 86.737 ;
     RECT  2.304 86.035 2.697 86.765 ;
     RECT  61.815 81.373 62.406 86.837 ;
     RECT  3.96 86.737 4.986 86.881 ;
     RECT  3.96 86.881 5.526 86.999 ;
     RECT  4.104 86.999 4.986 87.035 ;
     RECT  67.215 82.589 73.422 87.079 ;
     RECT  74.664 86.503 86.382 87.079 ;
     RECT  4.392 87.035 4.806 87.107 ;
     RECT  67.215 87.079 86.382 87.143 ;
     RECT  67.215 87.143 74.142 87.925 ;
     RECT  75.024 87.143 86.382 87.925 ;
     RECT  8.856 85.415 15.102 87.989 ;
     RECT  67.215 87.925 86.382 88.187 ;
     RECT  24.015 67.568 24.297 88.591 ;
     RECT  34.815 67.565 35.097 88.591 ;
     RECT  45.615 67.568 45.897 88.591 ;
     RECT  56.415 67.568 56.697 88.591 ;
     RECT  67.215 88.187 74.142 88.591 ;
     RECT  8.856 87.989 14.526 88.637 ;
     RECT  23.904 88.591 24.297 88.637 ;
     RECT  34.704 88.591 35.097 88.637 ;
     RECT  45.504 88.591 45.897 88.637 ;
     RECT  56.304 88.591 56.697 88.637 ;
     RECT  67.104 88.591 74.142 88.637 ;
     RECT  8.928 88.637 14.526 90.239 ;
     RECT  12.24 90.239 14.526 90.311 ;
     RECT  67.215 88.637 74.142 90.355 ;
     RECT  75.024 88.187 86.382 90.355 ;
     RECT  16.236 80.869 16.254 90.419 ;
     RECT  8.928 90.239 11.106 90.617 ;
     RECT  67.215 90.355 86.382 90.617 ;
     RECT  67.215 90.617 74.142 91.363 ;
     RECT  75.024 90.617 86.382 91.363 ;
     RECT  9.396 90.617 11.106 91.661 ;
     RECT  13.215 90.311 14.526 92.039 ;
     RECT  4.788 87.107 4.806 92.399 ;
     RECT  5.724 91.093 5.742 92.443 ;
     RECT  5.724 92.443 6.03 92.471 ;
     RECT  7.092 82.481 8.097 93.119 ;
     RECT  67.215 91.363 86.382 96.509 ;
     RECT  67.215 96.509 68.382 96.605 ;
     RECT  67.215 96.605 68.346 96.797 ;
     RECT  6.012 92.471 6.03 97.529 ;
     RECT  69.264 96.509 86.382 97.565 ;
     RECT  69.264 97.565 73.422 97.709 ;
     RECT  69.948 97.709 73.422 97.853 ;
     RECT  74.16 97.565 86.382 98.189 ;
     RECT  69.984 97.853 73.422 98.237 ;
     RECT  70.416 98.237 73.422 98.717 ;
     RECT  74.16 98.189 74.178 98.923 ;
     RECT  75.024 98.189 86.382 98.923 ;
     RECT  70.416 98.717 71.226 99.019 ;
     RECT  74.16 98.923 86.382 99.053 ;
     RECT  69.732 99.019 71.226 99.149 ;
     RECT  72.072 98.717 73.422 99.197 ;
     RECT  67.215 96.797 68.274 99.391 ;
     RECT  10.512 91.661 11.106 99.419 ;
     RECT  70.092 99.149 71.226 99.419 ;
     RECT  66.708 99.391 68.274 99.491 ;
     RECT  70.164 99.419 71.226 99.491 ;
     RECT  72.072 99.197 73.35 99.725 ;
     RECT  75.06 99.053 86.382 100.061 ;
     RECT  12.24 90.311 12.258 100.253 ;
     RECT  72.072 99.725 72.954 100.741 ;
     RECT  5.688 97.645 5.706 100.769 ;
     RECT  72.072 100.741 73.026 100.781 ;
     RECT  9.396 91.661 9.45 101.219 ;
     RECT  14.508 92.039 14.526 101.345 ;
     RECT  9.432 101.219 9.45 102.227 ;
     RECT  67.215 99.491 68.274 102.269 ;
     RECT  11.088 99.419 11.106 102.461 ;
     RECT  72.072 100.781 72.897 102.667 ;
     RECT  72.072 102.667 72.99 102.989 ;
     RECT  70.416 99.491 71.226 103.085 ;
     RECT  67.215 102.269 68.238 103.229 ;
     RECT  70.452 103.085 71.226 103.277 ;
     RECT  75.132 100.061 86.382 103.325 ;
     RECT  72.252 102.989 72.99 103.373 ;
     RECT  5.112 100.849 5.13 103.469 ;
     RECT  74.16 99.053 74.178 103.505 ;
     RECT  6.804 103.477 6.822 103.613 ;
     RECT  67.215 103.229 68.202 103.805 ;
     RECT  67.215 103.805 68.166 104.093 ;
     RECT  75.312 103.325 86.382 104.909 ;
     RECT  70.452 103.277 71.046 105.149 ;
     RECT  70.956 105.149 71.046 105.485 ;
     RECT  71.028 105.485 71.046 105.533 ;
     RECT  75.636 104.909 86.382 105.677 ;
     RECT  72.252 103.373 72.897 105.725 ;
     RECT  76.32 105.677 86.382 108.869 ;
     RECT  4.392 103.585 4.41 109.139 ;
     RECT  3.456 109.291 3.474 109.469 ;
     RECT  76.32 108.869 86.346 109.589 ;
     RECT  76.356 109.589 86.346 109.795 ;
     RECT  0.036 112.315 0.054 112.445 ;
     RECT  76.356 109.795 86.382 113.405 ;
     RECT  76.356 113.405 85.41 114.511 ;
     RECT  86.184 113.405 86.382 114.511 ;
     RECT  76.356 114.511 86.382 117.509 ;
     RECT  76.356 117.509 76.374 117.779 ;
     RECT  77.58 117.509 86.382 118.157 ;
     RECT  77.616 118.157 86.382 118.229 ;
     RECT  78.015 118.229 86.382 118.319 ;
     RECT  78.015 118.319 79.794 118.589 ;
     RECT  80.748 118.319 86.382 118.661 ;
     RECT  80.748 118.661 86.346 120.029 ;
     RECT  80.748 120.029 82.566 120.605 ;
     RECT  79.236 118.589 79.794 120.653 ;
     RECT  81.972 120.605 82.566 120.893 ;
     RECT  83.376 120.029 86.346 121.085 ;
     RECT  79.776 120.653 79.794 121.373 ;
     RECT  83.376 121.085 86.274 121.565 ;
     RECT  80.748 120.605 80.766 121.613 ;
     RECT  86.112 121.565 86.274 121.613 ;
     RECT  82.152 120.893 82.566 121.661 ;
     RECT  82.548 121.661 82.566 121.853 ;
     RECT  83.376 121.565 85.23 122.237 ;
     RECT  83.376 122.237 84.762 122.333 ;
     RECT  86.112 121.613 86.238 122.429 ;
     RECT  86.112 122.429 86.13 122.525 ;
     RECT  84.744 122.333 84.762 122.621 ;
     RECT  83.376 122.333 84.006 122.717 ;
     RECT  83.415 122.717 84.006 126.749 ;
     RECT  2.415 86.765 2.697 127.187 ;
     RECT  7.815 93.119 8.097 127.187 ;
     RECT  13.215 92.039 13.497 127.187 ;
     RECT  18.615 2.413 18.897 127.187 ;
     RECT  24.015 88.637 24.297 127.187 ;
     RECT  29.415 2.413 29.697 127.187 ;
     RECT  34.815 88.637 35.097 127.187 ;
     RECT  40.215 2.413 40.497 127.187 ;
     RECT  45.615 88.637 45.897 127.187 ;
     RECT  51.015 2.413 51.297 127.187 ;
     RECT  56.415 88.637 56.697 127.187 ;
     RECT  61.815 86.837 62.097 127.187 ;
     RECT  67.215 104.093 67.497 127.187 ;
     RECT  72.615 105.725 72.897 127.187 ;
     RECT  78.015 118.589 78.297 127.187 ;
     RECT  83.415 126.749 83.697 127.187 ;
     RECT  2.415 127.187 2.505 127.457 ;
     RECT  7.815 127.187 7.905 127.457 ;
     RECT  13.215 127.187 13.305 127.457 ;
     RECT  18.615 127.187 18.705 127.457 ;
     RECT  24.015 127.187 24.105 127.457 ;
     RECT  29.415 127.187 29.505 127.457 ;
     RECT  34.815 127.187 34.905 127.457 ;
     RECT  40.215 127.187 40.305 127.457 ;
     RECT  45.615 127.187 45.705 127.457 ;
     RECT  51.015 127.187 51.105 127.457 ;
     RECT  56.415 127.187 56.505 127.457 ;
     RECT  61.815 127.187 61.905 127.457 ;
     RECT  67.215 127.187 67.305 127.457 ;
     RECT  72.615 127.187 72.705 127.457 ;
     RECT  78.015 127.187 78.105 127.457 ;
     RECT  83.415 127.187 83.505 127.457 ;
    LAYER M4 ;
     RECT  0.012 51.408 2.408 78.12 ;
     RECT  0.065 112.416 2.408 112.44 ;
     RECT  2.408 2.148 2.512 127.452 ;
     RECT  2.512 2.418 2.704 127.182 ;
     RECT  2.704 50.496 2.873 78.12 ;
     RECT  2.873 50.496 3.341 77.784 ;
     RECT  3.341 50.688 3.413 77.784 ;
     RECT  3.413 50.784 3.485 77.784 ;
     RECT  2.704 109.44 3.485 109.464 ;
     RECT  3.485 50.88 3.737 77.784 ;
     RECT  3.737 51.744 3.773 77.784 ;
     RECT  3.773 51.744 3.953 77.064 ;
     RECT  3.953 52.848 4.025 77.064 ;
     RECT  4.025 52.944 4.097 77.064 ;
     RECT  4.097 53.52 4.277 77.064 ;
     RECT  4.277 76.416 4.385 77.064 ;
     RECT  4.277 53.52 4.601 75.24 ;
     RECT  4.601 53.52 4.673 55.032 ;
     RECT  4.385 76.416 4.781 76.44 ;
     RECT  4.673 53.52 4.925 54.984 ;
     RECT  4.925 54.192 4.961 54.984 ;
     RECT  4.961 54.96 5.033 54.984 ;
     RECT  4.601 56.304 5.033 75.24 ;
     RECT  3.953 51.744 5.213 51.768 ;
     RECT  5.033 67.536 5.213 75.24 ;
     RECT  5.213 73.296 5.321 74.088 ;
     RECT  5.213 75.12 5.321 75.24 ;
     RECT  5.321 75.216 5.537 75.24 ;
     RECT  5.033 56.304 5.569 66.504 ;
     RECT  5.569 56.208 5.573 66.504 ;
     RECT  5.573 60.048 5.681 66.504 ;
     RECT  5.681 60.048 5.717 61.128 ;
     RECT  5.213 67.536 5.717 72.168 ;
     RECT  5.717 60.048 5.753 60.072 ;
     RECT  5.717 61.104 5.753 61.128 ;
     RECT  5.573 56.208 5.825 58.776 ;
     RECT  2.704 112.32 6.707 112.344 ;
     RECT  2.704 79.968 6.803 79.992 ;
     RECT  5.717 67.536 7.081 70.296 ;
     RECT  5.717 71.328 7.081 72.168 ;
     RECT  6.541 54.672 7.261 54.696 ;
     RECT  2.704 40.32 7.808 40.344 ;
     RECT  7.153 43.632 7.808 43.656 ;
     RECT  7.117 44.928 7.808 44.952 ;
     RECT  7.153 48.72 7.808 48.744 ;
     RECT  7.261 53.856 7.808 54.696 ;
     RECT  5.825 56.208 7.808 57.96 ;
     RECT  5.681 62.16 7.808 66.504 ;
     RECT  7.081 67.536 7.808 72.168 ;
     RECT  5.321 73.296 7.808 73.8 ;
     RECT  6.865 76.56 7.808 76.584 ;
     RECT  4.237 86.784 7.808 86.808 ;
     RECT  6.757 92.688 7.808 92.712 ;
     RECT  7.808 2.148 7.912 127.452 ;
     RECT  7.912 2.418 8.104 127.182 ;
     RECT  8.104 40.32 8.849 40.344 ;
     RECT  8.104 72.144 8.921 72.168 ;
     RECT  8.104 56.208 9.961 57.96 ;
     RECT  9.637 47.664 11.113 47.688 ;
     RECT  9.529 75.168 11.185 75.192 ;
     RECT  8.104 76.56 11.185 76.584 ;
     RECT  9.385 39.456 13.208 39.48 ;
     RECT  9.457 42.48 13.208 42.504 ;
     RECT  8.104 43.632 13.208 43.656 ;
     RECT  8.104 44.928 13.208 44.952 ;
     RECT  11.113 47.664 13.208 47.736 ;
     RECT  8.104 48.72 13.208 48.744 ;
     RECT  8.104 50.064 13.208 50.088 ;
     RECT  8.104 53.856 13.208 55.224 ;
     RECT  9.961 56.208 13.208 58.2 ;
     RECT  8.104 62.976 13.208 71.16 ;
     RECT  9.457 72.192 13.208 72.216 ;
     RECT  8.104 73.296 13.208 73.8 ;
     RECT  11.185 75.168 13.208 76.584 ;
     RECT  9.493 80.256 13.208 80.28 ;
     RECT  10.033 83.52 13.208 83.544 ;
     RECT  8.104 86.784 13.208 86.808 ;
     RECT  8.104 88.608 13.208 88.632 ;
     RECT  8.104 92.688 13.208 92.712 ;
     RECT  12.229 100.224 13.208 100.248 ;
     RECT  13.208 2.148 13.312 127.452 ;
     RECT  13.312 2.418 13.504 127.182 ;
     RECT  13.504 39.456 18.608 39.48 ;
     RECT  13.504 42.48 18.608 42.504 ;
     RECT  13.504 43.632 18.608 43.656 ;
     RECT  13.504 44.928 18.608 44.952 ;
     RECT  13.504 47.664 18.608 47.736 ;
     RECT  13.504 48.72 18.608 48.744 ;
     RECT  13.504 50.064 18.608 50.088 ;
     RECT  13.504 53.856 18.608 55.224 ;
     RECT  13.504 56.208 18.608 58.2 ;
     RECT  13.504 62.976 18.608 71.16 ;
     RECT  13.504 72.192 18.608 72.216 ;
     RECT  13.504 73.296 18.608 73.8 ;
     RECT  13.504 75.168 18.608 76.584 ;
     RECT  13.504 80.256 18.608 80.28 ;
     RECT  13.504 83.52 18.608 83.544 ;
     RECT  13.504 86.784 18.608 86.808 ;
     RECT  13.504 88.608 18.608 88.632 ;
     RECT  13.504 92.688 18.608 92.712 ;
     RECT  13.504 100.224 18.608 100.248 ;
     RECT  18.608 2.148 18.712 127.452 ;
     RECT  18.712 2.418 18.904 127.182 ;
     RECT  18.904 73.296 20.225 73.8 ;
     RECT  18.904 39.456 24.008 39.48 ;
     RECT  18.904 42.48 24.008 42.504 ;
     RECT  18.904 43.632 24.008 43.656 ;
     RECT  18.904 44.928 24.008 44.952 ;
     RECT  18.904 47.664 24.008 47.736 ;
     RECT  18.904 48.72 24.008 48.744 ;
     RECT  18.904 50.064 24.008 50.088 ;
     RECT  18.904 53.856 24.008 55.224 ;
     RECT  18.904 56.208 24.008 58.2 ;
     RECT  18.904 62.976 24.008 71.16 ;
     RECT  18.904 72.192 24.008 72.216 ;
     RECT  20.225 73.296 24.008 73.656 ;
     RECT  18.904 75.168 24.008 76.584 ;
     RECT  18.904 80.256 24.008 80.28 ;
     RECT  18.904 83.52 24.008 83.544 ;
     RECT  18.904 86.784 24.008 86.808 ;
     RECT  18.904 88.608 24.008 88.632 ;
     RECT  18.904 92.688 24.008 92.712 ;
     RECT  18.904 100.224 24.008 100.248 ;
     RECT  24.008 2.148 24.112 127.452 ;
     RECT  24.112 2.418 24.304 127.182 ;
     RECT  24.304 39.456 29.408 39.48 ;
     RECT  24.304 42.48 29.408 42.504 ;
     RECT  24.304 43.632 29.408 43.656 ;
     RECT  24.304 44.928 29.408 44.952 ;
     RECT  24.304 47.664 29.408 47.736 ;
     RECT  24.304 48.72 29.408 48.744 ;
     RECT  24.304 50.064 29.408 50.088 ;
     RECT  24.304 53.856 29.408 55.224 ;
     RECT  24.304 56.208 29.408 58.2 ;
     RECT  24.304 62.976 29.408 71.16 ;
     RECT  24.304 72.192 29.408 72.216 ;
     RECT  24.304 73.296 29.408 73.656 ;
     RECT  24.304 75.168 29.408 76.584 ;
     RECT  24.304 80.256 29.408 80.28 ;
     RECT  24.304 83.52 29.408 83.544 ;
     RECT  24.304 86.784 29.408 86.808 ;
     RECT  24.304 88.608 29.408 88.632 ;
     RECT  24.304 92.688 29.408 92.712 ;
     RECT  24.304 100.224 29.408 100.248 ;
     RECT  29.408 2.148 29.512 127.452 ;
     RECT  29.512 2.418 29.704 127.182 ;
     RECT  29.704 39.456 34.808 39.48 ;
     RECT  29.704 42.48 34.808 42.504 ;
     RECT  29.704 43.632 34.808 43.656 ;
     RECT  29.704 44.928 34.808 44.952 ;
     RECT  29.704 47.664 34.808 47.736 ;
     RECT  29.704 48.72 34.808 48.744 ;
     RECT  29.704 50.064 34.808 50.088 ;
     RECT  29.704 53.856 34.808 55.224 ;
     RECT  29.704 56.208 34.808 58.2 ;
     RECT  29.704 62.976 34.808 71.16 ;
     RECT  29.704 72.192 34.808 72.216 ;
     RECT  29.704 73.296 34.808 73.656 ;
     RECT  29.704 75.168 34.808 76.584 ;
     RECT  29.704 80.256 34.808 80.28 ;
     RECT  29.704 83.52 34.808 83.544 ;
     RECT  29.704 86.784 34.808 86.808 ;
     RECT  29.704 88.608 34.808 88.632 ;
     RECT  29.704 92.688 34.808 92.712 ;
     RECT  29.704 100.224 34.808 100.248 ;
     RECT  34.808 2.148 34.912 127.452 ;
     RECT  34.912 2.418 35.104 127.182 ;
     RECT  35.104 39.456 40.208 39.48 ;
     RECT  35.104 42.48 40.208 42.504 ;
     RECT  35.104 43.632 40.208 43.656 ;
     RECT  35.104 44.928 40.208 44.952 ;
     RECT  35.104 47.664 40.208 47.736 ;
     RECT  35.104 48.72 40.208 48.744 ;
     RECT  35.104 50.064 40.208 50.088 ;
     RECT  35.104 53.856 40.208 55.224 ;
     RECT  35.104 56.208 40.208 58.2 ;
     RECT  35.104 62.976 40.208 71.16 ;
     RECT  35.104 72.192 40.208 72.216 ;
     RECT  35.104 73.296 40.208 73.656 ;
     RECT  35.104 75.168 40.208 76.584 ;
     RECT  35.104 80.256 40.208 80.28 ;
     RECT  35.104 83.52 40.208 83.544 ;
     RECT  35.104 86.784 40.208 86.808 ;
     RECT  35.104 88.608 40.208 88.632 ;
     RECT  35.104 92.688 40.208 92.712 ;
     RECT  35.104 100.224 40.208 100.248 ;
     RECT  40.208 2.148 40.312 127.452 ;
     RECT  40.312 2.418 40.504 127.182 ;
     RECT  40.504 39.456 45.608 39.48 ;
     RECT  40.504 42.48 45.608 42.504 ;
     RECT  40.504 43.632 45.608 43.656 ;
     RECT  40.504 44.928 45.608 44.952 ;
     RECT  40.504 47.664 45.608 47.736 ;
     RECT  40.504 48.72 45.608 48.744 ;
     RECT  40.504 50.064 45.608 50.088 ;
     RECT  40.504 53.856 45.608 55.224 ;
     RECT  40.504 56.208 45.608 58.2 ;
     RECT  40.504 62.976 45.608 71.16 ;
     RECT  40.504 72.192 45.608 72.216 ;
     RECT  40.504 73.296 45.608 73.656 ;
     RECT  40.504 75.168 45.608 76.584 ;
     RECT  40.504 80.256 45.608 80.28 ;
     RECT  40.504 83.52 45.608 83.544 ;
     RECT  40.504 86.784 45.608 86.808 ;
     RECT  40.504 88.608 45.608 88.632 ;
     RECT  40.504 92.688 45.608 92.712 ;
     RECT  40.504 100.224 45.608 100.248 ;
     RECT  45.608 2.148 45.712 127.452 ;
     RECT  45.712 2.418 45.904 127.182 ;
     RECT  45.904 39.456 51.008 39.48 ;
     RECT  45.904 42.48 51.008 42.504 ;
     RECT  45.904 43.632 51.008 43.656 ;
     RECT  45.904 44.928 51.008 44.952 ;
     RECT  45.904 47.664 51.008 47.736 ;
     RECT  45.904 48.72 51.008 48.744 ;
     RECT  45.904 50.064 51.008 50.088 ;
     RECT  45.904 53.856 51.008 55.224 ;
     RECT  45.904 56.208 51.008 58.2 ;
     RECT  45.904 62.976 51.008 71.16 ;
     RECT  45.904 72.192 51.008 72.216 ;
     RECT  45.904 73.296 51.008 73.656 ;
     RECT  45.904 75.168 51.008 76.584 ;
     RECT  45.904 80.256 51.008 80.28 ;
     RECT  45.904 83.52 51.008 83.544 ;
     RECT  45.904 86.784 51.008 86.808 ;
     RECT  45.904 88.608 51.008 88.632 ;
     RECT  45.904 92.688 51.008 92.712 ;
     RECT  45.904 100.224 51.008 100.248 ;
     RECT  51.008 2.148 51.112 127.452 ;
     RECT  51.112 2.418 51.304 127.182 ;
     RECT  51.304 39.456 56.408 39.48 ;
     RECT  51.304 42.48 56.408 42.504 ;
     RECT  51.304 43.632 56.408 43.656 ;
     RECT  51.304 44.928 56.408 44.952 ;
     RECT  51.304 47.664 56.408 47.736 ;
     RECT  51.304 48.72 56.408 48.744 ;
     RECT  51.304 50.064 56.408 50.088 ;
     RECT  51.304 53.856 56.408 55.224 ;
     RECT  51.304 56.208 56.408 58.2 ;
     RECT  51.304 62.976 56.408 71.16 ;
     RECT  51.304 72.192 56.408 72.216 ;
     RECT  51.304 73.296 56.408 73.656 ;
     RECT  51.304 75.168 56.408 76.584 ;
     RECT  51.304 80.256 56.408 80.28 ;
     RECT  51.304 83.52 56.408 83.544 ;
     RECT  51.304 86.784 56.408 86.808 ;
     RECT  51.304 88.608 56.408 88.632 ;
     RECT  51.304 92.688 56.408 92.712 ;
     RECT  51.304 100.224 56.408 100.248 ;
     RECT  56.408 2.148 56.512 127.452 ;
     RECT  56.512 2.418 56.704 127.182 ;
     RECT  56.704 39.456 61.808 39.48 ;
     RECT  56.704 42.48 61.808 42.504 ;
     RECT  56.704 43.632 61.808 43.656 ;
     RECT  56.704 44.928 61.808 44.952 ;
     RECT  56.704 47.664 61.808 47.736 ;
     RECT  56.704 48.72 61.808 48.744 ;
     RECT  56.704 50.064 61.808 50.088 ;
     RECT  56.704 53.856 61.808 55.224 ;
     RECT  56.704 56.208 61.808 58.2 ;
     RECT  56.704 62.976 61.808 71.16 ;
     RECT  56.704 72.192 61.808 72.216 ;
     RECT  56.704 73.296 61.808 73.656 ;
     RECT  56.704 75.168 61.808 76.584 ;
     RECT  56.704 80.256 61.808 80.28 ;
     RECT  56.704 83.52 61.808 83.544 ;
     RECT  56.704 86.784 61.808 86.808 ;
     RECT  56.704 88.608 61.808 88.632 ;
     RECT  56.704 92.688 61.808 92.712 ;
     RECT  56.704 100.224 61.808 100.248 ;
     RECT  61.808 2.148 61.912 127.452 ;
     RECT  61.912 2.418 62.104 127.182 ;
     RECT  62.104 39.456 67.208 39.48 ;
     RECT  62.104 42.48 67.208 42.504 ;
     RECT  62.104 43.632 67.208 43.656 ;
     RECT  62.104 44.928 67.208 44.952 ;
     RECT  62.104 47.664 67.208 47.736 ;
     RECT  62.104 48.72 67.208 48.744 ;
     RECT  62.104 50.064 67.208 50.088 ;
     RECT  62.104 53.856 67.208 55.224 ;
     RECT  62.104 56.208 67.208 58.2 ;
     RECT  62.104 62.976 67.208 72.216 ;
     RECT  62.104 73.296 67.208 73.656 ;
     RECT  62.104 75.168 67.208 76.584 ;
     RECT  62.104 80.256 67.208 80.28 ;
     RECT  62.104 83.52 67.208 83.544 ;
     RECT  62.104 86.784 67.208 86.808 ;
     RECT  62.104 88.608 67.208 88.632 ;
     RECT  62.104 92.688 67.208 92.712 ;
     RECT  62.104 100.224 67.208 100.248 ;
     RECT  67.208 2.148 67.312 127.452 ;
     RECT  67.312 2.418 67.504 127.182 ;
     RECT  68.677 29.808 68.713 29.832 ;
     RECT  67.504 96.576 68.749 96.792 ;
     RECT  68.713 29.232 68.785 29.832 ;
     RECT  68.785 29.232 68.821 30.6 ;
     RECT  68.821 29.232 68.893 31.416 ;
     RECT  68.893 29.232 68.929 32.232 ;
     RECT  67.504 94.368 68.929 94.392 ;
     RECT  68.929 29.232 69.041 32.376 ;
     RECT  67.504 47.664 69.253 47.736 ;
     RECT  68.749 96.48 69.253 96.792 ;
     RECT  69.041 29.232 69.397 32.328 ;
     RECT  69.253 96.48 69.493 97.704 ;
     RECT  69.493 96.48 69.721 98.136 ;
     RECT  67.504 53.856 69.865 55.224 ;
     RECT  67.504 56.208 69.865 58.2 ;
     RECT  69.253 47.328 69.973 47.736 ;
     RECT  69.721 96.48 69.973 99.048 ;
     RECT  68.605 26.64 70.009 26.664 ;
     RECT  69.973 96.192 70.069 99.048 ;
     RECT  67.504 100.224 70.069 100.248 ;
     RECT  67.504 88.608 70.081 88.632 ;
     RECT  67.504 86.784 70.115 86.808 ;
     RECT  67.504 102.24 70.549 104.088 ;
     RECT  70.441 105.12 70.549 105.144 ;
     RECT  69.865 53.856 70.597 58.2 ;
     RECT  70.549 102.24 70.597 105.144 ;
     RECT  69.973 37.584 70.645 37.608 ;
     RECT  70.597 53.856 70.693 58.968 ;
     RECT  67.504 92.688 70.765 92.712 ;
     RECT  70.597 102.24 70.945 105.192 ;
     RECT  70.945 102.24 71.017 105.48 ;
     RECT  69.973 46.848 71.125 47.736 ;
     RECT  67.504 48.72 71.125 48.744 ;
     RECT  67.504 50.064 71.125 50.088 ;
     RECT  71.125 49.824 71.161 50.088 ;
     RECT  69.397 28.944 71.173 32.328 ;
     RECT  67.504 80.256 71.173 80.28 ;
     RECT  71.125 46.848 71.221 48.744 ;
     RECT  70.765 92.688 71.273 92.76 ;
     RECT  70.657 21.792 71.521 21.816 ;
     RECT  71.173 28.752 71.593 32.328 ;
     RECT  71.521 21.408 71.629 21.816 ;
     RECT  71.629 21.408 71.665 22.776 ;
     RECT  71.665 21.216 71.737 22.776 ;
     RECT  71.593 27.936 71.749 32.328 ;
     RECT  70.081 88.608 71.749 88.68 ;
     RECT  69.445 90 71.749 90.024 ;
     RECT  71.737 20.976 72.133 22.776 ;
     RECT  71.221 46.848 72.229 48.792 ;
     RECT  71.017 102.24 72.241 105.528 ;
     RECT  70.009 26.256 72.277 26.664 ;
     RECT  71.749 27.936 72.277 32.472 ;
     RECT  72.133 20.928 72.608 22.776 ;
     RECT  72.277 26.256 72.608 32.472 ;
     RECT  70.645 37.344 72.608 37.608 ;
     RECT  67.504 39.456 72.608 39.48 ;
     RECT  70.405 41.184 72.608 41.208 ;
     RECT  67.504 42.48 72.608 42.504 ;
     RECT  67.504 43.632 72.608 43.656 ;
     RECT  67.504 44.64 72.608 44.952 ;
     RECT  72.229 46.272 72.608 48.792 ;
     RECT  71.161 49.824 72.608 50.136 ;
     RECT  71.701 51.12 72.608 51.144 ;
     RECT  70.693 53.808 72.608 58.968 ;
     RECT  70.117 60.672 72.608 60.696 ;
     RECT  67.504 62.976 72.608 72.216 ;
     RECT  67.504 73.296 72.608 73.656 ;
     RECT  67.504 75.168 72.608 76.584 ;
     RECT  71.173 79.488 72.608 80.28 ;
     RECT  72.277 81.888 72.608 81.912 ;
     RECT  67.504 83.52 72.608 83.544 ;
     RECT  72.325 87.552 72.608 87.576 ;
     RECT  71.749 88.608 72.608 90.024 ;
     RECT  70.021 91.344 72.608 91.368 ;
     RECT  71.273 92.736 72.608 92.76 ;
     RECT  68.929 94.368 72.608 95.16 ;
     RECT  70.069 96.192 72.608 100.824 ;
     RECT  72.241 102.24 72.608 105.72 ;
     RECT  72.608 2.148 72.712 127.452 ;
     RECT  72.712 2.418 72.904 127.182 ;
     RECT  72.904 81.888 73.001 82.008 ;
     RECT  72.904 53.808 73.909 61.032 ;
     RECT  73.909 53.328 74.257 61.032 ;
     RECT  72.904 62.256 74.257 73.656 ;
     RECT  72.904 83.52 74.389 83.544 ;
     RECT  72.904 20.64 74.545 22.776 ;
     RECT  72.904 94.368 74.629 95.16 ;
     RECT  72.904 96.192 74.629 100.824 ;
     RECT  74.257 53.328 74.689 73.656 ;
     RECT  74.545 19.776 74.693 22.776 ;
     RECT  72.904 87.552 75.013 87.576 ;
     RECT  72.904 88.608 75.013 90.024 ;
     RECT  72.904 91.344 75.109 91.368 ;
     RECT  72.904 92.736 75.109 92.76 ;
     RECT  74.689 52.944 75.409 73.656 ;
     RECT  74.389 82.992 75.541 83.544 ;
     RECT  72.904 102.24 75.589 105.768 ;
     RECT  72.904 43.632 75.637 44.952 ;
     RECT  72.904 46.272 75.637 48.792 ;
     RECT  72.904 85.392 75.685 85.416 ;
     RECT  74.629 94.368 75.841 100.824 ;
     RECT  75.637 43.632 75.877 48.792 ;
     RECT  72.904 49.824 75.877 51.528 ;
     RECT  75.589 102.192 76.021 105.768 ;
     RECT  75.409 52.944 76.165 73.8 ;
     RECT  72.904 74.976 76.165 76.584 ;
     RECT  72.904 26.256 76.201 32.472 ;
     RECT  76.201 25.488 76.213 32.472 ;
     RECT  75.841 78.096 76.213 78.12 ;
     RECT  72.904 79.296 76.261 80.28 ;
     RECT  75.841 93.792 76.273 100.824 ;
     RECT  76.021 101.856 76.273 105.768 ;
     RECT  76.261 79.296 76.405 80.328 ;
     RECT  75.685 85.392 76.417 86.232 ;
     RECT  75.013 87.552 76.417 90.024 ;
     RECT  72.904 39.456 76.453 39.816 ;
     RECT  72.904 41.184 76.453 41.208 ;
     RECT  76.213 77.856 76.501 78.12 ;
     RECT  73.001 81.984 76.549 82.008 ;
     RECT  75.541 82.992 76.549 83.832 ;
     RECT  76.417 85.392 76.597 90.024 ;
     RECT  75.109 91.344 76.597 92.76 ;
     RECT  76.165 52.944 76.741 76.872 ;
     RECT  76.501 77.856 76.741 78.216 ;
     RECT  74.693 19.872 76.777 22.776 ;
     RECT  76.273 93.792 76.789 105.768 ;
     RECT  76.597 85.392 76.817 92.76 ;
     RECT  76.405 79.2 76.849 80.328 ;
     RECT  76.789 93.792 76.849 106.056 ;
     RECT  76.741 52.704 76.889 78.216 ;
     RECT  76.889 61.44 76.981 78.216 ;
     RECT  76.849 79.2 76.981 80.952 ;
     RECT  75.877 43.632 77.029 51.528 ;
     RECT  76.889 52.704 77.029 60.456 ;
     RECT  76.981 61.44 77.029 80.952 ;
     RECT  76.549 81.984 77.029 83.832 ;
     RECT  72.904 37.344 77.077 37.608 ;
     RECT  76.817 85.392 77.077 90.024 ;
     RECT  77.029 61.44 77.209 83.832 ;
     RECT  76.777 19.776 77.317 22.776 ;
     RECT  76.213 25.44 77.365 32.472 ;
     RECT  77.173 17.952 77.569 17.976 ;
     RECT  77.569 17.376 77.641 17.976 ;
     RECT  77.641 17.184 77.653 17.976 ;
     RECT  77.317 19.584 77.653 22.776 ;
     RECT  76.849 93.792 77.653 106.824 ;
     RECT  77.317 9.552 77.797 9.576 ;
     RECT  77.797 8.976 77.893 9.576 ;
     RECT  77.749 113.472 77.893 113.496 ;
     RECT  77.413 114.816 77.893 114.84 ;
     RECT  77.653 17.184 77.929 22.776 ;
     RECT  77.077 85.344 77.929 90.024 ;
     RECT  76.817 91.056 77.929 92.76 ;
     RECT  77.893 8.736 78.008 9.576 ;
     RECT  77.929 17.184 78.008 23.112 ;
     RECT  77.365 25.008 78.008 32.472 ;
     RECT  77.077 37.344 78.008 37.896 ;
     RECT  76.453 39.456 78.008 41.208 ;
     RECT  72.904 42.48 78.008 42.504 ;
     RECT  77.029 43.632 78.008 60.456 ;
     RECT  77.209 61.44 78.008 84.36 ;
     RECT  77.929 85.344 78.008 92.76 ;
     RECT  77.653 93.792 78.008 107.544 ;
     RECT  77.893 113.472 78.008 114.84 ;
     RECT  77.845 116.448 78.008 116.472 ;
     RECT  78.008 2.148 78.112 127.452 ;
     RECT  78.112 2.418 78.304 127.182 ;
     RECT  78.304 113.664 79.301 115.176 ;
     RECT  78.304 37.344 79.381 37.896 ;
     RECT  78.304 11.952 79.441 13.176 ;
     RECT  79.441 11.808 79.549 13.176 ;
     RECT  78.304 112.464 79.549 112.536 ;
     RECT  78.304 110.064 79.585 110.088 ;
     RECT  78.304 8.688 79.621 9.576 ;
     RECT  79.549 11.376 79.669 13.176 ;
     RECT  78.304 14.208 79.669 14.808 ;
     RECT  78.304 39.456 79.693 107.544 ;
     RECT  79.621 8.448 79.729 9.576 ;
     RECT  79.381 37.008 79.765 37.896 ;
     RECT  79.549 112.368 79.765 112.536 ;
     RECT  78.304 120.624 79.765 120.648 ;
     RECT  79.729 8.208 79.873 9.576 ;
     RECT  79.669 11.376 79.873 14.808 ;
     RECT  79.765 36.816 79.873 37.896 ;
     RECT  79.693 39.36 79.873 107.544 ;
     RECT  79.873 8.208 80.125 14.808 ;
     RECT  79.585 110.064 80.125 110.232 ;
     RECT  79.873 36.816 80.161 107.544 ;
     RECT  80.161 35.856 80.233 107.544 ;
     RECT  79.765 112.32 80.413 112.536 ;
     RECT  78.304 116.448 80.629 117.192 ;
     RECT  80.233 35.856 80.633 107.928 ;
     RECT  80.377 34.8 80.705 34.824 ;
     RECT  79.765 120.624 80.737 121.368 ;
     RECT  80.125 109.728 80.809 110.232 ;
     RECT  79.301 113.664 80.849 114.84 ;
     RECT  80.633 35.856 80.957 43.944 ;
     RECT  80.633 44.928 81.101 86.616 ;
     RECT  81.101 44.928 81.137 86.472 ;
     RECT  80.737 120.624 81.241 121.608 ;
     RECT  81.137 57.984 81.245 86.472 ;
     RECT  81.137 44.928 81.281 56.856 ;
     RECT  81.245 59.856 81.281 86.424 ;
     RECT  81.281 59.856 81.317 85.032 ;
     RECT  81.245 57.984 81.353 58.728 ;
     RECT  80.633 87.744 81.457 107.928 ;
     RECT  81.317 59.856 81.533 76.824 ;
     RECT  80.957 35.856 81.569 43.896 ;
     RECT  81.569 39.36 81.605 43.896 ;
     RECT  81.533 61.008 81.641 76.824 ;
     RECT  81.281 86.208 81.641 86.424 ;
     RECT  80.849 113.76 81.673 114.84 ;
     RECT  81.605 42.96 81.713 43.896 ;
     RECT  81.457 87.744 81.857 108.408 ;
     RECT  81.353 57.984 81.965 58.68 ;
     RECT  81.317 77.856 81.965 85.032 ;
     RECT  81.605 39.36 82.073 41.928 ;
     RECT  81.281 44.928 82.073 55.224 ;
     RECT  82.073 49.44 82.109 55.224 ;
     RECT  78.304 25.008 82.141 32.472 ;
     RECT  81.241 120.576 82.141 121.608 ;
     RECT  81.641 61.008 82.145 76.776 ;
     RECT  82.109 49.776 82.181 55.224 ;
     RECT  81.965 78.096 82.249 85.032 ;
     RECT  81.641 86.208 82.249 86.28 ;
     RECT  80.629 116.448 82.249 117.576 ;
     RECT  82.145 61.008 82.289 73.656 ;
     RECT  82.073 44.928 82.357 48.408 ;
     RECT  82.181 50.304 82.393 55.224 ;
     RECT  81.281 56.208 82.393 56.856 ;
     RECT  82.073 39.84 82.397 41.928 ;
     RECT  81.569 35.856 82.429 38.328 ;
     RECT  82.397 39.84 82.433 40.152 ;
     RECT  82.249 78.096 82.433 86.28 ;
     RECT  82.141 120.576 82.465 121.656 ;
     RECT  78.304 17.184 82.501 23.928 ;
     RECT  82.465 120.48 82.537 121.656 ;
     RECT  82.249 116.448 82.645 118.2 ;
     RECT  81.205 119.232 82.645 119.256 ;
     RECT  82.141 24.912 82.753 32.472 ;
     RECT  82.429 35.808 82.753 38.328 ;
     RECT  81.533 59.856 82.753 59.88 ;
     RECT  82.289 61.008 82.753 66.072 ;
     RECT  81.713 42.96 82.825 43.8 ;
     RECT  82.753 24.912 82.897 33.096 ;
     RECT  82.825 42.96 82.897 43.896 ;
     RECT  82.357 44.88 82.897 48.408 ;
     RECT  82.645 116.448 82.933 119.256 ;
     RECT  82.537 120.48 82.933 121.848 ;
     RECT  80.125 7.392 83.077 14.808 ;
     RECT  82.501 16.368 83.077 23.928 ;
     RECT  82.753 59.856 83.113 66.072 ;
     RECT  81.965 58.56 83.149 58.68 ;
     RECT  83.113 59.76 83.149 66.072 ;
     RECT  81.857 87.744 83.149 88.776 ;
     RECT  80.809 109.728 83.185 110.904 ;
     RECT  80.413 111.888 83.185 112.536 ;
     RECT  82.393 50.304 83.221 56.856 ;
     RECT  83.149 58.56 83.221 66.072 ;
     RECT  81.673 113.76 83.221 114.888 ;
     RECT  82.897 24.912 83.257 33.192 ;
     RECT  82.145 74.784 83.257 76.776 ;
     RECT  82.433 78.096 83.257 85.704 ;
     RECT  81.857 90 83.257 108.408 ;
     RECT  83.077 7.392 83.293 23.928 ;
     RECT  83.257 24.912 83.293 33.24 ;
     RECT  83.293 7.392 83.365 33.24 ;
     RECT  82.933 116.448 83.365 121.848 ;
     RECT  79.693 3.648 83.408 3.672 ;
     RECT  83.365 6.816 83.408 33.24 ;
     RECT  81.961 34.464 83.408 34.488 ;
     RECT  82.753 35.808 83.408 38.664 ;
     RECT  82.433 40.128 83.408 40.152 ;
     RECT  82.397 41.184 83.408 41.928 ;
     RECT  82.897 42.96 83.408 48.408 ;
     RECT  83.221 50.304 83.408 66.072 ;
     RECT  82.289 67.2 83.408 73.656 ;
     RECT  83.257 74.784 83.408 85.704 ;
     RECT  83.149 87.744 83.408 88.92 ;
     RECT  83.257 90 83.408 108.456 ;
     RECT  83.185 109.728 83.408 112.536 ;
     RECT  83.221 113.76 83.408 115.416 ;
     RECT  83.365 116.448 83.408 122.712 ;
     RECT  83.408 2.148 83.512 127.452 ;
     RECT  83.512 2.418 83.704 127.182 ;
     RECT  83.704 64.368 83.729 64.392 ;
     RECT  83.704 36 83.765 36.84 ;
     RECT  83.704 51.408 83.765 51.432 ;
     RECT  83.704 58.656 83.765 58.776 ;
     RECT  83.704 66 83.765 66.024 ;
     RECT  83.704 70.368 83.765 70.392 ;
     RECT  83.704 84.864 83.765 84.888 ;
     RECT  83.704 88.896 83.765 88.92 ;
     RECT  83.704 50.304 83.801 50.328 ;
     RECT  83.765 58.752 83.801 58.776 ;
     RECT  83.704 67.824 83.801 67.848 ;
     RECT  83.704 48.192 83.837 48.216 ;
     RECT  83.704 69.264 83.837 69.288 ;
     RECT  83.704 83.76 83.837 83.784 ;
     RECT  83.704 72 83.909 72.024 ;
     RECT  83.704 53.28 83.981 53.304 ;
     RECT  83.704 92.736 84.089 92.76 ;
     RECT  83.704 61.008 84.197 61.032 ;
     RECT  83.704 94.08 84.197 94.584 ;
     RECT  83.704 56.976 84.233 57 ;
     RECT  83.704 81.648 84.269 81.672 ;
     RECT  83.765 36.816 84.305 36.84 ;
     RECT  84.197 94.416 84.413 94.584 ;
     RECT  83.704 5.76 84.485 33.096 ;
     RECT  84.485 5.76 84.521 32.52 ;
     RECT  83.704 43.008 84.557 43.032 ;
     RECT  83.704 41.616 84.593 41.64 ;
     RECT  84.413 94.416 84.593 94.44 ;
     RECT  83.704 40.128 84.953 40.152 ;
     RECT  83.704 34.464 84.989 34.488 ;
     RECT  83.704 3.648 86.197 3.672 ;
     RECT  86.197 2.88 86.243 3.672 ;
     RECT  83.704 95.952 86.285 122.712 ;
     RECT  86.281 73.536 86.317 73.56 ;
     RECT  86.243 2.88 86.387 2.904 ;
     RECT  84.521 5.76 86.4 32.472 ;
     RECT  86.317 73.44 86.4 73.56 ;
     RECT  86.285 96 86.4 122.712 ;
    LAYER M5 ;
     RECT  2.4 2.137 2.52 2.151 ;
     RECT  7.8 2.137 7.92 2.151 ;
     RECT  13.2 2.137 13.32 2.151 ;
     RECT  18.6 2.137 18.72 2.151 ;
     RECT  24 2.137 24.12 2.151 ;
     RECT  29.4 2.137 29.52 2.151 ;
     RECT  34.8 2.137 34.92 2.151 ;
     RECT  40.2 2.137 40.32 2.151 ;
     RECT  45.6 2.137 45.72 2.151 ;
     RECT  51 2.137 51.12 2.151 ;
     RECT  56.4 2.137 56.52 2.151 ;
     RECT  61.8 2.137 61.92 2.151 ;
     RECT  67.2 2.137 67.32 2.151 ;
     RECT  72.6 2.137 72.72 2.151 ;
     RECT  78 2.137 78.12 2.151 ;
     RECT  83.4 2.137 83.52 2.151 ;
     RECT  86.208 2.915 86.232 3.683 ;
     RECT  78 2.151 78.312 8.965 ;
     RECT  77.808 8.965 78.312 9.109 ;
     RECT  77.808 9.109 78.456 11.941 ;
     RECT  77.808 11.941 79.176 13.909 ;
     RECT  77.808 13.909 79.704 17.941 ;
     RECT  77.184 17.941 79.704 18.181 ;
     RECT  72.6 2.151 72.912 20.629 ;
     RECT  77.184 18.181 79.752 23.125 ;
     RECT  77.184 23.125 79.8 25.429 ;
     RECT  72.6 20.629 73.272 27.061 ;
     RECT  72.288 27.061 73.272 28.213 ;
     RECT  72.288 28.213 73.368 29.557 ;
     RECT  76.224 25.429 79.8 30.325 ;
     RECT  75.696 30.325 79.8 30.613 ;
     RECT  72.288 29.557 73.512 30.805 ;
     RECT  75.12 30.613 79.8 30.805 ;
     RECT  69.456 31.237 69.48 31.717 ;
     RECT  71.184 28.741 71.208 32.437 ;
     RECT  72.288 30.805 79.8 32.437 ;
     RECT  71.184 32.437 79.8 36.851 ;
     RECT  69.456 31.717 70.056 37.333 ;
     RECT  71.184 36.851 79.752 37.333 ;
     RECT  69.456 37.333 79.752 40.837 ;
     RECT  69.456 40.837 79.8 41.411 ;
     RECT  69.456 41.411 79.752 43.813 ;
     RECT  69.456 43.813 79.8 48.803 ;
     RECT  69.456 48.803 79.704 57.973 ;
     RECT  10.032 63.589 10.056 63.731 ;
     RECT  69.456 57.973 79.752 64.645 ;
     RECT  69.456 64.645 79.8 64.931 ;
     RECT  69.456 64.931 79.752 70.693 ;
     RECT  69.456 70.693 79.8 71.267 ;
     RECT  69.456 71.267 79.752 79.813 ;
     RECT  6.672 68.149 6.696 79.957 ;
     RECT  69.456 79.813 79.8 90.035 ;
     RECT  69.504 90.035 79.8 90.083 ;
     RECT  6.672 79.957 6.792 92.723 ;
     RECT  69.504 90.083 79.752 95.653 ;
     RECT  69.504 95.653 79.8 97.571 ;
     RECT  69.504 97.571 73.992 97.667 ;
     RECT  75.216 97.571 79.8 97.907 ;
     RECT  69.504 97.667 73.944 98.147 ;
     RECT  70.08 98.147 73.944 99.491 ;
     RECT  70.08 99.491 73.656 100.355 ;
     RECT  70.08 100.355 73.32 100.595 ;
     RECT  70.08 100.595 70.632 100.835 ;
     RECT  75.6 97.907 79.8 102.227 ;
     RECT  76.08 102.227 79.8 102.467 ;
     RECT  76.128 102.467 79.8 103.859 ;
     RECT  76.656 103.859 79.8 104.867 ;
     RECT  70.608 100.835 70.632 105.203 ;
     RECT  71.664 100.595 73.32 105.443 ;
     RECT  72.6 105.443 73.32 105.779 ;
     RECT  76.8 104.867 79.8 106.067 ;
     RECT  77.04 106.067 79.8 106.739 ;
     RECT  6.672 92.723 6.696 112.355 ;
     RECT  77.424 106.739 79.8 112.355 ;
     RECT  77.424 112.355 79.176 114.851 ;
     RECT  77.856 114.851 79.176 116.483 ;
     RECT  78 116.483 79.176 117.155 ;
     RECT  78 117.155 78.6 117.203 ;
     RECT  2.4 2.151 2.712 127.449 ;
     RECT  7.8 2.151 8.112 127.449 ;
     RECT  13.2 2.151 13.512 127.449 ;
     RECT  18.6 2.151 18.912 127.449 ;
     RECT  24 2.151 24.312 127.449 ;
     RECT  29.4 2.151 29.712 127.449 ;
     RECT  34.8 2.151 35.112 127.449 ;
     RECT  40.2 2.151 40.512 127.449 ;
     RECT  45.6 2.151 45.912 127.449 ;
     RECT  51 2.151 51.312 127.449 ;
     RECT  56.4 2.151 56.712 127.449 ;
     RECT  61.8 2.151 62.112 127.449 ;
     RECT  67.2 2.151 67.512 127.449 ;
     RECT  72.6 105.779 72.912 127.449 ;
     RECT  78 117.203 78.312 127.449 ;
     RECT  83.4 2.151 83.712 127.449 ;
     RECT  2.4 127.449 2.52 127.463 ;
     RECT  7.8 127.449 7.92 127.463 ;
     RECT  13.2 127.449 13.32 127.463 ;
     RECT  18.6 127.449 18.72 127.463 ;
     RECT  24 127.449 24.12 127.463 ;
     RECT  29.4 127.449 29.52 127.463 ;
     RECT  34.8 127.449 34.92 127.463 ;
     RECT  40.2 127.449 40.32 127.463 ;
     RECT  45.6 127.449 45.72 127.463 ;
     RECT  51 127.449 51.12 127.463 ;
     RECT  56.4 127.449 56.52 127.463 ;
     RECT  61.8 127.449 61.92 127.463 ;
     RECT  67.2 127.449 67.32 127.463 ;
     RECT  72.6 127.449 72.72 127.463 ;
     RECT  78 127.449 78.12 127.463 ;
     RECT  83.4 127.449 83.52 127.463 ;
     RECT  71.208 28.741 72.288 32.437 ;
     RECT  70.056 31.717 71.184 37.333 ;
     RECT  6.696 68.149 7.8 79.957 ;
     RECT  6.792 79.957 7.8 92.723 ;
     RECT  6.696 92.723 7.8 112.355 ;
     RECT  73.992 97.571 75.216 97.667 ;
     RECT  73.944 97.667 75.216 97.907 ;
     RECT  70.632 100.595 71.664 105.203 ;
  END
END ot_hgi_sm_pub_vmcore
END LIBRARY
